VERSION 5.8 ;
BUSBITCHARS "[]" ;
DIVIDERCHAR "/" ;
UNITS
    DATABASE MICRONS 1000 ;
END UNITS

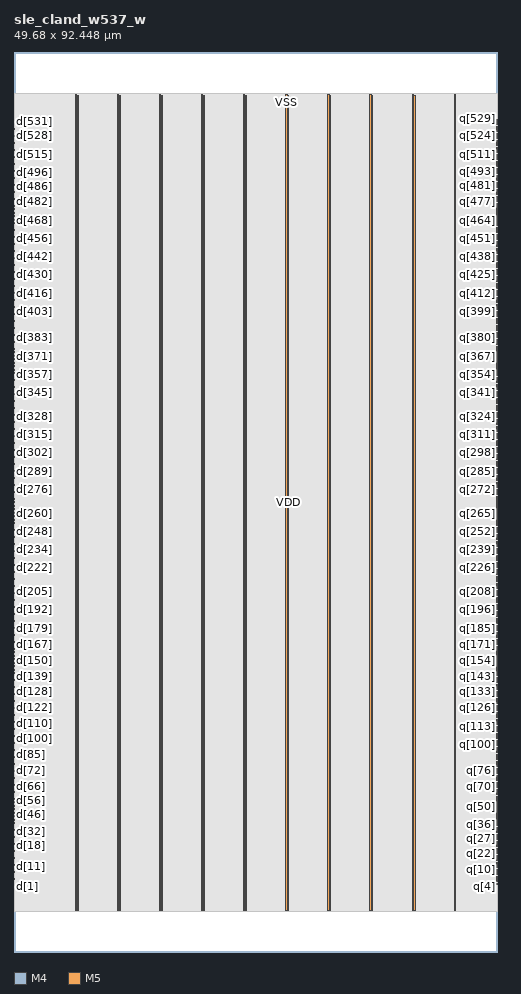
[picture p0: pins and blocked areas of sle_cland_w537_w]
MACRO sle_cland_w537_w
  FOREIGN sle_cland_w537_w 0 0 ;
  CLASS BLOCK ;
  SIZE 49.68 BY 92.448 ;
  PIN clk
    DIRECTION INPUT ;
    USE SIGNAL ;
    PORT
      LAYER M4 ;
        RECT  49.596 45.504 49.68 45.528 ;
    END
  END clk
  PIN d[0]
    DIRECTION INPUT ;
    USE SIGNAL ;
    PORT
      LAYER M4 ;
        RECT  0 7.632 0.084 7.656 ;
    END
  END d[0]
  PIN d[100]
    DIRECTION INPUT ;
    USE SIGNAL ;
    PORT
      LAYER M4 ;
        RECT  0 21.888 0.084 21.912 ;
    END
  END d[100]
  PIN d[101]
    DIRECTION INPUT ;
    USE SIGNAL ;
    PORT
      LAYER M4 ;
        RECT  0 22.032 0.084 22.056 ;
    END
  END d[101]
  PIN d[102]
    DIRECTION INPUT ;
    USE SIGNAL ;
    PORT
      LAYER M4 ;
        RECT  0 22.176 0.084 22.2 ;
    END
  END d[102]
  PIN d[103]
    DIRECTION INPUT ;
    USE SIGNAL ;
    PORT
      LAYER M4 ;
        RECT  0 22.32 0.084 22.344 ;
    END
  END d[103]
  PIN d[104]
    DIRECTION INPUT ;
    USE SIGNAL ;
    PORT
      LAYER M4 ;
        RECT  0 22.464 0.084 22.488 ;
    END
  END d[104]
  PIN d[105]
    DIRECTION INPUT ;
    USE SIGNAL ;
    PORT
      LAYER M4 ;
        RECT  0 22.608 0.084 22.632 ;
    END
  END d[105]
  PIN d[106]
    DIRECTION INPUT ;
    USE SIGNAL ;
    PORT
      LAYER M4 ;
        RECT  0 22.752 0.084 22.776 ;
    END
  END d[106]
  PIN d[107]
    DIRECTION INPUT ;
    USE SIGNAL ;
    PORT
      LAYER M4 ;
        RECT  0 22.896 0.084 22.92 ;
    END
  END d[107]
  PIN d[108]
    DIRECTION INPUT ;
    USE SIGNAL ;
    PORT
      LAYER M4 ;
        RECT  0 23.328 0.084 23.352 ;
    END
  END d[108]
  PIN d[109]
    DIRECTION INPUT ;
    USE SIGNAL ;
    PORT
      LAYER M4 ;
        RECT  0 23.04 0.084 23.064 ;
    END
  END d[109]
  PIN d[10]
    DIRECTION INPUT ;
    USE SIGNAL ;
    PORT
      LAYER M4 ;
        RECT  0 9.072 0.084 9.096 ;
    END
  END d[10]
  PIN d[110]
    DIRECTION INPUT ;
    USE SIGNAL ;
    PORT
      LAYER M4 ;
        RECT  0 23.472 0.084 23.496 ;
    END
  END d[110]
  PIN d[111]
    DIRECTION INPUT ;
    USE SIGNAL ;
    PORT
      LAYER M4 ;
        RECT  0 23.184 0.084 23.208 ;
    END
  END d[111]
  PIN d[112]
    DIRECTION INPUT ;
    USE SIGNAL ;
    PORT
      LAYER M4 ;
        RECT  0 23.616 0.084 23.64 ;
    END
  END d[112]
  PIN d[113]
    DIRECTION INPUT ;
    USE SIGNAL ;
    PORT
      LAYER M4 ;
        RECT  0 23.76 0.084 23.784 ;
    END
  END d[113]
  PIN d[114]
    DIRECTION INPUT ;
    USE SIGNAL ;
    PORT
      LAYER M4 ;
        RECT  0 23.904 0.084 23.928 ;
    END
  END d[114]
  PIN d[115]
    DIRECTION INPUT ;
    USE SIGNAL ;
    PORT
      LAYER M4 ;
        RECT  0 24.048 0.084 24.072 ;
    END
  END d[115]
  PIN d[116]
    DIRECTION INPUT ;
    USE SIGNAL ;
    PORT
      LAYER M4 ;
        RECT  0 24.192 0.084 24.216 ;
    END
  END d[116]
  PIN d[117]
    DIRECTION INPUT ;
    USE SIGNAL ;
    PORT
      LAYER M4 ;
        RECT  0 24.336 0.084 24.36 ;
    END
  END d[117]
  PIN d[118]
    DIRECTION INPUT ;
    USE SIGNAL ;
    PORT
      LAYER M4 ;
        RECT  0 24.48 0.084 24.504 ;
    END
  END d[118]
  PIN d[119]
    DIRECTION INPUT ;
    USE SIGNAL ;
    PORT
      LAYER M4 ;
        RECT  0 24.624 0.084 24.648 ;
    END
  END d[119]
  PIN d[11]
    DIRECTION INPUT ;
    USE SIGNAL ;
    PORT
      LAYER M4 ;
        RECT  0 8.784 0.084 8.808 ;
    END
  END d[11]
  PIN d[120]
    DIRECTION INPUT ;
    USE SIGNAL ;
    PORT
      LAYER M4 ;
        RECT  0 24.768 0.084 24.792 ;
    END
  END d[120]
  PIN d[121]
    DIRECTION INPUT ;
    USE SIGNAL ;
    PORT
      LAYER M4 ;
        RECT  0 24.912 0.084 24.936 ;
    END
  END d[121]
  PIN d[122]
    DIRECTION INPUT ;
    USE SIGNAL ;
    PORT
      LAYER M4 ;
        RECT  0 25.056 0.084 25.08 ;
    END
  END d[122]
  PIN d[123]
    DIRECTION INPUT ;
    USE SIGNAL ;
    PORT
      LAYER M4 ;
        RECT  0 25.2 0.084 25.224 ;
    END
  END d[123]
  PIN d[124]
    DIRECTION INPUT ;
    USE SIGNAL ;
    PORT
      LAYER M4 ;
        RECT  0 25.344 0.084 25.368 ;
    END
  END d[124]
  PIN d[125]
    DIRECTION INPUT ;
    USE SIGNAL ;
    PORT
      LAYER M4 ;
        RECT  0 25.488 0.084 25.512 ;
    END
  END d[125]
  PIN d[126]
    DIRECTION INPUT ;
    USE SIGNAL ;
    PORT
      LAYER M4 ;
        RECT  0 25.632 0.084 25.656 ;
    END
  END d[126]
  PIN d[127]
    DIRECTION INPUT ;
    USE SIGNAL ;
    PORT
      LAYER M4 ;
        RECT  0 25.776 0.084 25.8 ;
    END
  END d[127]
  PIN d[128]
    DIRECTION INPUT ;
    USE SIGNAL ;
    PORT
      LAYER M4 ;
        RECT  0 25.92 0.084 25.944 ;
    END
  END d[128]
  PIN d[129]
    DIRECTION INPUT ;
    USE SIGNAL ;
    PORT
      LAYER M4 ;
        RECT  0 26.064 0.084 26.088 ;
    END
  END d[129]
  PIN d[12]
    DIRECTION INPUT ;
    USE SIGNAL ;
    PORT
      LAYER M4 ;
        RECT  0 9.36 0.084 9.384 ;
    END
  END d[12]
  PIN d[130]
    DIRECTION INPUT ;
    USE SIGNAL ;
    PORT
      LAYER M4 ;
        RECT  0 26.208 0.084 26.232 ;
    END
  END d[130]
  PIN d[131]
    DIRECTION INPUT ;
    USE SIGNAL ;
    PORT
      LAYER M4 ;
        RECT  0 26.352 0.084 26.376 ;
    END
  END d[131]
  PIN d[132]
    DIRECTION INPUT ;
    USE SIGNAL ;
    PORT
      LAYER M4 ;
        RECT  0 26.784 0.084 26.808 ;
    END
  END d[132]
  PIN d[133]
    DIRECTION INPUT ;
    USE SIGNAL ;
    PORT
      LAYER M4 ;
        RECT  0 26.496 0.084 26.52 ;
    END
  END d[133]
  PIN d[134]
    DIRECTION INPUT ;
    USE SIGNAL ;
    PORT
      LAYER M4 ;
        RECT  0 26.928 0.084 26.952 ;
    END
  END d[134]
  PIN d[135]
    DIRECTION INPUT ;
    USE SIGNAL ;
    PORT
      LAYER M4 ;
        RECT  0 26.64 0.084 26.664 ;
    END
  END d[135]
  PIN d[136]
    DIRECTION INPUT ;
    USE SIGNAL ;
    PORT
      LAYER M4 ;
        RECT  0 27.216 0.084 27.24 ;
    END
  END d[136]
  PIN d[137]
    DIRECTION INPUT ;
    USE SIGNAL ;
    PORT
      LAYER M4 ;
        RECT  0 27.072 0.084 27.096 ;
    END
  END d[137]
  PIN d[138]
    DIRECTION INPUT ;
    USE SIGNAL ;
    PORT
      LAYER M4 ;
        RECT  0 27.36 0.084 27.384 ;
    END
  END d[138]
  PIN d[139]
    DIRECTION INPUT ;
    USE SIGNAL ;
    PORT
      LAYER M4 ;
        RECT  0 27.504 0.084 27.528 ;
    END
  END d[139]
  PIN d[13]
    DIRECTION INPUT ;
    USE SIGNAL ;
    PORT
      LAYER M4 ;
        RECT  0 9.216 0.084 9.24 ;
    END
  END d[13]
  PIN d[140]
    DIRECTION INPUT ;
    USE SIGNAL ;
    PORT
      LAYER M4 ;
        RECT  0 27.648 0.084 27.672 ;
    END
  END d[140]
  PIN d[141]
    DIRECTION INPUT ;
    USE SIGNAL ;
    PORT
      LAYER M4 ;
        RECT  0 27.792 0.084 27.816 ;
    END
  END d[141]
  PIN d[142]
    DIRECTION INPUT ;
    USE SIGNAL ;
    PORT
      LAYER M4 ;
        RECT  0 27.936 0.084 27.96 ;
    END
  END d[142]
  PIN d[143]
    DIRECTION INPUT ;
    USE SIGNAL ;
    PORT
      LAYER M4 ;
        RECT  0 28.08 0.084 28.104 ;
    END
  END d[143]
  PIN d[144]
    DIRECTION INPUT ;
    USE SIGNAL ;
    PORT
      LAYER M4 ;
        RECT  0 28.224 0.084 28.248 ;
    END
  END d[144]
  PIN d[145]
    DIRECTION INPUT ;
    USE SIGNAL ;
    PORT
      LAYER M4 ;
        RECT  0 28.368 0.084 28.392 ;
    END
  END d[145]
  PIN d[146]
    DIRECTION INPUT ;
    USE SIGNAL ;
    PORT
      LAYER M4 ;
        RECT  0 28.512 0.084 28.536 ;
    END
  END d[146]
  PIN d[147]
    DIRECTION INPUT ;
    USE SIGNAL ;
    PORT
      LAYER M4 ;
        RECT  0 28.656 0.084 28.68 ;
    END
  END d[147]
  PIN d[148]
    DIRECTION INPUT ;
    USE SIGNAL ;
    PORT
      LAYER M4 ;
        RECT  0 28.8 0.084 28.824 ;
    END
  END d[148]
  PIN d[149]
    DIRECTION INPUT ;
    USE SIGNAL ;
    PORT
      LAYER M4 ;
        RECT  0 28.944 0.084 28.968 ;
    END
  END d[149]
  PIN d[14]
    DIRECTION INPUT ;
    USE SIGNAL ;
    PORT
      LAYER M4 ;
        RECT  0 9.504 0.084 9.528 ;
    END
  END d[14]
  PIN d[150]
    DIRECTION INPUT ;
    USE SIGNAL ;
    PORT
      LAYER M4 ;
        RECT  0 29.088 0.084 29.112 ;
    END
  END d[150]
  PIN d[151]
    DIRECTION INPUT ;
    USE SIGNAL ;
    PORT
      LAYER M4 ;
        RECT  0 29.232 0.084 29.256 ;
    END
  END d[151]
  PIN d[152]
    DIRECTION INPUT ;
    USE SIGNAL ;
    PORT
      LAYER M4 ;
        RECT  0 29.376 0.084 29.4 ;
    END
  END d[152]
  PIN d[153]
    DIRECTION INPUT ;
    USE SIGNAL ;
    PORT
      LAYER M4 ;
        RECT  0 29.52 0.084 29.544 ;
    END
  END d[153]
  PIN d[154]
    DIRECTION INPUT ;
    USE SIGNAL ;
    PORT
      LAYER M4 ;
        RECT  0 29.664 0.084 29.688 ;
    END
  END d[154]
  PIN d[155]
    DIRECTION INPUT ;
    USE SIGNAL ;
    PORT
      LAYER M4 ;
        RECT  0 29.808 0.084 29.832 ;
    END
  END d[155]
  PIN d[156]
    DIRECTION INPUT ;
    USE SIGNAL ;
    PORT
      LAYER M4 ;
        RECT  0 29.952 0.084 29.976 ;
    END
  END d[156]
  PIN d[157]
    DIRECTION INPUT ;
    USE SIGNAL ;
    PORT
      LAYER M4 ;
        RECT  0 30.096 0.084 30.12 ;
    END
  END d[157]
  PIN d[158]
    DIRECTION INPUT ;
    USE SIGNAL ;
    PORT
      LAYER M4 ;
        RECT  0 30.384 0.084 30.408 ;
    END
  END d[158]
  PIN d[159]
    DIRECTION INPUT ;
    USE SIGNAL ;
    PORT
      LAYER M4 ;
        RECT  0 30.24 0.084 30.264 ;
    END
  END d[159]
  PIN d[15]
    DIRECTION INPUT ;
    USE SIGNAL ;
    PORT
      LAYER M4 ;
        RECT  0 9.648 0.084 9.672 ;
    END
  END d[15]
  PIN d[160]
    DIRECTION INPUT ;
    USE SIGNAL ;
    PORT
      LAYER M4 ;
        RECT  0 30.672 0.084 30.696 ;
    END
  END d[160]
  PIN d[161]
    DIRECTION INPUT ;
    USE SIGNAL ;
    PORT
      LAYER M4 ;
        RECT  0 30.528 0.084 30.552 ;
    END
  END d[161]
  PIN d[162]
    DIRECTION INPUT ;
    USE SIGNAL ;
    PORT
      LAYER M4 ;
        RECT  0 30.816 0.084 30.84 ;
    END
  END d[162]
  PIN d[163]
    DIRECTION INPUT ;
    USE SIGNAL ;
    PORT
      LAYER M4 ;
        RECT  0 30.96 0.084 30.984 ;
    END
  END d[163]
  PIN d[164]
    DIRECTION INPUT ;
    USE SIGNAL ;
    PORT
      LAYER M4 ;
        RECT  0 31.104 0.084 31.128 ;
    END
  END d[164]
  PIN d[165]
    DIRECTION INPUT ;
    USE SIGNAL ;
    PORT
      LAYER M4 ;
        RECT  0 31.248 0.084 31.272 ;
    END
  END d[165]
  PIN d[166]
    DIRECTION INPUT ;
    USE SIGNAL ;
    PORT
      LAYER M4 ;
        RECT  0 31.392 0.084 31.416 ;
    END
  END d[166]
  PIN d[167]
    DIRECTION INPUT ;
    USE SIGNAL ;
    PORT
      LAYER M4 ;
        RECT  0 31.536 0.084 31.56 ;
    END
  END d[167]
  PIN d[168]
    DIRECTION INPUT ;
    USE SIGNAL ;
    PORT
      LAYER M4 ;
        RECT  0 31.68 0.084 31.704 ;
    END
  END d[168]
  PIN d[169]
    DIRECTION INPUT ;
    USE SIGNAL ;
    PORT
      LAYER M4 ;
        RECT  0 31.824 0.084 31.848 ;
    END
  END d[169]
  PIN d[16]
    DIRECTION INPUT ;
    USE SIGNAL ;
    PORT
      LAYER M4 ;
        RECT  0 9.792 0.084 9.816 ;
    END
  END d[16]
  PIN d[170]
    DIRECTION INPUT ;
    USE SIGNAL ;
    PORT
      LAYER M4 ;
        RECT  0 31.968 0.084 31.992 ;
    END
  END d[170]
  PIN d[171]
    DIRECTION INPUT ;
    USE SIGNAL ;
    PORT
      LAYER M4 ;
        RECT  0 32.112 0.084 32.136 ;
    END
  END d[171]
  PIN d[172]
    DIRECTION INPUT ;
    USE SIGNAL ;
    PORT
      LAYER M4 ;
        RECT  0 32.256 0.084 32.28 ;
    END
  END d[172]
  PIN d[173]
    DIRECTION INPUT ;
    USE SIGNAL ;
    PORT
      LAYER M4 ;
        RECT  0 32.4 0.084 32.424 ;
    END
  END d[173]
  PIN d[174]
    DIRECTION INPUT ;
    USE SIGNAL ;
    PORT
      LAYER M4 ;
        RECT  0 32.544 0.084 32.568 ;
    END
  END d[174]
  PIN d[175]
    DIRECTION INPUT ;
    USE SIGNAL ;
    PORT
      LAYER M4 ;
        RECT  0 32.688 0.084 32.712 ;
    END
  END d[175]
  PIN d[176]
    DIRECTION INPUT ;
    USE SIGNAL ;
    PORT
      LAYER M4 ;
        RECT  0 32.832 0.084 32.856 ;
    END
  END d[176]
  PIN d[177]
    DIRECTION INPUT ;
    USE SIGNAL ;
    PORT
      LAYER M4 ;
        RECT  0 32.976 0.084 33 ;
    END
  END d[177]
  PIN d[178]
    DIRECTION INPUT ;
    USE SIGNAL ;
    PORT
      LAYER M4 ;
        RECT  0 33.12 0.084 33.144 ;
    END
  END d[178]
  PIN d[179]
    DIRECTION INPUT ;
    USE SIGNAL ;
    PORT
      LAYER M4 ;
        RECT  0 33.264 0.084 33.288 ;
    END
  END d[179]
  PIN d[17]
    DIRECTION INPUT ;
    USE SIGNAL ;
    PORT
      LAYER M4 ;
        RECT  0 9.936 0.084 9.96 ;
    END
  END d[17]
  PIN d[180]
    DIRECTION INPUT ;
    USE SIGNAL ;
    PORT
      LAYER M4 ;
        RECT  0 33.408 0.084 33.432 ;
    END
  END d[180]
  PIN d[181]
    DIRECTION INPUT ;
    USE SIGNAL ;
    PORT
      LAYER M4 ;
        RECT  0 33.552 0.084 33.576 ;
    END
  END d[181]
  PIN d[182]
    DIRECTION INPUT ;
    USE SIGNAL ;
    PORT
      LAYER M4 ;
        RECT  0 33.984 0.084 34.008 ;
    END
  END d[182]
  PIN d[183]
    DIRECTION INPUT ;
    USE SIGNAL ;
    PORT
      LAYER M4 ;
        RECT  0 33.696 0.084 33.72 ;
    END
  END d[183]
  PIN d[184]
    DIRECTION INPUT ;
    USE SIGNAL ;
    PORT
      LAYER M4 ;
        RECT  0 34.128 0.084 34.152 ;
    END
  END d[184]
  PIN d[185]
    DIRECTION INPUT ;
    USE SIGNAL ;
    PORT
      LAYER M4 ;
        RECT  0 33.84 0.084 33.864 ;
    END
  END d[185]
  PIN d[186]
    DIRECTION INPUT ;
    USE SIGNAL ;
    PORT
      LAYER M4 ;
        RECT  0 34.416 0.084 34.44 ;
    END
  END d[186]
  PIN d[187]
    DIRECTION INPUT ;
    USE SIGNAL ;
    PORT
      LAYER M4 ;
        RECT  0 34.272 0.084 34.296 ;
    END
  END d[187]
  PIN d[188]
    DIRECTION INPUT ;
    USE SIGNAL ;
    PORT
      LAYER M4 ;
        RECT  0 34.56 0.084 34.584 ;
    END
  END d[188]
  PIN d[189]
    DIRECTION INPUT ;
    USE SIGNAL ;
    PORT
      LAYER M4 ;
        RECT  0 34.704 0.084 34.728 ;
    END
  END d[189]
  PIN d[18]
    DIRECTION INPUT ;
    USE SIGNAL ;
    PORT
      LAYER M4 ;
        RECT  0 10.08 0.084 10.104 ;
    END
  END d[18]
  PIN d[190]
    DIRECTION INPUT ;
    USE SIGNAL ;
    PORT
      LAYER M4 ;
        RECT  0 34.848 0.084 34.872 ;
    END
  END d[190]
  PIN d[191]
    DIRECTION INPUT ;
    USE SIGNAL ;
    PORT
      LAYER M4 ;
        RECT  0 34.992 0.084 35.016 ;
    END
  END d[191]
  PIN d[192]
    DIRECTION INPUT ;
    USE SIGNAL ;
    PORT
      LAYER M4 ;
        RECT  0 35.136 0.084 35.16 ;
    END
  END d[192]
  PIN d[193]
    DIRECTION INPUT ;
    USE SIGNAL ;
    PORT
      LAYER M4 ;
        RECT  0 35.28 0.084 35.304 ;
    END
  END d[193]
  PIN d[194]
    DIRECTION INPUT ;
    USE SIGNAL ;
    PORT
      LAYER M4 ;
        RECT  0 35.424 0.084 35.448 ;
    END
  END d[194]
  PIN d[195]
    DIRECTION INPUT ;
    USE SIGNAL ;
    PORT
      LAYER M4 ;
        RECT  0 35.568 0.084 35.592 ;
    END
  END d[195]
  PIN d[196]
    DIRECTION INPUT ;
    USE SIGNAL ;
    PORT
      LAYER M4 ;
        RECT  0 35.712 0.084 35.736 ;
    END
  END d[196]
  PIN d[197]
    DIRECTION INPUT ;
    USE SIGNAL ;
    PORT
      LAYER M4 ;
        RECT  0 35.856 0.084 35.88 ;
    END
  END d[197]
  PIN d[198]
    DIRECTION INPUT ;
    USE SIGNAL ;
    PORT
      LAYER M4 ;
        RECT  0 36 0.084 36.024 ;
    END
  END d[198]
  PIN d[199]
    DIRECTION INPUT ;
    USE SIGNAL ;
    PORT
      LAYER M4 ;
        RECT  0 36.144 0.084 36.168 ;
    END
  END d[199]
  PIN d[19]
    DIRECTION INPUT ;
    USE SIGNAL ;
    PORT
      LAYER M4 ;
        RECT  0 10.224 0.084 10.248 ;
    END
  END d[19]
  PIN d[1]
    DIRECTION INPUT ;
    USE SIGNAL ;
    PORT
      LAYER M4 ;
        RECT  0 7.488 0.084 7.512 ;
    END
  END d[1]
  PIN d[200]
    DIRECTION INPUT ;
    USE SIGNAL ;
    PORT
      LAYER M4 ;
        RECT  0 36.288 0.084 36.312 ;
    END
  END d[200]
  PIN d[201]
    DIRECTION INPUT ;
    USE SIGNAL ;
    PORT
      LAYER M4 ;
        RECT  0 36.432 0.084 36.456 ;
    END
  END d[201]
  PIN d[202]
    DIRECTION INPUT ;
    USE SIGNAL ;
    PORT
      LAYER M4 ;
        RECT  0 36.576 0.084 36.6 ;
    END
  END d[202]
  PIN d[203]
    DIRECTION INPUT ;
    USE SIGNAL ;
    PORT
      LAYER M4 ;
        RECT  0 36.72 0.084 36.744 ;
    END
  END d[203]
  PIN d[204]
    DIRECTION INPUT ;
    USE SIGNAL ;
    PORT
      LAYER M4 ;
        RECT  0 36.864 0.084 36.888 ;
    END
  END d[204]
  PIN d[205]
    DIRECTION INPUT ;
    USE SIGNAL ;
    PORT
      LAYER M4 ;
        RECT  0 37.008 0.084 37.032 ;
    END
  END d[205]
  PIN d[206]
    DIRECTION INPUT ;
    USE SIGNAL ;
    PORT
      LAYER M4 ;
        RECT  0 37.152 0.084 37.176 ;
    END
  END d[206]
  PIN d[207]
    DIRECTION INPUT ;
    USE SIGNAL ;
    PORT
      LAYER M4 ;
        RECT  0 37.296 0.084 37.32 ;
    END
  END d[207]
  PIN d[208]
    DIRECTION INPUT ;
    USE SIGNAL ;
    PORT
      LAYER M4 ;
        RECT  0 37.584 0.084 37.608 ;
    END
  END d[208]
  PIN d[209]
    DIRECTION INPUT ;
    USE SIGNAL ;
    PORT
      LAYER M4 ;
        RECT  0 37.44 0.084 37.464 ;
    END
  END d[209]
  PIN d[20]
    DIRECTION INPUT ;
    USE SIGNAL ;
    PORT
      LAYER M4 ;
        RECT  0 10.512 0.084 10.536 ;
    END
  END d[20]
  PIN d[210]
    DIRECTION INPUT ;
    USE SIGNAL ;
    PORT
      LAYER M4 ;
        RECT  0 37.872 0.084 37.896 ;
    END
  END d[210]
  PIN d[211]
    DIRECTION INPUT ;
    USE SIGNAL ;
    PORT
      LAYER M4 ;
        RECT  0 37.728 0.084 37.752 ;
    END
  END d[211]
  PIN d[212]
    DIRECTION INPUT ;
    USE SIGNAL ;
    PORT
      LAYER M4 ;
        RECT  0 38.016 0.084 38.04 ;
    END
  END d[212]
  PIN d[213]
    DIRECTION INPUT ;
    USE SIGNAL ;
    PORT
      LAYER M4 ;
        RECT  0 38.16 0.084 38.184 ;
    END
  END d[213]
  PIN d[214]
    DIRECTION INPUT ;
    USE SIGNAL ;
    PORT
      LAYER M4 ;
        RECT  0 38.304 0.084 38.328 ;
    END
  END d[214]
  PIN d[215]
    DIRECTION INPUT ;
    USE SIGNAL ;
    PORT
      LAYER M4 ;
        RECT  0 38.448 0.084 38.472 ;
    END
  END d[215]
  PIN d[216]
    DIRECTION INPUT ;
    USE SIGNAL ;
    PORT
      LAYER M4 ;
        RECT  0 38.592 0.084 38.616 ;
    END
  END d[216]
  PIN d[217]
    DIRECTION INPUT ;
    USE SIGNAL ;
    PORT
      LAYER M4 ;
        RECT  0 38.736 0.084 38.76 ;
    END
  END d[217]
  PIN d[218]
    DIRECTION INPUT ;
    USE SIGNAL ;
    PORT
      LAYER M4 ;
        RECT  0 38.88 0.084 38.904 ;
    END
  END d[218]
  PIN d[219]
    DIRECTION INPUT ;
    USE SIGNAL ;
    PORT
      LAYER M4 ;
        RECT  0 39.024 0.084 39.048 ;
    END
  END d[219]
  PIN d[21]
    DIRECTION INPUT ;
    USE SIGNAL ;
    PORT
      LAYER M4 ;
        RECT  0 10.368 0.084 10.392 ;
    END
  END d[21]
  PIN d[220]
    DIRECTION INPUT ;
    USE SIGNAL ;
    PORT
      LAYER M4 ;
        RECT  0 39.168 0.084 39.192 ;
    END
  END d[220]
  PIN d[221]
    DIRECTION INPUT ;
    USE SIGNAL ;
    PORT
      LAYER M4 ;
        RECT  0 39.312 0.084 39.336 ;
    END
  END d[221]
  PIN d[222]
    DIRECTION INPUT ;
    USE SIGNAL ;
    PORT
      LAYER M4 ;
        RECT  0 39.456 0.084 39.48 ;
    END
  END d[222]
  PIN d[223]
    DIRECTION INPUT ;
    USE SIGNAL ;
    PORT
      LAYER M4 ;
        RECT  0 39.6 0.084 39.624 ;
    END
  END d[223]
  PIN d[224]
    DIRECTION INPUT ;
    USE SIGNAL ;
    PORT
      LAYER M4 ;
        RECT  0 39.744 0.084 39.768 ;
    END
  END d[224]
  PIN d[225]
    DIRECTION INPUT ;
    USE SIGNAL ;
    PORT
      LAYER M4 ;
        RECT  0 39.888 0.084 39.912 ;
    END
  END d[225]
  PIN d[226]
    DIRECTION INPUT ;
    USE SIGNAL ;
    PORT
      LAYER M4 ;
        RECT  0 40.032 0.084 40.056 ;
    END
  END d[226]
  PIN d[227]
    DIRECTION INPUT ;
    USE SIGNAL ;
    PORT
      LAYER M4 ;
        RECT  0 40.176 0.084 40.2 ;
    END
  END d[227]
  PIN d[228]
    DIRECTION INPUT ;
    USE SIGNAL ;
    PORT
      LAYER M4 ;
        RECT  0 40.32 0.084 40.344 ;
    END
  END d[228]
  PIN d[229]
    DIRECTION INPUT ;
    USE SIGNAL ;
    PORT
      LAYER M4 ;
        RECT  0 40.464 0.084 40.488 ;
    END
  END d[229]
  PIN d[22]
    DIRECTION INPUT ;
    USE SIGNAL ;
    PORT
      LAYER M4 ;
        RECT  0 10.656 0.084 10.68 ;
    END
  END d[22]
  PIN d[230]
    DIRECTION INPUT ;
    USE SIGNAL ;
    PORT
      LAYER M4 ;
        RECT  0 40.608 0.084 40.632 ;
    END
  END d[230]
  PIN d[231]
    DIRECTION INPUT ;
    USE SIGNAL ;
    PORT
      LAYER M4 ;
        RECT  0 40.752 0.084 40.776 ;
    END
  END d[231]
  PIN d[232]
    DIRECTION INPUT ;
    USE SIGNAL ;
    PORT
      LAYER M4 ;
        RECT  0 41.184 0.084 41.208 ;
    END
  END d[232]
  PIN d[233]
    DIRECTION INPUT ;
    USE SIGNAL ;
    PORT
      LAYER M4 ;
        RECT  0 40.896 0.084 40.92 ;
    END
  END d[233]
  PIN d[234]
    DIRECTION INPUT ;
    USE SIGNAL ;
    PORT
      LAYER M4 ;
        RECT  0 41.328 0.084 41.352 ;
    END
  END d[234]
  PIN d[235]
    DIRECTION INPUT ;
    USE SIGNAL ;
    PORT
      LAYER M4 ;
        RECT  0 41.04 0.084 41.064 ;
    END
  END d[235]
  PIN d[236]
    DIRECTION INPUT ;
    USE SIGNAL ;
    PORT
      LAYER M4 ;
        RECT  0 41.472 0.084 41.496 ;
    END
  END d[236]
  PIN d[237]
    DIRECTION INPUT ;
    USE SIGNAL ;
    PORT
      LAYER M4 ;
        RECT  0 41.616 0.084 41.64 ;
    END
  END d[237]
  PIN d[238]
    DIRECTION INPUT ;
    USE SIGNAL ;
    PORT
      LAYER M4 ;
        RECT  0 41.76 0.084 41.784 ;
    END
  END d[238]
  PIN d[239]
    DIRECTION INPUT ;
    USE SIGNAL ;
    PORT
      LAYER M4 ;
        RECT  0 41.904 0.084 41.928 ;
    END
  END d[239]
  PIN d[23]
    DIRECTION INPUT ;
    USE SIGNAL ;
    PORT
      LAYER M4 ;
        RECT  0 10.8 0.084 10.824 ;
    END
  END d[23]
  PIN d[240]
    DIRECTION INPUT ;
    USE SIGNAL ;
    PORT
      LAYER M4 ;
        RECT  0 42.048 0.084 42.072 ;
    END
  END d[240]
  PIN d[241]
    DIRECTION INPUT ;
    USE SIGNAL ;
    PORT
      LAYER M4 ;
        RECT  0 42.192 0.084 42.216 ;
    END
  END d[241]
  PIN d[242]
    DIRECTION INPUT ;
    USE SIGNAL ;
    PORT
      LAYER M4 ;
        RECT  0 42.336 0.084 42.36 ;
    END
  END d[242]
  PIN d[243]
    DIRECTION INPUT ;
    USE SIGNAL ;
    PORT
      LAYER M4 ;
        RECT  0 42.48 0.084 42.504 ;
    END
  END d[243]
  PIN d[244]
    DIRECTION INPUT ;
    USE SIGNAL ;
    PORT
      LAYER M4 ;
        RECT  0 42.624 0.084 42.648 ;
    END
  END d[244]
  PIN d[245]
    DIRECTION INPUT ;
    USE SIGNAL ;
    PORT
      LAYER M4 ;
        RECT  0 42.768 0.084 42.792 ;
    END
  END d[245]
  PIN d[246]
    DIRECTION INPUT ;
    USE SIGNAL ;
    PORT
      LAYER M4 ;
        RECT  0 42.912 0.084 42.936 ;
    END
  END d[246]
  PIN d[247]
    DIRECTION INPUT ;
    USE SIGNAL ;
    PORT
      LAYER M4 ;
        RECT  0 43.056 0.084 43.08 ;
    END
  END d[247]
  PIN d[248]
    DIRECTION INPUT ;
    USE SIGNAL ;
    PORT
      LAYER M4 ;
        RECT  0 43.2 0.084 43.224 ;
    END
  END d[248]
  PIN d[249]
    DIRECTION INPUT ;
    USE SIGNAL ;
    PORT
      LAYER M4 ;
        RECT  0 43.344 0.084 43.368 ;
    END
  END d[249]
  PIN d[24]
    DIRECTION INPUT ;
    USE SIGNAL ;
    PORT
      LAYER M4 ;
        RECT  0 10.944 0.084 10.968 ;
    END
  END d[24]
  PIN d[250]
    DIRECTION INPUT ;
    USE SIGNAL ;
    PORT
      LAYER M4 ;
        RECT  0 43.488 0.084 43.512 ;
    END
  END d[250]
  PIN d[251]
    DIRECTION INPUT ;
    USE SIGNAL ;
    PORT
      LAYER M4 ;
        RECT  0 43.632 0.084 43.656 ;
    END
  END d[251]
  PIN d[252]
    DIRECTION INPUT ;
    USE SIGNAL ;
    PORT
      LAYER M4 ;
        RECT  0 43.776 0.084 43.8 ;
    END
  END d[252]
  PIN d[253]
    DIRECTION INPUT ;
    USE SIGNAL ;
    PORT
      LAYER M4 ;
        RECT  0 43.92 0.084 43.944 ;
    END
  END d[253]
  PIN d[254]
    DIRECTION INPUT ;
    USE SIGNAL ;
    PORT
      LAYER M4 ;
        RECT  0 44.064 0.084 44.088 ;
    END
  END d[254]
  PIN d[255]
    DIRECTION INPUT ;
    USE SIGNAL ;
    PORT
      LAYER M4 ;
        RECT  0 44.352 0.084 44.376 ;
    END
  END d[255]
  PIN d[256]
    DIRECTION INPUT ;
    USE SIGNAL ;
    PORT
      LAYER M4 ;
        RECT  0 44.208 0.084 44.232 ;
    END
  END d[256]
  PIN d[257]
    DIRECTION INPUT ;
    USE SIGNAL ;
    PORT
      LAYER M4 ;
        RECT  0 44.496 0.084 44.52 ;
    END
  END d[257]
  PIN d[258]
    DIRECTION INPUT ;
    USE SIGNAL ;
    PORT
      LAYER M4 ;
        RECT  0 44.784 0.084 44.808 ;
    END
  END d[258]
  PIN d[259]
    DIRECTION INPUT ;
    USE SIGNAL ;
    PORT
      LAYER M4 ;
        RECT  0 44.64 0.084 44.664 ;
    END
  END d[259]
  PIN d[25]
    DIRECTION INPUT ;
    USE SIGNAL ;
    PORT
      LAYER M4 ;
        RECT  0 11.088 0.084 11.112 ;
    END
  END d[25]
  PIN d[260]
    DIRECTION INPUT ;
    USE SIGNAL ;
    PORT
      LAYER M4 ;
        RECT  0 45.072 0.084 45.096 ;
    END
  END d[260]
  PIN d[261]
    DIRECTION INPUT ;
    USE SIGNAL ;
    PORT
      LAYER M4 ;
        RECT  0 44.928 0.084 44.952 ;
    END
  END d[261]
  PIN d[262]
    DIRECTION INPUT ;
    USE SIGNAL ;
    PORT
      LAYER M4 ;
        RECT  0 45.216 0.084 45.24 ;
    END
  END d[262]
  PIN d[263]
    DIRECTION INPUT ;
    USE SIGNAL ;
    PORT
      LAYER M4 ;
        RECT  0 45.36 0.084 45.384 ;
    END
  END d[263]
  PIN d[264]
    DIRECTION INPUT ;
    USE SIGNAL ;
    PORT
      LAYER M4 ;
        RECT  0 45.504 0.084 45.528 ;
    END
  END d[264]
  PIN d[265]
    DIRECTION INPUT ;
    USE SIGNAL ;
    PORT
      LAYER M4 ;
        RECT  0 45.648 0.084 45.672 ;
    END
  END d[265]
  PIN d[266]
    DIRECTION INPUT ;
    USE SIGNAL ;
    PORT
      LAYER M4 ;
        RECT  0 45.792 0.084 45.816 ;
    END
  END d[266]
  PIN d[267]
    DIRECTION INPUT ;
    USE SIGNAL ;
    PORT
      LAYER M4 ;
        RECT  0 45.936 0.084 45.96 ;
    END
  END d[267]
  PIN d[268]
    DIRECTION INPUT ;
    USE SIGNAL ;
    PORT
      LAYER M4 ;
        RECT  0 46.368 0.084 46.392 ;
    END
  END d[268]
  PIN d[269]
    DIRECTION INPUT ;
    USE SIGNAL ;
    PORT
      LAYER M4 ;
        RECT  0 46.512 0.084 46.536 ;
    END
  END d[269]
  PIN d[26]
    DIRECTION INPUT ;
    USE SIGNAL ;
    PORT
      LAYER M4 ;
        RECT  0 11.232 0.084 11.256 ;
    END
  END d[26]
  PIN d[270]
    DIRECTION INPUT ;
    USE SIGNAL ;
    PORT
      LAYER M4 ;
        RECT  0 46.656 0.084 46.68 ;
    END
  END d[270]
  PIN d[271]
    DIRECTION INPUT ;
    USE SIGNAL ;
    PORT
      LAYER M4 ;
        RECT  0 46.8 0.084 46.824 ;
    END
  END d[271]
  PIN d[272]
    DIRECTION INPUT ;
    USE SIGNAL ;
    PORT
      LAYER M4 ;
        RECT  0 46.944 0.084 46.968 ;
    END
  END d[272]
  PIN d[273]
    DIRECTION INPUT ;
    USE SIGNAL ;
    PORT
      LAYER M4 ;
        RECT  0 47.088 0.084 47.112 ;
    END
  END d[273]
  PIN d[274]
    DIRECTION INPUT ;
    USE SIGNAL ;
    PORT
      LAYER M4 ;
        RECT  0 47.232 0.084 47.256 ;
    END
  END d[274]
  PIN d[275]
    DIRECTION INPUT ;
    USE SIGNAL ;
    PORT
      LAYER M4 ;
        RECT  0 47.376 0.084 47.4 ;
    END
  END d[275]
  PIN d[276]
    DIRECTION INPUT ;
    USE SIGNAL ;
    PORT
      LAYER M4 ;
        RECT  0 47.52 0.084 47.544 ;
    END
  END d[276]
  PIN d[277]
    DIRECTION INPUT ;
    USE SIGNAL ;
    PORT
      LAYER M4 ;
        RECT  0 47.664 0.084 47.688 ;
    END
  END d[277]
  PIN d[278]
    DIRECTION INPUT ;
    USE SIGNAL ;
    PORT
      LAYER M4 ;
        RECT  0 47.808 0.084 47.832 ;
    END
  END d[278]
  PIN d[279]
    DIRECTION INPUT ;
    USE SIGNAL ;
    PORT
      LAYER M4 ;
        RECT  0 47.952 0.084 47.976 ;
    END
  END d[279]
  PIN d[27]
    DIRECTION INPUT ;
    USE SIGNAL ;
    PORT
      LAYER M4 ;
        RECT  0 11.376 0.084 11.4 ;
    END
  END d[27]
  PIN d[280]
    DIRECTION INPUT ;
    USE SIGNAL ;
    PORT
      LAYER M4 ;
        RECT  0 48.096 0.084 48.12 ;
    END
  END d[280]
  PIN d[281]
    DIRECTION INPUT ;
    USE SIGNAL ;
    PORT
      LAYER M4 ;
        RECT  0 48.528 0.084 48.552 ;
    END
  END d[281]
  PIN d[282]
    DIRECTION INPUT ;
    USE SIGNAL ;
    PORT
      LAYER M4 ;
        RECT  0 48.24 0.084 48.264 ;
    END
  END d[282]
  PIN d[283]
    DIRECTION INPUT ;
    USE SIGNAL ;
    PORT
      LAYER M4 ;
        RECT  0 48.672 0.084 48.696 ;
    END
  END d[283]
  PIN d[284]
    DIRECTION INPUT ;
    USE SIGNAL ;
    PORT
      LAYER M4 ;
        RECT  0 48.384 0.084 48.408 ;
    END
  END d[284]
  PIN d[285]
    DIRECTION INPUT ;
    USE SIGNAL ;
    PORT
      LAYER M4 ;
        RECT  0 48.816 0.084 48.84 ;
    END
  END d[285]
  PIN d[286]
    DIRECTION INPUT ;
    USE SIGNAL ;
    PORT
      LAYER M4 ;
        RECT  0 48.96 0.084 48.984 ;
    END
  END d[286]
  PIN d[287]
    DIRECTION INPUT ;
    USE SIGNAL ;
    PORT
      LAYER M4 ;
        RECT  0 49.104 0.084 49.128 ;
    END
  END d[287]
  PIN d[288]
    DIRECTION INPUT ;
    USE SIGNAL ;
    PORT
      LAYER M4 ;
        RECT  0 49.248 0.084 49.272 ;
    END
  END d[288]
  PIN d[289]
    DIRECTION INPUT ;
    USE SIGNAL ;
    PORT
      LAYER M4 ;
        RECT  0 49.392 0.084 49.416 ;
    END
  END d[289]
  PIN d[28]
    DIRECTION INPUT ;
    USE SIGNAL ;
    PORT
      LAYER M4 ;
        RECT  0 11.52 0.084 11.544 ;
    END
  END d[28]
  PIN d[290]
    DIRECTION INPUT ;
    USE SIGNAL ;
    PORT
      LAYER M4 ;
        RECT  0 49.536 0.084 49.56 ;
    END
  END d[290]
  PIN d[291]
    DIRECTION INPUT ;
    USE SIGNAL ;
    PORT
      LAYER M4 ;
        RECT  0 49.68 0.084 49.704 ;
    END
  END d[291]
  PIN d[292]
    DIRECTION INPUT ;
    USE SIGNAL ;
    PORT
      LAYER M4 ;
        RECT  0 49.824 0.084 49.848 ;
    END
  END d[292]
  PIN d[293]
    DIRECTION INPUT ;
    USE SIGNAL ;
    PORT
      LAYER M4 ;
        RECT  0 49.968 0.084 49.992 ;
    END
  END d[293]
  PIN d[294]
    DIRECTION INPUT ;
    USE SIGNAL ;
    PORT
      LAYER M4 ;
        RECT  0 50.112 0.084 50.136 ;
    END
  END d[294]
  PIN d[295]
    DIRECTION INPUT ;
    USE SIGNAL ;
    PORT
      LAYER M4 ;
        RECT  0 50.256 0.084 50.28 ;
    END
  END d[295]
  PIN d[296]
    DIRECTION INPUT ;
    USE SIGNAL ;
    PORT
      LAYER M4 ;
        RECT  0 50.4 0.084 50.424 ;
    END
  END d[296]
  PIN d[297]
    DIRECTION INPUT ;
    USE SIGNAL ;
    PORT
      LAYER M4 ;
        RECT  0 50.544 0.084 50.568 ;
    END
  END d[297]
  PIN d[298]
    DIRECTION INPUT ;
    USE SIGNAL ;
    PORT
      LAYER M4 ;
        RECT  0 50.688 0.084 50.712 ;
    END
  END d[298]
  PIN d[299]
    DIRECTION INPUT ;
    USE SIGNAL ;
    PORT
      LAYER M4 ;
        RECT  0 50.832 0.084 50.856 ;
    END
  END d[299]
  PIN d[29]
    DIRECTION INPUT ;
    USE SIGNAL ;
    PORT
      LAYER M4 ;
        RECT  0 11.664 0.084 11.688 ;
    END
  END d[29]
  PIN d[2]
    DIRECTION INPUT ;
    USE SIGNAL ;
    PORT
      LAYER M4 ;
        RECT  0 7.92 0.084 7.944 ;
    END
  END d[2]
  PIN d[300]
    DIRECTION INPUT ;
    USE SIGNAL ;
    PORT
      LAYER M4 ;
        RECT  0 50.976 0.084 51 ;
    END
  END d[300]
  PIN d[301]
    DIRECTION INPUT ;
    USE SIGNAL ;
    PORT
      LAYER M4 ;
        RECT  0 51.12 0.084 51.144 ;
    END
  END d[301]
  PIN d[302]
    DIRECTION INPUT ;
    USE SIGNAL ;
    PORT
      LAYER M4 ;
        RECT  0 51.264 0.084 51.288 ;
    END
  END d[302]
  PIN d[303]
    DIRECTION INPUT ;
    USE SIGNAL ;
    PORT
      LAYER M4 ;
        RECT  0 51.408 0.084 51.432 ;
    END
  END d[303]
  PIN d[304]
    DIRECTION INPUT ;
    USE SIGNAL ;
    PORT
      LAYER M4 ;
        RECT  0 51.552 0.084 51.576 ;
    END
  END d[304]
  PIN d[305]
    DIRECTION INPUT ;
    USE SIGNAL ;
    PORT
      LAYER M4 ;
        RECT  0 51.984 0.084 52.008 ;
    END
  END d[305]
  PIN d[306]
    DIRECTION INPUT ;
    USE SIGNAL ;
    PORT
      LAYER M4 ;
        RECT  0 51.696 0.084 51.72 ;
    END
  END d[306]
  PIN d[307]
    DIRECTION INPUT ;
    USE SIGNAL ;
    PORT
      LAYER M4 ;
        RECT  0 52.128 0.084 52.152 ;
    END
  END d[307]
  PIN d[308]
    DIRECTION INPUT ;
    USE SIGNAL ;
    PORT
      LAYER M4 ;
        RECT  0 51.84 0.084 51.864 ;
    END
  END d[308]
  PIN d[309]
    DIRECTION INPUT ;
    USE SIGNAL ;
    PORT
      LAYER M4 ;
        RECT  0 52.272 0.084 52.296 ;
    END
  END d[309]
  PIN d[30]
    DIRECTION INPUT ;
    USE SIGNAL ;
    PORT
      LAYER M4 ;
        RECT  0 11.808 0.084 11.832 ;
    END
  END d[30]
  PIN d[310]
    DIRECTION INPUT ;
    USE SIGNAL ;
    PORT
      LAYER M4 ;
        RECT  0 52.416 0.084 52.44 ;
    END
  END d[310]
  PIN d[311]
    DIRECTION INPUT ;
    USE SIGNAL ;
    PORT
      LAYER M4 ;
        RECT  0 52.56 0.084 52.584 ;
    END
  END d[311]
  PIN d[312]
    DIRECTION INPUT ;
    USE SIGNAL ;
    PORT
      LAYER M4 ;
        RECT  0 52.704 0.084 52.728 ;
    END
  END d[312]
  PIN d[313]
    DIRECTION INPUT ;
    USE SIGNAL ;
    PORT
      LAYER M4 ;
        RECT  0 52.848 0.084 52.872 ;
    END
  END d[313]
  PIN d[314]
    DIRECTION INPUT ;
    USE SIGNAL ;
    PORT
      LAYER M4 ;
        RECT  0 52.992 0.084 53.016 ;
    END
  END d[314]
  PIN d[315]
    DIRECTION INPUT ;
    USE SIGNAL ;
    PORT
      LAYER M4 ;
        RECT  0 53.136 0.084 53.16 ;
    END
  END d[315]
  PIN d[316]
    DIRECTION INPUT ;
    USE SIGNAL ;
    PORT
      LAYER M4 ;
        RECT  0 53.28 0.084 53.304 ;
    END
  END d[316]
  PIN d[317]
    DIRECTION INPUT ;
    USE SIGNAL ;
    PORT
      LAYER M4 ;
        RECT  0 53.424 0.084 53.448 ;
    END
  END d[317]
  PIN d[318]
    DIRECTION INPUT ;
    USE SIGNAL ;
    PORT
      LAYER M4 ;
        RECT  0 53.568 0.084 53.592 ;
    END
  END d[318]
  PIN d[319]
    DIRECTION INPUT ;
    USE SIGNAL ;
    PORT
      LAYER M4 ;
        RECT  0 53.712 0.084 53.736 ;
    END
  END d[319]
  PIN d[31]
    DIRECTION INPUT ;
    USE SIGNAL ;
    PORT
      LAYER M4 ;
        RECT  0 11.952 0.084 11.976 ;
    END
  END d[31]
  PIN d[320]
    DIRECTION INPUT ;
    USE SIGNAL ;
    PORT
      LAYER M4 ;
        RECT  0 53.856 0.084 53.88 ;
    END
  END d[320]
  PIN d[321]
    DIRECTION INPUT ;
    USE SIGNAL ;
    PORT
      LAYER M4 ;
        RECT  0 54 0.084 54.024 ;
    END
  END d[321]
  PIN d[322]
    DIRECTION INPUT ;
    USE SIGNAL ;
    PORT
      LAYER M4 ;
        RECT  0 54.144 0.084 54.168 ;
    END
  END d[322]
  PIN d[323]
    DIRECTION INPUT ;
    USE SIGNAL ;
    PORT
      LAYER M4 ;
        RECT  0 54.288 0.084 54.312 ;
    END
  END d[323]
  PIN d[324]
    DIRECTION INPUT ;
    USE SIGNAL ;
    PORT
      LAYER M4 ;
        RECT  0 54.432 0.084 54.456 ;
    END
  END d[324]
  PIN d[325]
    DIRECTION INPUT ;
    USE SIGNAL ;
    PORT
      LAYER M4 ;
        RECT  0 54.576 0.084 54.6 ;
    END
  END d[325]
  PIN d[326]
    DIRECTION INPUT ;
    USE SIGNAL ;
    PORT
      LAYER M4 ;
        RECT  0 54.72 0.084 54.744 ;
    END
  END d[326]
  PIN d[327]
    DIRECTION INPUT ;
    USE SIGNAL ;
    PORT
      LAYER M4 ;
        RECT  0 54.864 0.084 54.888 ;
    END
  END d[327]
  PIN d[328]
    DIRECTION INPUT ;
    USE SIGNAL ;
    PORT
      LAYER M4 ;
        RECT  0 55.008 0.084 55.032 ;
    END
  END d[328]
  PIN d[329]
    DIRECTION INPUT ;
    USE SIGNAL ;
    PORT
      LAYER M4 ;
        RECT  0 55.152 0.084 55.176 ;
    END
  END d[329]
  PIN d[32]
    DIRECTION INPUT ;
    USE SIGNAL ;
    PORT
      LAYER M4 ;
        RECT  0 12.384 0.084 12.408 ;
    END
  END d[32]
  PIN d[330]
    DIRECTION INPUT ;
    USE SIGNAL ;
    PORT
      LAYER M4 ;
        RECT  0 55.296 0.084 55.32 ;
    END
  END d[330]
  PIN d[331]
    DIRECTION INPUT ;
    USE SIGNAL ;
    PORT
      LAYER M4 ;
        RECT  0 55.728 0.084 55.752 ;
    END
  END d[331]
  PIN d[332]
    DIRECTION INPUT ;
    USE SIGNAL ;
    PORT
      LAYER M4 ;
        RECT  0 55.44 0.084 55.464 ;
    END
  END d[332]
  PIN d[333]
    DIRECTION INPUT ;
    USE SIGNAL ;
    PORT
      LAYER M4 ;
        RECT  0 55.872 0.084 55.896 ;
    END
  END d[333]
  PIN d[334]
    DIRECTION INPUT ;
    USE SIGNAL ;
    PORT
      LAYER M4 ;
        RECT  0 55.584 0.084 55.608 ;
    END
  END d[334]
  PIN d[335]
    DIRECTION INPUT ;
    USE SIGNAL ;
    PORT
      LAYER M4 ;
        RECT  0 56.016 0.084 56.04 ;
    END
  END d[335]
  PIN d[336]
    DIRECTION INPUT ;
    USE SIGNAL ;
    PORT
      LAYER M4 ;
        RECT  0 56.16 0.084 56.184 ;
    END
  END d[336]
  PIN d[337]
    DIRECTION INPUT ;
    USE SIGNAL ;
    PORT
      LAYER M4 ;
        RECT  0 56.304 0.084 56.328 ;
    END
  END d[337]
  PIN d[338]
    DIRECTION INPUT ;
    USE SIGNAL ;
    PORT
      LAYER M4 ;
        RECT  0 56.448 0.084 56.472 ;
    END
  END d[338]
  PIN d[339]
    DIRECTION INPUT ;
    USE SIGNAL ;
    PORT
      LAYER M4 ;
        RECT  0 56.592 0.084 56.616 ;
    END
  END d[339]
  PIN d[33]
    DIRECTION INPUT ;
    USE SIGNAL ;
    PORT
      LAYER M4 ;
        RECT  0 12.096 0.084 12.12 ;
    END
  END d[33]
  PIN d[340]
    DIRECTION INPUT ;
    USE SIGNAL ;
    PORT
      LAYER M4 ;
        RECT  0 56.736 0.084 56.76 ;
    END
  END d[340]
  PIN d[341]
    DIRECTION INPUT ;
    USE SIGNAL ;
    PORT
      LAYER M4 ;
        RECT  0 56.88 0.084 56.904 ;
    END
  END d[341]
  PIN d[342]
    DIRECTION INPUT ;
    USE SIGNAL ;
    PORT
      LAYER M4 ;
        RECT  0 57.024 0.084 57.048 ;
    END
  END d[342]
  PIN d[343]
    DIRECTION INPUT ;
    USE SIGNAL ;
    PORT
      LAYER M4 ;
        RECT  0 57.168 0.084 57.192 ;
    END
  END d[343]
  PIN d[344]
    DIRECTION INPUT ;
    USE SIGNAL ;
    PORT
      LAYER M4 ;
        RECT  0 57.312 0.084 57.336 ;
    END
  END d[344]
  PIN d[345]
    DIRECTION INPUT ;
    USE SIGNAL ;
    PORT
      LAYER M4 ;
        RECT  0 57.456 0.084 57.48 ;
    END
  END d[345]
  PIN d[346]
    DIRECTION INPUT ;
    USE SIGNAL ;
    PORT
      LAYER M4 ;
        RECT  0 57.6 0.084 57.624 ;
    END
  END d[346]
  PIN d[347]
    DIRECTION INPUT ;
    USE SIGNAL ;
    PORT
      LAYER M4 ;
        RECT  0 57.744 0.084 57.768 ;
    END
  END d[347]
  PIN d[348]
    DIRECTION INPUT ;
    USE SIGNAL ;
    PORT
      LAYER M4 ;
        RECT  0 57.888 0.084 57.912 ;
    END
  END d[348]
  PIN d[349]
    DIRECTION INPUT ;
    USE SIGNAL ;
    PORT
      LAYER M4 ;
        RECT  0 58.032 0.084 58.056 ;
    END
  END d[349]
  PIN d[34]
    DIRECTION INPUT ;
    USE SIGNAL ;
    PORT
      LAYER M4 ;
        RECT  0 12.528 0.084 12.552 ;
    END
  END d[34]
  PIN d[350]
    DIRECTION INPUT ;
    USE SIGNAL ;
    PORT
      LAYER M4 ;
        RECT  0 58.176 0.084 58.2 ;
    END
  END d[350]
  PIN d[351]
    DIRECTION INPUT ;
    USE SIGNAL ;
    PORT
      LAYER M4 ;
        RECT  0 58.32 0.084 58.344 ;
    END
  END d[351]
  PIN d[352]
    DIRECTION INPUT ;
    USE SIGNAL ;
    PORT
      LAYER M4 ;
        RECT  0 58.464 0.084 58.488 ;
    END
  END d[352]
  PIN d[353]
    DIRECTION INPUT ;
    USE SIGNAL ;
    PORT
      LAYER M4 ;
        RECT  0 58.608 0.084 58.632 ;
    END
  END d[353]
  PIN d[354]
    DIRECTION INPUT ;
    USE SIGNAL ;
    PORT
      LAYER M4 ;
        RECT  0 58.752 0.084 58.776 ;
    END
  END d[354]
  PIN d[355]
    DIRECTION INPUT ;
    USE SIGNAL ;
    PORT
      LAYER M4 ;
        RECT  0 59.184 0.084 59.208 ;
    END
  END d[355]
  PIN d[356]
    DIRECTION INPUT ;
    USE SIGNAL ;
    PORT
      LAYER M4 ;
        RECT  0 58.896 0.084 58.92 ;
    END
  END d[356]
  PIN d[357]
    DIRECTION INPUT ;
    USE SIGNAL ;
    PORT
      LAYER M4 ;
        RECT  0 59.328 0.084 59.352 ;
    END
  END d[357]
  PIN d[358]
    DIRECTION INPUT ;
    USE SIGNAL ;
    PORT
      LAYER M4 ;
        RECT  0 59.04 0.084 59.064 ;
    END
  END d[358]
  PIN d[359]
    DIRECTION INPUT ;
    USE SIGNAL ;
    PORT
      LAYER M4 ;
        RECT  0 59.472 0.084 59.496 ;
    END
  END d[359]
  PIN d[35]
    DIRECTION INPUT ;
    USE SIGNAL ;
    PORT
      LAYER M4 ;
        RECT  0 12.24 0.084 12.264 ;
    END
  END d[35]
  PIN d[360]
    DIRECTION INPUT ;
    USE SIGNAL ;
    PORT
      LAYER M4 ;
        RECT  0 59.616 0.084 59.64 ;
    END
  END d[360]
  PIN d[361]
    DIRECTION INPUT ;
    USE SIGNAL ;
    PORT
      LAYER M4 ;
        RECT  0 59.76 0.084 59.784 ;
    END
  END d[361]
  PIN d[362]
    DIRECTION INPUT ;
    USE SIGNAL ;
    PORT
      LAYER M4 ;
        RECT  0 59.904 0.084 59.928 ;
    END
  END d[362]
  PIN d[363]
    DIRECTION INPUT ;
    USE SIGNAL ;
    PORT
      LAYER M4 ;
        RECT  0 60.048 0.084 60.072 ;
    END
  END d[363]
  PIN d[364]
    DIRECTION INPUT ;
    USE SIGNAL ;
    PORT
      LAYER M4 ;
        RECT  0 60.192 0.084 60.216 ;
    END
  END d[364]
  PIN d[365]
    DIRECTION INPUT ;
    USE SIGNAL ;
    PORT
      LAYER M4 ;
        RECT  0 60.336 0.084 60.36 ;
    END
  END d[365]
  PIN d[366]
    DIRECTION INPUT ;
    USE SIGNAL ;
    PORT
      LAYER M4 ;
        RECT  0 60.48 0.084 60.504 ;
    END
  END d[366]
  PIN d[367]
    DIRECTION INPUT ;
    USE SIGNAL ;
    PORT
      LAYER M4 ;
        RECT  0 60.624 0.084 60.648 ;
    END
  END d[367]
  PIN d[368]
    DIRECTION INPUT ;
    USE SIGNAL ;
    PORT
      LAYER M4 ;
        RECT  0 60.768 0.084 60.792 ;
    END
  END d[368]
  PIN d[369]
    DIRECTION INPUT ;
    USE SIGNAL ;
    PORT
      LAYER M4 ;
        RECT  0 60.912 0.084 60.936 ;
    END
  END d[369]
  PIN d[36]
    DIRECTION INPUT ;
    USE SIGNAL ;
    PORT
      LAYER M4 ;
        RECT  0 12.816 0.084 12.84 ;
    END
  END d[36]
  PIN d[370]
    DIRECTION INPUT ;
    USE SIGNAL ;
    PORT
      LAYER M4 ;
        RECT  0 61.056 0.084 61.08 ;
    END
  END d[370]
  PIN d[371]
    DIRECTION INPUT ;
    USE SIGNAL ;
    PORT
      LAYER M4 ;
        RECT  0 61.2 0.084 61.224 ;
    END
  END d[371]
  PIN d[372]
    DIRECTION INPUT ;
    USE SIGNAL ;
    PORT
      LAYER M4 ;
        RECT  0 61.344 0.084 61.368 ;
    END
  END d[372]
  PIN d[373]
    DIRECTION INPUT ;
    USE SIGNAL ;
    PORT
      LAYER M4 ;
        RECT  0 61.488 0.084 61.512 ;
    END
  END d[373]
  PIN d[374]
    DIRECTION INPUT ;
    USE SIGNAL ;
    PORT
      LAYER M4 ;
        RECT  0 61.632 0.084 61.656 ;
    END
  END d[374]
  PIN d[375]
    DIRECTION INPUT ;
    USE SIGNAL ;
    PORT
      LAYER M4 ;
        RECT  0 61.776 0.084 61.8 ;
    END
  END d[375]
  PIN d[376]
    DIRECTION INPUT ;
    USE SIGNAL ;
    PORT
      LAYER M4 ;
        RECT  0 61.92 0.084 61.944 ;
    END
  END d[376]
  PIN d[377]
    DIRECTION INPUT ;
    USE SIGNAL ;
    PORT
      LAYER M4 ;
        RECT  0 62.064 0.084 62.088 ;
    END
  END d[377]
  PIN d[378]
    DIRECTION INPUT ;
    USE SIGNAL ;
    PORT
      LAYER M4 ;
        RECT  0 62.208 0.084 62.232 ;
    END
  END d[378]
  PIN d[379]
    DIRECTION INPUT ;
    USE SIGNAL ;
    PORT
      LAYER M4 ;
        RECT  0 62.352 0.084 62.376 ;
    END
  END d[379]
  PIN d[37]
    DIRECTION INPUT ;
    USE SIGNAL ;
    PORT
      LAYER M4 ;
        RECT  0 12.672 0.084 12.696 ;
    END
  END d[37]
  PIN d[380]
    DIRECTION INPUT ;
    USE SIGNAL ;
    PORT
      LAYER M4 ;
        RECT  0 62.496 0.084 62.52 ;
    END
  END d[380]
  PIN d[381]
    DIRECTION INPUT ;
    USE SIGNAL ;
    PORT
      LAYER M4 ;
        RECT  0 62.928 0.084 62.952 ;
    END
  END d[381]
  PIN d[382]
    DIRECTION INPUT ;
    USE SIGNAL ;
    PORT
      LAYER M4 ;
        RECT  0 62.64 0.084 62.664 ;
    END
  END d[382]
  PIN d[383]
    DIRECTION INPUT ;
    USE SIGNAL ;
    PORT
      LAYER M4 ;
        RECT  0 63.072 0.084 63.096 ;
    END
  END d[383]
  PIN d[384]
    DIRECTION INPUT ;
    USE SIGNAL ;
    PORT
      LAYER M4 ;
        RECT  0 62.784 0.084 62.808 ;
    END
  END d[384]
  PIN d[385]
    DIRECTION INPUT ;
    USE SIGNAL ;
    PORT
      LAYER M4 ;
        RECT  0 63.216 0.084 63.24 ;
    END
  END d[385]
  PIN d[386]
    DIRECTION INPUT ;
    USE SIGNAL ;
    PORT
      LAYER M4 ;
        RECT  0 63.36 0.084 63.384 ;
    END
  END d[386]
  PIN d[387]
    DIRECTION INPUT ;
    USE SIGNAL ;
    PORT
      LAYER M4 ;
        RECT  0 63.504 0.084 63.528 ;
    END
  END d[387]
  PIN d[388]
    DIRECTION INPUT ;
    USE SIGNAL ;
    PORT
      LAYER M4 ;
        RECT  0 63.648 0.084 63.672 ;
    END
  END d[388]
  PIN d[389]
    DIRECTION INPUT ;
    USE SIGNAL ;
    PORT
      LAYER M4 ;
        RECT  0 63.792 0.084 63.816 ;
    END
  END d[389]
  PIN d[38]
    DIRECTION INPUT ;
    USE SIGNAL ;
    PORT
      LAYER M4 ;
        RECT  0 12.96 0.084 12.984 ;
    END
  END d[38]
  PIN d[390]
    DIRECTION INPUT ;
    USE SIGNAL ;
    PORT
      LAYER M4 ;
        RECT  0 63.936 0.084 63.96 ;
    END
  END d[390]
  PIN d[391]
    DIRECTION INPUT ;
    USE SIGNAL ;
    PORT
      LAYER M4 ;
        RECT  0 64.08 0.084 64.104 ;
    END
  END d[391]
  PIN d[392]
    DIRECTION INPUT ;
    USE SIGNAL ;
    PORT
      LAYER M4 ;
        RECT  0 64.224 0.084 64.248 ;
    END
  END d[392]
  PIN d[393]
    DIRECTION INPUT ;
    USE SIGNAL ;
    PORT
      LAYER M4 ;
        RECT  0 64.368 0.084 64.392 ;
    END
  END d[393]
  PIN d[394]
    DIRECTION INPUT ;
    USE SIGNAL ;
    PORT
      LAYER M4 ;
        RECT  0 64.512 0.084 64.536 ;
    END
  END d[394]
  PIN d[395]
    DIRECTION INPUT ;
    USE SIGNAL ;
    PORT
      LAYER M4 ;
        RECT  0 64.656 0.084 64.68 ;
    END
  END d[395]
  PIN d[396]
    DIRECTION INPUT ;
    USE SIGNAL ;
    PORT
      LAYER M4 ;
        RECT  0 64.8 0.084 64.824 ;
    END
  END d[396]
  PIN d[397]
    DIRECTION INPUT ;
    USE SIGNAL ;
    PORT
      LAYER M4 ;
        RECT  0 64.944 0.084 64.968 ;
    END
  END d[397]
  PIN d[398]
    DIRECTION INPUT ;
    USE SIGNAL ;
    PORT
      LAYER M4 ;
        RECT  0 65.088 0.084 65.112 ;
    END
  END d[398]
  PIN d[399]
    DIRECTION INPUT ;
    USE SIGNAL ;
    PORT
      LAYER M4 ;
        RECT  0 65.232 0.084 65.256 ;
    END
  END d[399]
  PIN d[39]
    DIRECTION INPUT ;
    USE SIGNAL ;
    PORT
      LAYER M4 ;
        RECT  0 13.104 0.084 13.128 ;
    END
  END d[39]
  PIN d[3]
    DIRECTION INPUT ;
    USE SIGNAL ;
    PORT
      LAYER M4 ;
        RECT  0 7.776 0.084 7.8 ;
    END
  END d[3]
  PIN d[400]
    DIRECTION INPUT ;
    USE SIGNAL ;
    PORT
      LAYER M4 ;
        RECT  0 65.376 0.084 65.4 ;
    END
  END d[400]
  PIN d[401]
    DIRECTION INPUT ;
    USE SIGNAL ;
    PORT
      LAYER M4 ;
        RECT  0 65.52 0.084 65.544 ;
    END
  END d[401]
  PIN d[402]
    DIRECTION INPUT ;
    USE SIGNAL ;
    PORT
      LAYER M4 ;
        RECT  0 65.664 0.084 65.688 ;
    END
  END d[402]
  PIN d[403]
    DIRECTION INPUT ;
    USE SIGNAL ;
    PORT
      LAYER M4 ;
        RECT  0 65.808 0.084 65.832 ;
    END
  END d[403]
  PIN d[404]
    DIRECTION INPUT ;
    USE SIGNAL ;
    PORT
      LAYER M4 ;
        RECT  0 65.952 0.084 65.976 ;
    END
  END d[404]
  PIN d[405]
    DIRECTION INPUT ;
    USE SIGNAL ;
    PORT
      LAYER M4 ;
        RECT  0 66.384 0.084 66.408 ;
    END
  END d[405]
  PIN d[406]
    DIRECTION INPUT ;
    USE SIGNAL ;
    PORT
      LAYER M4 ;
        RECT  0 66.096 0.084 66.12 ;
    END
  END d[406]
  PIN d[407]
    DIRECTION INPUT ;
    USE SIGNAL ;
    PORT
      LAYER M4 ;
        RECT  0 66.528 0.084 66.552 ;
    END
  END d[407]
  PIN d[408]
    DIRECTION INPUT ;
    USE SIGNAL ;
    PORT
      LAYER M4 ;
        RECT  0 66.24 0.084 66.264 ;
    END
  END d[408]
  PIN d[409]
    DIRECTION INPUT ;
    USE SIGNAL ;
    PORT
      LAYER M4 ;
        RECT  0 66.672 0.084 66.696 ;
    END
  END d[409]
  PIN d[40]
    DIRECTION INPUT ;
    USE SIGNAL ;
    PORT
      LAYER M4 ;
        RECT  0 13.392 0.084 13.416 ;
    END
  END d[40]
  PIN d[410]
    DIRECTION INPUT ;
    USE SIGNAL ;
    PORT
      LAYER M4 ;
        RECT  0 66.816 0.084 66.84 ;
    END
  END d[410]
  PIN d[411]
    DIRECTION INPUT ;
    USE SIGNAL ;
    PORT
      LAYER M4 ;
        RECT  0 66.96 0.084 66.984 ;
    END
  END d[411]
  PIN d[412]
    DIRECTION INPUT ;
    USE SIGNAL ;
    PORT
      LAYER M4 ;
        RECT  0 67.104 0.084 67.128 ;
    END
  END d[412]
  PIN d[413]
    DIRECTION INPUT ;
    USE SIGNAL ;
    PORT
      LAYER M4 ;
        RECT  0 67.248 0.084 67.272 ;
    END
  END d[413]
  PIN d[414]
    DIRECTION INPUT ;
    USE SIGNAL ;
    PORT
      LAYER M4 ;
        RECT  0 67.392 0.084 67.416 ;
    END
  END d[414]
  PIN d[415]
    DIRECTION INPUT ;
    USE SIGNAL ;
    PORT
      LAYER M4 ;
        RECT  0 67.536 0.084 67.56 ;
    END
  END d[415]
  PIN d[416]
    DIRECTION INPUT ;
    USE SIGNAL ;
    PORT
      LAYER M4 ;
        RECT  0 67.68 0.084 67.704 ;
    END
  END d[416]
  PIN d[417]
    DIRECTION INPUT ;
    USE SIGNAL ;
    PORT
      LAYER M4 ;
        RECT  0 67.824 0.084 67.848 ;
    END
  END d[417]
  PIN d[418]
    DIRECTION INPUT ;
    USE SIGNAL ;
    PORT
      LAYER M4 ;
        RECT  0 67.968 0.084 67.992 ;
    END
  END d[418]
  PIN d[419]
    DIRECTION INPUT ;
    USE SIGNAL ;
    PORT
      LAYER M4 ;
        RECT  0 68.112 0.084 68.136 ;
    END
  END d[419]
  PIN d[41]
    DIRECTION INPUT ;
    USE SIGNAL ;
    PORT
      LAYER M4 ;
        RECT  0 13.248 0.084 13.272 ;
    END
  END d[41]
  PIN d[420]
    DIRECTION INPUT ;
    USE SIGNAL ;
    PORT
      LAYER M4 ;
        RECT  0 68.256 0.084 68.28 ;
    END
  END d[420]
  PIN d[421]
    DIRECTION INPUT ;
    USE SIGNAL ;
    PORT
      LAYER M4 ;
        RECT  0 68.4 0.084 68.424 ;
    END
  END d[421]
  PIN d[422]
    DIRECTION INPUT ;
    USE SIGNAL ;
    PORT
      LAYER M4 ;
        RECT  0 68.544 0.084 68.568 ;
    END
  END d[422]
  PIN d[423]
    DIRECTION INPUT ;
    USE SIGNAL ;
    PORT
      LAYER M4 ;
        RECT  0 68.688 0.084 68.712 ;
    END
  END d[423]
  PIN d[424]
    DIRECTION INPUT ;
    USE SIGNAL ;
    PORT
      LAYER M4 ;
        RECT  0 68.832 0.084 68.856 ;
    END
  END d[424]
  PIN d[425]
    DIRECTION INPUT ;
    USE SIGNAL ;
    PORT
      LAYER M4 ;
        RECT  0 68.976 0.084 69 ;
    END
  END d[425]
  PIN d[426]
    DIRECTION INPUT ;
    USE SIGNAL ;
    PORT
      LAYER M4 ;
        RECT  0 69.12 0.084 69.144 ;
    END
  END d[426]
  PIN d[427]
    DIRECTION INPUT ;
    USE SIGNAL ;
    PORT
      LAYER M4 ;
        RECT  0 69.264 0.084 69.288 ;
    END
  END d[427]
  PIN d[428]
    DIRECTION INPUT ;
    USE SIGNAL ;
    PORT
      LAYER M4 ;
        RECT  0 69.408 0.084 69.432 ;
    END
  END d[428]
  PIN d[429]
    DIRECTION INPUT ;
    USE SIGNAL ;
    PORT
      LAYER M4 ;
        RECT  0 69.696 0.084 69.72 ;
    END
  END d[429]
  PIN d[42]
    DIRECTION INPUT ;
    USE SIGNAL ;
    PORT
      LAYER M4 ;
        RECT  0 13.536 0.084 13.56 ;
    END
  END d[42]
  PIN d[430]
    DIRECTION INPUT ;
    USE SIGNAL ;
    PORT
      LAYER M4 ;
        RECT  0 69.552 0.084 69.576 ;
    END
  END d[430]
  PIN d[431]
    DIRECTION INPUT ;
    USE SIGNAL ;
    PORT
      LAYER M4 ;
        RECT  0 70.128 0.084 70.152 ;
    END
  END d[431]
  PIN d[432]
    DIRECTION INPUT ;
    USE SIGNAL ;
    PORT
      LAYER M4 ;
        RECT  0 69.84 0.084 69.864 ;
    END
  END d[432]
  PIN d[433]
    DIRECTION INPUT ;
    USE SIGNAL ;
    PORT
      LAYER M4 ;
        RECT  0 70.272 0.084 70.296 ;
    END
  END d[433]
  PIN d[434]
    DIRECTION INPUT ;
    USE SIGNAL ;
    PORT
      LAYER M4 ;
        RECT  0 69.984 0.084 70.008 ;
    END
  END d[434]
  PIN d[435]
    DIRECTION INPUT ;
    USE SIGNAL ;
    PORT
      LAYER M4 ;
        RECT  0 70.416 0.084 70.44 ;
    END
  END d[435]
  PIN d[436]
    DIRECTION INPUT ;
    USE SIGNAL ;
    PORT
      LAYER M4 ;
        RECT  0 70.56 0.084 70.584 ;
    END
  END d[436]
  PIN d[437]
    DIRECTION INPUT ;
    USE SIGNAL ;
    PORT
      LAYER M4 ;
        RECT  0 70.704 0.084 70.728 ;
    END
  END d[437]
  PIN d[438]
    DIRECTION INPUT ;
    USE SIGNAL ;
    PORT
      LAYER M4 ;
        RECT  0 70.848 0.084 70.872 ;
    END
  END d[438]
  PIN d[439]
    DIRECTION INPUT ;
    USE SIGNAL ;
    PORT
      LAYER M4 ;
        RECT  0 70.992 0.084 71.016 ;
    END
  END d[439]
  PIN d[43]
    DIRECTION INPUT ;
    USE SIGNAL ;
    PORT
      LAYER M4 ;
        RECT  0 13.68 0.084 13.704 ;
    END
  END d[43]
  PIN d[440]
    DIRECTION INPUT ;
    USE SIGNAL ;
    PORT
      LAYER M4 ;
        RECT  0 71.136 0.084 71.16 ;
    END
  END d[440]
  PIN d[441]
    DIRECTION INPUT ;
    USE SIGNAL ;
    PORT
      LAYER M4 ;
        RECT  0 71.28 0.084 71.304 ;
    END
  END d[441]
  PIN d[442]
    DIRECTION INPUT ;
    USE SIGNAL ;
    PORT
      LAYER M4 ;
        RECT  0 71.424 0.084 71.448 ;
    END
  END d[442]
  PIN d[443]
    DIRECTION INPUT ;
    USE SIGNAL ;
    PORT
      LAYER M4 ;
        RECT  0 71.568 0.084 71.592 ;
    END
  END d[443]
  PIN d[444]
    DIRECTION INPUT ;
    USE SIGNAL ;
    PORT
      LAYER M4 ;
        RECT  0 71.712 0.084 71.736 ;
    END
  END d[444]
  PIN d[445]
    DIRECTION INPUT ;
    USE SIGNAL ;
    PORT
      LAYER M4 ;
        RECT  0 71.856 0.084 71.88 ;
    END
  END d[445]
  PIN d[446]
    DIRECTION INPUT ;
    USE SIGNAL ;
    PORT
      LAYER M4 ;
        RECT  0 72 0.084 72.024 ;
    END
  END d[446]
  PIN d[447]
    DIRECTION INPUT ;
    USE SIGNAL ;
    PORT
      LAYER M4 ;
        RECT  0 72.144 0.084 72.168 ;
    END
  END d[447]
  PIN d[448]
    DIRECTION INPUT ;
    USE SIGNAL ;
    PORT
      LAYER M4 ;
        RECT  0 72.288 0.084 72.312 ;
    END
  END d[448]
  PIN d[449]
    DIRECTION INPUT ;
    USE SIGNAL ;
    PORT
      LAYER M4 ;
        RECT  0 72.432 0.084 72.456 ;
    END
  END d[449]
  PIN d[44]
    DIRECTION INPUT ;
    USE SIGNAL ;
    PORT
      LAYER M4 ;
        RECT  0 13.824 0.084 13.848 ;
    END
  END d[44]
  PIN d[450]
    DIRECTION INPUT ;
    USE SIGNAL ;
    PORT
      LAYER M4 ;
        RECT  0 72.576 0.084 72.6 ;
    END
  END d[450]
  PIN d[451]
    DIRECTION INPUT ;
    USE SIGNAL ;
    PORT
      LAYER M4 ;
        RECT  0 72.72 0.084 72.744 ;
    END
  END d[451]
  PIN d[452]
    DIRECTION INPUT ;
    USE SIGNAL ;
    PORT
      LAYER M4 ;
        RECT  0 72.864 0.084 72.888 ;
    END
  END d[452]
  PIN d[453]
    DIRECTION INPUT ;
    USE SIGNAL ;
    PORT
      LAYER M4 ;
        RECT  0 73.008 0.084 73.032 ;
    END
  END d[453]
  PIN d[454]
    DIRECTION INPUT ;
    USE SIGNAL ;
    PORT
      LAYER M4 ;
        RECT  0 73.152 0.084 73.176 ;
    END
  END d[454]
  PIN d[455]
    DIRECTION INPUT ;
    USE SIGNAL ;
    PORT
      LAYER M4 ;
        RECT  0 73.584 0.084 73.608 ;
    END
  END d[455]
  PIN d[456]
    DIRECTION INPUT ;
    USE SIGNAL ;
    PORT
      LAYER M4 ;
        RECT  0 73.296 0.084 73.32 ;
    END
  END d[456]
  PIN d[457]
    DIRECTION INPUT ;
    USE SIGNAL ;
    PORT
      LAYER M4 ;
        RECT  0 73.728 0.084 73.752 ;
    END
  END d[457]
  PIN d[458]
    DIRECTION INPUT ;
    USE SIGNAL ;
    PORT
      LAYER M4 ;
        RECT  0 73.44 0.084 73.464 ;
    END
  END d[458]
  PIN d[459]
    DIRECTION INPUT ;
    USE SIGNAL ;
    PORT
      LAYER M4 ;
        RECT  0 73.872 0.084 73.896 ;
    END
  END d[459]
  PIN d[45]
    DIRECTION INPUT ;
    USE SIGNAL ;
    PORT
      LAYER M4 ;
        RECT  0 13.968 0.084 13.992 ;
    END
  END d[45]
  PIN d[460]
    DIRECTION INPUT ;
    USE SIGNAL ;
    PORT
      LAYER M4 ;
        RECT  0 74.016 0.084 74.04 ;
    END
  END d[460]
  PIN d[461]
    DIRECTION INPUT ;
    USE SIGNAL ;
    PORT
      LAYER M4 ;
        RECT  0 74.16 0.084 74.184 ;
    END
  END d[461]
  PIN d[462]
    DIRECTION INPUT ;
    USE SIGNAL ;
    PORT
      LAYER M4 ;
        RECT  0 74.304 0.084 74.328 ;
    END
  END d[462]
  PIN d[463]
    DIRECTION INPUT ;
    USE SIGNAL ;
    PORT
      LAYER M4 ;
        RECT  0 74.448 0.084 74.472 ;
    END
  END d[463]
  PIN d[464]
    DIRECTION INPUT ;
    USE SIGNAL ;
    PORT
      LAYER M4 ;
        RECT  0 74.592 0.084 74.616 ;
    END
  END d[464]
  PIN d[465]
    DIRECTION INPUT ;
    USE SIGNAL ;
    PORT
      LAYER M4 ;
        RECT  0 74.736 0.084 74.76 ;
    END
  END d[465]
  PIN d[466]
    DIRECTION INPUT ;
    USE SIGNAL ;
    PORT
      LAYER M4 ;
        RECT  0 74.88 0.084 74.904 ;
    END
  END d[466]
  PIN d[467]
    DIRECTION INPUT ;
    USE SIGNAL ;
    PORT
      LAYER M4 ;
        RECT  0 75.024 0.084 75.048 ;
    END
  END d[467]
  PIN d[468]
    DIRECTION INPUT ;
    USE SIGNAL ;
    PORT
      LAYER M4 ;
        RECT  0 75.168 0.084 75.192 ;
    END
  END d[468]
  PIN d[469]
    DIRECTION INPUT ;
    USE SIGNAL ;
    PORT
      LAYER M4 ;
        RECT  0 75.312 0.084 75.336 ;
    END
  END d[469]
  PIN d[46]
    DIRECTION INPUT ;
    USE SIGNAL ;
    PORT
      LAYER M4 ;
        RECT  0 14.112 0.084 14.136 ;
    END
  END d[46]
  PIN d[470]
    DIRECTION INPUT ;
    USE SIGNAL ;
    PORT
      LAYER M4 ;
        RECT  0 75.456 0.084 75.48 ;
    END
  END d[470]
  PIN d[471]
    DIRECTION INPUT ;
    USE SIGNAL ;
    PORT
      LAYER M4 ;
        RECT  0 75.6 0.084 75.624 ;
    END
  END d[471]
  PIN d[472]
    DIRECTION INPUT ;
    USE SIGNAL ;
    PORT
      LAYER M4 ;
        RECT  0 75.744 0.084 75.768 ;
    END
  END d[472]
  PIN d[473]
    DIRECTION INPUT ;
    USE SIGNAL ;
    PORT
      LAYER M4 ;
        RECT  0 75.888 0.084 75.912 ;
    END
  END d[473]
  PIN d[474]
    DIRECTION INPUT ;
    USE SIGNAL ;
    PORT
      LAYER M4 ;
        RECT  0 76.032 0.084 76.056 ;
    END
  END d[474]
  PIN d[475]
    DIRECTION INPUT ;
    USE SIGNAL ;
    PORT
      LAYER M4 ;
        RECT  0 76.176 0.084 76.2 ;
    END
  END d[475]
  PIN d[476]
    DIRECTION INPUT ;
    USE SIGNAL ;
    PORT
      LAYER M4 ;
        RECT  0 76.32 0.084 76.344 ;
    END
  END d[476]
  PIN d[477]
    DIRECTION INPUT ;
    USE SIGNAL ;
    PORT
      LAYER M4 ;
        RECT  0 76.464 0.084 76.488 ;
    END
  END d[477]
  PIN d[478]
    DIRECTION INPUT ;
    USE SIGNAL ;
    PORT
      LAYER M4 ;
        RECT  0 76.608 0.084 76.632 ;
    END
  END d[478]
  PIN d[479]
    DIRECTION INPUT ;
    USE SIGNAL ;
    PORT
      LAYER M4 ;
        RECT  0 76.896 0.084 76.92 ;
    END
  END d[479]
  PIN d[47]
    DIRECTION INPUT ;
    USE SIGNAL ;
    PORT
      LAYER M4 ;
        RECT  0 14.256 0.084 14.28 ;
    END
  END d[47]
  PIN d[480]
    DIRECTION INPUT ;
    USE SIGNAL ;
    PORT
      LAYER M4 ;
        RECT  0 76.752 0.084 76.776 ;
    END
  END d[480]
  PIN d[481]
    DIRECTION INPUT ;
    USE SIGNAL ;
    PORT
      LAYER M4 ;
        RECT  0 77.328 0.084 77.352 ;
    END
  END d[481]
  PIN d[482]
    DIRECTION INPUT ;
    USE SIGNAL ;
    PORT
      LAYER M4 ;
        RECT  0 77.04 0.084 77.064 ;
    END
  END d[482]
  PIN d[483]
    DIRECTION INPUT ;
    USE SIGNAL ;
    PORT
      LAYER M4 ;
        RECT  0 77.472 0.084 77.496 ;
    END
  END d[483]
  PIN d[484]
    DIRECTION INPUT ;
    USE SIGNAL ;
    PORT
      LAYER M4 ;
        RECT  0 77.184 0.084 77.208 ;
    END
  END d[484]
  PIN d[485]
    DIRECTION INPUT ;
    USE SIGNAL ;
    PORT
      LAYER M4 ;
        RECT  0 77.616 0.084 77.64 ;
    END
  END d[485]
  PIN d[486]
    DIRECTION INPUT ;
    USE SIGNAL ;
    PORT
      LAYER M4 ;
        RECT  0 77.76 0.084 77.784 ;
    END
  END d[486]
  PIN d[487]
    DIRECTION INPUT ;
    USE SIGNAL ;
    PORT
      LAYER M4 ;
        RECT  0 77.904 0.084 77.928 ;
    END
  END d[487]
  PIN d[488]
    DIRECTION INPUT ;
    USE SIGNAL ;
    PORT
      LAYER M4 ;
        RECT  0 78.048 0.084 78.072 ;
    END
  END d[488]
  PIN d[489]
    DIRECTION INPUT ;
    USE SIGNAL ;
    PORT
      LAYER M4 ;
        RECT  0 78.336 0.084 78.36 ;
    END
  END d[489]
  PIN d[48]
    DIRECTION INPUT ;
    USE SIGNAL ;
    PORT
      LAYER M4 ;
        RECT  0 14.4 0.084 14.424 ;
    END
  END d[48]
  PIN d[490]
    DIRECTION INPUT ;
    USE SIGNAL ;
    PORT
      LAYER M4 ;
        RECT  0 78.192 0.084 78.216 ;
    END
  END d[490]
  PIN d[491]
    DIRECTION INPUT ;
    USE SIGNAL ;
    PORT
      LAYER M4 ;
        RECT  0 78.48 0.084 78.504 ;
    END
  END d[491]
  PIN d[492]
    DIRECTION INPUT ;
    USE SIGNAL ;
    PORT
      LAYER M4 ;
        RECT  0 78.624 0.084 78.648 ;
    END
  END d[492]
  PIN d[493]
    DIRECTION INPUT ;
    USE SIGNAL ;
    PORT
      LAYER M4 ;
        RECT  0 78.768 0.084 78.792 ;
    END
  END d[493]
  PIN d[494]
    DIRECTION INPUT ;
    USE SIGNAL ;
    PORT
      LAYER M4 ;
        RECT  0 78.912 0.084 78.936 ;
    END
  END d[494]
  PIN d[495]
    DIRECTION INPUT ;
    USE SIGNAL ;
    PORT
      LAYER M4 ;
        RECT  0 79.056 0.084 79.08 ;
    END
  END d[495]
  PIN d[496]
    DIRECTION INPUT ;
    USE SIGNAL ;
    PORT
      LAYER M4 ;
        RECT  0 79.2 0.084 79.224 ;
    END
  END d[496]
  PIN d[497]
    DIRECTION INPUT ;
    USE SIGNAL ;
    PORT
      LAYER M4 ;
        RECT  0 79.344 0.084 79.368 ;
    END
  END d[497]
  PIN d[498]
    DIRECTION INPUT ;
    USE SIGNAL ;
    PORT
      LAYER M4 ;
        RECT  0 79.488 0.084 79.512 ;
    END
  END d[498]
  PIN d[499]
    DIRECTION INPUT ;
    USE SIGNAL ;
    PORT
      LAYER M4 ;
        RECT  0 79.776 0.084 79.8 ;
    END
  END d[499]
  PIN d[49]
    DIRECTION INPUT ;
    USE SIGNAL ;
    PORT
      LAYER M4 ;
        RECT  0 14.544 0.084 14.568 ;
    END
  END d[49]
  PIN d[4]
    DIRECTION INPUT ;
    USE SIGNAL ;
    PORT
      LAYER M4 ;
        RECT  0 8.064 0.084 8.088 ;
    END
  END d[4]
  PIN d[500]
    DIRECTION INPUT ;
    USE SIGNAL ;
    PORT
      LAYER M4 ;
        RECT  0 79.632 0.084 79.656 ;
    END
  END d[500]
  PIN d[501]
    DIRECTION INPUT ;
    USE SIGNAL ;
    PORT
      LAYER M4 ;
        RECT  0 79.92 0.084 79.944 ;
    END
  END d[501]
  PIN d[502]
    DIRECTION INPUT ;
    USE SIGNAL ;
    PORT
      LAYER M4 ;
        RECT  0 80.064 0.084 80.088 ;
    END
  END d[502]
  PIN d[503]
    DIRECTION INPUT ;
    USE SIGNAL ;
    PORT
      LAYER M4 ;
        RECT  0 80.208 0.084 80.232 ;
    END
  END d[503]
  PIN d[504]
    DIRECTION INPUT ;
    USE SIGNAL ;
    PORT
      LAYER M4 ;
        RECT  0 80.352 0.084 80.376 ;
    END
  END d[504]
  PIN d[505]
    DIRECTION INPUT ;
    USE SIGNAL ;
    PORT
      LAYER M4 ;
        RECT  0 80.784 0.084 80.808 ;
    END
  END d[505]
  PIN d[506]
    DIRECTION INPUT ;
    USE SIGNAL ;
    PORT
      LAYER M4 ;
        RECT  0 80.496 0.084 80.52 ;
    END
  END d[506]
  PIN d[507]
    DIRECTION INPUT ;
    USE SIGNAL ;
    PORT
      LAYER M4 ;
        RECT  0 80.928 0.084 80.952 ;
    END
  END d[507]
  PIN d[508]
    DIRECTION INPUT ;
    USE SIGNAL ;
    PORT
      LAYER M4 ;
        RECT  0 80.64 0.084 80.664 ;
    END
  END d[508]
  PIN d[509]
    DIRECTION INPUT ;
    USE SIGNAL ;
    PORT
      LAYER M4 ;
        RECT  0 81.072 0.084 81.096 ;
    END
  END d[509]
  PIN d[50]
    DIRECTION INPUT ;
    USE SIGNAL ;
    PORT
      LAYER M4 ;
        RECT  0 14.688 0.084 14.712 ;
    END
  END d[50]
  PIN d[510]
    DIRECTION INPUT ;
    USE SIGNAL ;
    PORT
      LAYER M4 ;
        RECT  0 81.216 0.084 81.24 ;
    END
  END d[510]
  PIN d[511]
    DIRECTION INPUT ;
    USE SIGNAL ;
    PORT
      LAYER M4 ;
        RECT  0 81.36 0.084 81.384 ;
    END
  END d[511]
  PIN d[512]
    DIRECTION INPUT ;
    USE SIGNAL ;
    PORT
      LAYER M4 ;
        RECT  0 81.504 0.084 81.528 ;
    END
  END d[512]
  PIN d[513]
    DIRECTION INPUT ;
    USE SIGNAL ;
    PORT
      LAYER M4 ;
        RECT  0 81.648 0.084 81.672 ;
    END
  END d[513]
  PIN d[514]
    DIRECTION INPUT ;
    USE SIGNAL ;
    PORT
      LAYER M4 ;
        RECT  0 81.792 0.084 81.816 ;
    END
  END d[514]
  PIN d[515]
    DIRECTION INPUT ;
    USE SIGNAL ;
    PORT
      LAYER M4 ;
        RECT  0 81.936 0.084 81.96 ;
    END
  END d[515]
  PIN d[516]
    DIRECTION INPUT ;
    USE SIGNAL ;
    PORT
      LAYER M4 ;
        RECT  0 82.08 0.084 82.104 ;
    END
  END d[516]
  PIN d[517]
    DIRECTION INPUT ;
    USE SIGNAL ;
    PORT
      LAYER M4 ;
        RECT  0 82.224 0.084 82.248 ;
    END
  END d[517]
  PIN d[518]
    DIRECTION INPUT ;
    USE SIGNAL ;
    PORT
      LAYER M4 ;
        RECT  0 82.368 0.084 82.392 ;
    END
  END d[518]
  PIN d[519]
    DIRECTION INPUT ;
    USE SIGNAL ;
    PORT
      LAYER M4 ;
        RECT  0 82.656 0.084 82.68 ;
    END
  END d[519]
  PIN d[51]
    DIRECTION INPUT ;
    USE SIGNAL ;
    PORT
      LAYER M4 ;
        RECT  0 14.832 0.084 14.856 ;
    END
  END d[51]
  PIN d[520]
    DIRECTION INPUT ;
    USE SIGNAL ;
    PORT
      LAYER M4 ;
        RECT  0 82.512 0.084 82.536 ;
    END
  END d[520]
  PIN d[521]
    DIRECTION INPUT ;
    USE SIGNAL ;
    PORT
      LAYER M4 ;
        RECT  0 82.8 0.084 82.824 ;
    END
  END d[521]
  PIN d[522]
    DIRECTION INPUT ;
    USE SIGNAL ;
    PORT
      LAYER M4 ;
        RECT  0 82.944 0.084 82.968 ;
    END
  END d[522]
  PIN d[523]
    DIRECTION INPUT ;
    USE SIGNAL ;
    PORT
      LAYER M4 ;
        RECT  0 83.088 0.084 83.112 ;
    END
  END d[523]
  PIN d[524]
    DIRECTION INPUT ;
    USE SIGNAL ;
    PORT
      LAYER M4 ;
        RECT  0 83.232 0.084 83.256 ;
    END
  END d[524]
  PIN d[525]
    DIRECTION INPUT ;
    USE SIGNAL ;
    PORT
      LAYER M4 ;
        RECT  0 83.376 0.084 83.4 ;
    END
  END d[525]
  PIN d[526]
    DIRECTION INPUT ;
    USE SIGNAL ;
    PORT
      LAYER M4 ;
        RECT  0 83.52 0.084 83.544 ;
    END
  END d[526]
  PIN d[527]
    DIRECTION INPUT ;
    USE SIGNAL ;
    PORT
      LAYER M4 ;
        RECT  0 83.664 0.084 83.688 ;
    END
  END d[527]
  PIN d[528]
    DIRECTION INPUT ;
    USE SIGNAL ;
    PORT
      LAYER M4 ;
        RECT  0 83.808 0.084 83.832 ;
    END
  END d[528]
  PIN d[529]
    DIRECTION INPUT ;
    USE SIGNAL ;
    PORT
      LAYER M4 ;
        RECT  0 84.24 0.084 84.264 ;
    END
  END d[529]
  PIN d[52]
    DIRECTION INPUT ;
    USE SIGNAL ;
    PORT
      LAYER M4 ;
        RECT  0 14.976 0.084 15 ;
    END
  END d[52]
  PIN d[530]
    DIRECTION INPUT ;
    USE SIGNAL ;
    PORT
      LAYER M4 ;
        RECT  0 83.952 0.084 83.976 ;
    END
  END d[530]
  PIN d[531]
    DIRECTION INPUT ;
    USE SIGNAL ;
    PORT
      LAYER M4 ;
        RECT  0 84.528 0.084 84.552 ;
    END
  END d[531]
  PIN d[532]
    DIRECTION INPUT ;
    USE SIGNAL ;
    PORT
      LAYER M4 ;
        RECT  0 84.096 0.084 84.12 ;
    END
  END d[532]
  PIN d[533]
    DIRECTION INPUT ;
    USE SIGNAL ;
    PORT
      LAYER M4 ;
        RECT  0 84.672 0.084 84.696 ;
    END
  END d[533]
  PIN d[534]
    DIRECTION INPUT ;
    USE SIGNAL ;
    PORT
      LAYER M4 ;
        RECT  0 84.384 0.084 84.408 ;
    END
  END d[534]
  PIN d[535]
    DIRECTION INPUT ;
    USE SIGNAL ;
    PORT
      LAYER M4 ;
        RECT  0 84.816 0.084 84.84 ;
    END
  END d[535]
  PIN d[536]
    DIRECTION INPUT ;
    USE SIGNAL ;
    PORT
      LAYER M4 ;
        RECT  0 84.96 0.084 84.984 ;
    END
  END d[536]
  PIN d[53]
    DIRECTION INPUT ;
    USE SIGNAL ;
    PORT
      LAYER M4 ;
        RECT  0 15.12 0.084 15.144 ;
    END
  END d[53]
  PIN d[54]
    DIRECTION INPUT ;
    USE SIGNAL ;
    PORT
      LAYER M4 ;
        RECT  0 15.264 0.084 15.288 ;
    END
  END d[54]
  PIN d[55]
    DIRECTION INPUT ;
    USE SIGNAL ;
    PORT
      LAYER M4 ;
        RECT  0 15.408 0.084 15.432 ;
    END
  END d[55]
  PIN d[56]
    DIRECTION INPUT ;
    USE SIGNAL ;
    PORT
      LAYER M4 ;
        RECT  0 15.552 0.084 15.576 ;
    END
  END d[56]
  PIN d[57]
    DIRECTION INPUT ;
    USE SIGNAL ;
    PORT
      LAYER M4 ;
        RECT  0 15.696 0.084 15.72 ;
    END
  END d[57]
  PIN d[58]
    DIRECTION INPUT ;
    USE SIGNAL ;
    PORT
      LAYER M4 ;
        RECT  0 16.128 0.084 16.152 ;
    END
  END d[58]
  PIN d[59]
    DIRECTION INPUT ;
    USE SIGNAL ;
    PORT
      LAYER M4 ;
        RECT  0 15.84 0.084 15.864 ;
    END
  END d[59]
  PIN d[5]
    DIRECTION INPUT ;
    USE SIGNAL ;
    PORT
      LAYER M4 ;
        RECT  0 8.208 0.084 8.232 ;
    END
  END d[5]
  PIN d[60]
    DIRECTION INPUT ;
    USE SIGNAL ;
    PORT
      LAYER M4 ;
        RECT  0 16.272 0.084 16.296 ;
    END
  END d[60]
  PIN d[61]
    DIRECTION INPUT ;
    USE SIGNAL ;
    PORT
      LAYER M4 ;
        RECT  0 15.984 0.084 16.008 ;
    END
  END d[61]
  PIN d[62]
    DIRECTION INPUT ;
    USE SIGNAL ;
    PORT
      LAYER M4 ;
        RECT  0 16.416 0.084 16.44 ;
    END
  END d[62]
  PIN d[63]
    DIRECTION INPUT ;
    USE SIGNAL ;
    PORT
      LAYER M4 ;
        RECT  0 16.56 0.084 16.584 ;
    END
  END d[63]
  PIN d[64]
    DIRECTION INPUT ;
    USE SIGNAL ;
    PORT
      LAYER M4 ;
        RECT  0 16.704 0.084 16.728 ;
    END
  END d[64]
  PIN d[65]
    DIRECTION INPUT ;
    USE SIGNAL ;
    PORT
      LAYER M4 ;
        RECT  0 16.848 0.084 16.872 ;
    END
  END d[65]
  PIN d[66]
    DIRECTION INPUT ;
    USE SIGNAL ;
    PORT
      LAYER M4 ;
        RECT  0 16.992 0.084 17.016 ;
    END
  END d[66]
  PIN d[67]
    DIRECTION INPUT ;
    USE SIGNAL ;
    PORT
      LAYER M4 ;
        RECT  0 17.136 0.084 17.16 ;
    END
  END d[67]
  PIN d[68]
    DIRECTION INPUT ;
    USE SIGNAL ;
    PORT
      LAYER M4 ;
        RECT  0 17.28 0.084 17.304 ;
    END
  END d[68]
  PIN d[69]
    DIRECTION INPUT ;
    USE SIGNAL ;
    PORT
      LAYER M4 ;
        RECT  0 17.424 0.084 17.448 ;
    END
  END d[69]
  PIN d[6]
    DIRECTION INPUT ;
    USE SIGNAL ;
    PORT
      LAYER M4 ;
        RECT  0 8.352 0.084 8.376 ;
    END
  END d[6]
  PIN d[70]
    DIRECTION INPUT ;
    USE SIGNAL ;
    PORT
      LAYER M4 ;
        RECT  0 17.568 0.084 17.592 ;
    END
  END d[70]
  PIN d[71]
    DIRECTION INPUT ;
    USE SIGNAL ;
    PORT
      LAYER M4 ;
        RECT  0 17.712 0.084 17.736 ;
    END
  END d[71]
  PIN d[72]
    DIRECTION INPUT ;
    USE SIGNAL ;
    PORT
      LAYER M4 ;
        RECT  0 17.856 0.084 17.88 ;
    END
  END d[72]
  PIN d[73]
    DIRECTION INPUT ;
    USE SIGNAL ;
    PORT
      LAYER M4 ;
        RECT  0 18 0.084 18.024 ;
    END
  END d[73]
  PIN d[74]
    DIRECTION INPUT ;
    USE SIGNAL ;
    PORT
      LAYER M4 ;
        RECT  0 18.144 0.084 18.168 ;
    END
  END d[74]
  PIN d[75]
    DIRECTION INPUT ;
    USE SIGNAL ;
    PORT
      LAYER M4 ;
        RECT  0 18.288 0.084 18.312 ;
    END
  END d[75]
  PIN d[76]
    DIRECTION INPUT ;
    USE SIGNAL ;
    PORT
      LAYER M4 ;
        RECT  0 18.432 0.084 18.456 ;
    END
  END d[76]
  PIN d[77]
    DIRECTION INPUT ;
    USE SIGNAL ;
    PORT
      LAYER M4 ;
        RECT  0 18.576 0.084 18.6 ;
    END
  END d[77]
  PIN d[78]
    DIRECTION INPUT ;
    USE SIGNAL ;
    PORT
      LAYER M4 ;
        RECT  0 18.72 0.084 18.744 ;
    END
  END d[78]
  PIN d[79]
    DIRECTION INPUT ;
    USE SIGNAL ;
    PORT
      LAYER M4 ;
        RECT  0 18.864 0.084 18.888 ;
    END
  END d[79]
  PIN d[7]
    DIRECTION INPUT ;
    USE SIGNAL ;
    PORT
      LAYER M4 ;
        RECT  0 8.496 0.084 8.52 ;
    END
  END d[7]
  PIN d[80]
    DIRECTION INPUT ;
    USE SIGNAL ;
    PORT
      LAYER M4 ;
        RECT  0 19.008 0.084 19.032 ;
    END
  END d[80]
  PIN d[81]
    DIRECTION INPUT ;
    USE SIGNAL ;
    PORT
      LAYER M4 ;
        RECT  0 19.152 0.084 19.176 ;
    END
  END d[81]
  PIN d[82]
    DIRECTION INPUT ;
    USE SIGNAL ;
    PORT
      LAYER M4 ;
        RECT  0 19.584 0.084 19.608 ;
    END
  END d[82]
  PIN d[83]
    DIRECTION INPUT ;
    USE SIGNAL ;
    PORT
      LAYER M4 ;
        RECT  0 19.296 0.084 19.32 ;
    END
  END d[83]
  PIN d[84]
    DIRECTION INPUT ;
    USE SIGNAL ;
    PORT
      LAYER M4 ;
        RECT  0 19.728 0.084 19.752 ;
    END
  END d[84]
  PIN d[85]
    DIRECTION INPUT ;
    USE SIGNAL ;
    PORT
      LAYER M4 ;
        RECT  0 19.44 0.084 19.464 ;
    END
  END d[85]
  PIN d[86]
    DIRECTION INPUT ;
    USE SIGNAL ;
    PORT
      LAYER M4 ;
        RECT  0 20.016 0.084 20.04 ;
    END
  END d[86]
  PIN d[87]
    DIRECTION INPUT ;
    USE SIGNAL ;
    PORT
      LAYER M4 ;
        RECT  0 19.872 0.084 19.896 ;
    END
  END d[87]
  PIN d[88]
    DIRECTION INPUT ;
    USE SIGNAL ;
    PORT
      LAYER M4 ;
        RECT  0 20.16 0.084 20.184 ;
    END
  END d[88]
  PIN d[89]
    DIRECTION INPUT ;
    USE SIGNAL ;
    PORT
      LAYER M4 ;
        RECT  0 20.304 0.084 20.328 ;
    END
  END d[89]
  PIN d[8]
    DIRECTION INPUT ;
    USE SIGNAL ;
    PORT
      LAYER M4 ;
        RECT  0 8.928 0.084 8.952 ;
    END
  END d[8]
  PIN d[90]
    DIRECTION INPUT ;
    USE SIGNAL ;
    PORT
      LAYER M4 ;
        RECT  0 20.448 0.084 20.472 ;
    END
  END d[90]
  PIN d[91]
    DIRECTION INPUT ;
    USE SIGNAL ;
    PORT
      LAYER M4 ;
        RECT  0 20.592 0.084 20.616 ;
    END
  END d[91]
  PIN d[92]
    DIRECTION INPUT ;
    USE SIGNAL ;
    PORT
      LAYER M4 ;
        RECT  0 20.736 0.084 20.76 ;
    END
  END d[92]
  PIN d[93]
    DIRECTION INPUT ;
    USE SIGNAL ;
    PORT
      LAYER M4 ;
        RECT  0 20.88 0.084 20.904 ;
    END
  END d[93]
  PIN d[94]
    DIRECTION INPUT ;
    USE SIGNAL ;
    PORT
      LAYER M4 ;
        RECT  0 21.024 0.084 21.048 ;
    END
  END d[94]
  PIN d[95]
    DIRECTION INPUT ;
    USE SIGNAL ;
    PORT
      LAYER M4 ;
        RECT  0 21.168 0.084 21.192 ;
    END
  END d[95]
  PIN d[96]
    DIRECTION INPUT ;
    USE SIGNAL ;
    PORT
      LAYER M4 ;
        RECT  0 21.312 0.084 21.336 ;
    END
  END d[96]
  PIN d[97]
    DIRECTION INPUT ;
    USE SIGNAL ;
    PORT
      LAYER M4 ;
        RECT  0 21.456 0.084 21.48 ;
    END
  END d[97]
  PIN d[98]
    DIRECTION INPUT ;
    USE SIGNAL ;
    PORT
      LAYER M4 ;
        RECT  0 21.6 0.084 21.624 ;
    END
  END d[98]
  PIN d[99]
    DIRECTION INPUT ;
    USE SIGNAL ;
    PORT
      LAYER M4 ;
        RECT  0 21.744 0.084 21.768 ;
    END
  END d[99]
  PIN d[9]
    DIRECTION INPUT ;
    USE SIGNAL ;
    PORT
      LAYER M4 ;
        RECT  0 8.64 0.084 8.664 ;
    END
  END d[9]
  PIN fault
    DIRECTION OUTPUT ;
    USE SIGNAL ;
    PORT
      LAYER M4 ;
        RECT  49.596 45.936 49.68 45.96 ;
    END
  END fault
  PIN fclk
    DIRECTION INPUT ;
    USE SIGNAL ;
    PORT
      LAYER M4 ;
        RECT  0 46.08 0.084 46.104 ;
    END
  END fclk
  PIN q[0]
    DIRECTION OUTPUT ;
    USE SIGNAL ;
    PORT
      LAYER M4 ;
        RECT  49.596 7.056 49.68 7.08 ;
    END
  END q[0]
  PIN q[100]
    DIRECTION OUTPUT ;
    USE SIGNAL ;
    PORT
      LAYER M4 ;
        RECT  49.596 21.312 49.68 21.336 ;
    END
  END q[100]
  PIN q[101]
    DIRECTION OUTPUT ;
    USE SIGNAL ;
    PORT
      LAYER M4 ;
        RECT  49.596 21.456 49.68 21.48 ;
    END
  END q[101]
  PIN q[102]
    DIRECTION OUTPUT ;
    USE SIGNAL ;
    PORT
      LAYER M4 ;
        RECT  49.596 21.6 49.68 21.624 ;
    END
  END q[102]
  PIN q[103]
    DIRECTION OUTPUT ;
    USE SIGNAL ;
    PORT
      LAYER M4 ;
        RECT  49.596 21.744 49.68 21.768 ;
    END
  END q[103]
  PIN q[104]
    DIRECTION OUTPUT ;
    USE SIGNAL ;
    PORT
      LAYER M4 ;
        RECT  49.596 21.888 49.68 21.912 ;
    END
  END q[104]
  PIN q[105]
    DIRECTION OUTPUT ;
    USE SIGNAL ;
    PORT
      LAYER M4 ;
        RECT  49.596 22.032 49.68 22.056 ;
    END
  END q[105]
  PIN q[106]
    DIRECTION OUTPUT ;
    USE SIGNAL ;
    PORT
      LAYER M4 ;
        RECT  49.596 22.176 49.68 22.2 ;
    END
  END q[106]
  PIN q[107]
    DIRECTION OUTPUT ;
    USE SIGNAL ;
    PORT
      LAYER M4 ;
        RECT  49.596 22.32 49.68 22.344 ;
    END
  END q[107]
  PIN q[108]
    DIRECTION OUTPUT ;
    USE SIGNAL ;
    PORT
      LAYER M4 ;
        RECT  49.596 22.752 49.68 22.776 ;
    END
  END q[108]
  PIN q[109]
    DIRECTION OUTPUT ;
    USE SIGNAL ;
    PORT
      LAYER M4 ;
        RECT  49.596 22.464 49.68 22.488 ;
    END
  END q[109]
  PIN q[10]
    DIRECTION OUTPUT ;
    USE SIGNAL ;
    PORT
      LAYER M4 ;
        RECT  49.596 8.496 49.68 8.52 ;
    END
  END q[10]
  PIN q[110]
    DIRECTION OUTPUT ;
    USE SIGNAL ;
    PORT
      LAYER M4 ;
        RECT  49.596 22.896 49.68 22.92 ;
    END
  END q[110]
  PIN q[111]
    DIRECTION OUTPUT ;
    USE SIGNAL ;
    PORT
      LAYER M4 ;
        RECT  49.596 22.608 49.68 22.632 ;
    END
  END q[111]
  PIN q[112]
    DIRECTION OUTPUT ;
    USE SIGNAL ;
    PORT
      LAYER M4 ;
        RECT  49.596 23.04 49.68 23.064 ;
    END
  END q[112]
  PIN q[113]
    DIRECTION OUTPUT ;
    USE SIGNAL ;
    PORT
      LAYER M4 ;
        RECT  49.596 23.184 49.68 23.208 ;
    END
  END q[113]
  PIN q[114]
    DIRECTION OUTPUT ;
    USE SIGNAL ;
    PORT
      LAYER M4 ;
        RECT  49.596 23.328 49.68 23.352 ;
    END
  END q[114]
  PIN q[115]
    DIRECTION OUTPUT ;
    USE SIGNAL ;
    PORT
      LAYER M4 ;
        RECT  49.596 23.472 49.68 23.496 ;
    END
  END q[115]
  PIN q[116]
    DIRECTION OUTPUT ;
    USE SIGNAL ;
    PORT
      LAYER M4 ;
        RECT  49.596 23.616 49.68 23.64 ;
    END
  END q[116]
  PIN q[117]
    DIRECTION OUTPUT ;
    USE SIGNAL ;
    PORT
      LAYER M4 ;
        RECT  49.596 23.76 49.68 23.784 ;
    END
  END q[117]
  PIN q[118]
    DIRECTION OUTPUT ;
    USE SIGNAL ;
    PORT
      LAYER M4 ;
        RECT  49.596 23.904 49.68 23.928 ;
    END
  END q[118]
  PIN q[119]
    DIRECTION OUTPUT ;
    USE SIGNAL ;
    PORT
      LAYER M4 ;
        RECT  49.596 24.048 49.68 24.072 ;
    END
  END q[119]
  PIN q[11]
    DIRECTION OUTPUT ;
    USE SIGNAL ;
    PORT
      LAYER M4 ;
        RECT  49.596 8.208 49.68 8.232 ;
    END
  END q[11]
  PIN q[120]
    DIRECTION OUTPUT ;
    USE SIGNAL ;
    PORT
      LAYER M4 ;
        RECT  49.596 24.192 49.68 24.216 ;
    END
  END q[120]
  PIN q[121]
    DIRECTION OUTPUT ;
    USE SIGNAL ;
    PORT
      LAYER M4 ;
        RECT  49.596 24.336 49.68 24.36 ;
    END
  END q[121]
  PIN q[122]
    DIRECTION OUTPUT ;
    USE SIGNAL ;
    PORT
      LAYER M4 ;
        RECT  49.596 24.48 49.68 24.504 ;
    END
  END q[122]
  PIN q[123]
    DIRECTION OUTPUT ;
    USE SIGNAL ;
    PORT
      LAYER M4 ;
        RECT  49.596 24.624 49.68 24.648 ;
    END
  END q[123]
  PIN q[124]
    DIRECTION OUTPUT ;
    USE SIGNAL ;
    PORT
      LAYER M4 ;
        RECT  49.596 24.768 49.68 24.792 ;
    END
  END q[124]
  PIN q[125]
    DIRECTION OUTPUT ;
    USE SIGNAL ;
    PORT
      LAYER M4 ;
        RECT  49.596 24.912 49.68 24.936 ;
    END
  END q[125]
  PIN q[126]
    DIRECTION OUTPUT ;
    USE SIGNAL ;
    PORT
      LAYER M4 ;
        RECT  49.596 25.056 49.68 25.08 ;
    END
  END q[126]
  PIN q[127]
    DIRECTION OUTPUT ;
    USE SIGNAL ;
    PORT
      LAYER M4 ;
        RECT  49.596 25.2 49.68 25.224 ;
    END
  END q[127]
  PIN q[128]
    DIRECTION OUTPUT ;
    USE SIGNAL ;
    PORT
      LAYER M4 ;
        RECT  49.596 25.344 49.68 25.368 ;
    END
  END q[128]
  PIN q[129]
    DIRECTION OUTPUT ;
    USE SIGNAL ;
    PORT
      LAYER M4 ;
        RECT  49.596 25.488 49.68 25.512 ;
    END
  END q[129]
  PIN q[12]
    DIRECTION OUTPUT ;
    USE SIGNAL ;
    PORT
      LAYER M4 ;
        RECT  49.596 8.784 49.68 8.808 ;
    END
  END q[12]
  PIN q[130]
    DIRECTION OUTPUT ;
    USE SIGNAL ;
    PORT
      LAYER M4 ;
        RECT  49.596 25.632 49.68 25.656 ;
    END
  END q[130]
  PIN q[131]
    DIRECTION OUTPUT ;
    USE SIGNAL ;
    PORT
      LAYER M4 ;
        RECT  49.596 25.776 49.68 25.8 ;
    END
  END q[131]
  PIN q[132]
    DIRECTION OUTPUT ;
    USE SIGNAL ;
    PORT
      LAYER M4 ;
        RECT  49.596 26.208 49.68 26.232 ;
    END
  END q[132]
  PIN q[133]
    DIRECTION OUTPUT ;
    USE SIGNAL ;
    PORT
      LAYER M4 ;
        RECT  49.596 25.92 49.68 25.944 ;
    END
  END q[133]
  PIN q[134]
    DIRECTION OUTPUT ;
    USE SIGNAL ;
    PORT
      LAYER M4 ;
        RECT  49.596 26.352 49.68 26.376 ;
    END
  END q[134]
  PIN q[135]
    DIRECTION OUTPUT ;
    USE SIGNAL ;
    PORT
      LAYER M4 ;
        RECT  49.596 26.064 49.68 26.088 ;
    END
  END q[135]
  PIN q[136]
    DIRECTION OUTPUT ;
    USE SIGNAL ;
    PORT
      LAYER M4 ;
        RECT  49.596 26.64 49.68 26.664 ;
    END
  END q[136]
  PIN q[137]
    DIRECTION OUTPUT ;
    USE SIGNAL ;
    PORT
      LAYER M4 ;
        RECT  49.596 26.496 49.68 26.52 ;
    END
  END q[137]
  PIN q[138]
    DIRECTION OUTPUT ;
    USE SIGNAL ;
    PORT
      LAYER M4 ;
        RECT  49.596 26.784 49.68 26.808 ;
    END
  END q[138]
  PIN q[139]
    DIRECTION OUTPUT ;
    USE SIGNAL ;
    PORT
      LAYER M4 ;
        RECT  49.596 26.928 49.68 26.952 ;
    END
  END q[139]
  PIN q[13]
    DIRECTION OUTPUT ;
    USE SIGNAL ;
    PORT
      LAYER M4 ;
        RECT  49.596 8.64 49.68 8.664 ;
    END
  END q[13]
  PIN q[140]
    DIRECTION OUTPUT ;
    USE SIGNAL ;
    PORT
      LAYER M4 ;
        RECT  49.596 27.072 49.68 27.096 ;
    END
  END q[140]
  PIN q[141]
    DIRECTION OUTPUT ;
    USE SIGNAL ;
    PORT
      LAYER M4 ;
        RECT  49.596 27.216 49.68 27.24 ;
    END
  END q[141]
  PIN q[142]
    DIRECTION OUTPUT ;
    USE SIGNAL ;
    PORT
      LAYER M4 ;
        RECT  49.596 27.36 49.68 27.384 ;
    END
  END q[142]
  PIN q[143]
    DIRECTION OUTPUT ;
    USE SIGNAL ;
    PORT
      LAYER M4 ;
        RECT  49.596 27.504 49.68 27.528 ;
    END
  END q[143]
  PIN q[144]
    DIRECTION OUTPUT ;
    USE SIGNAL ;
    PORT
      LAYER M4 ;
        RECT  49.596 27.648 49.68 27.672 ;
    END
  END q[144]
  PIN q[145]
    DIRECTION OUTPUT ;
    USE SIGNAL ;
    PORT
      LAYER M4 ;
        RECT  49.596 27.792 49.68 27.816 ;
    END
  END q[145]
  PIN q[146]
    DIRECTION OUTPUT ;
    USE SIGNAL ;
    PORT
      LAYER M4 ;
        RECT  49.596 27.936 49.68 27.96 ;
    END
  END q[146]
  PIN q[147]
    DIRECTION OUTPUT ;
    USE SIGNAL ;
    PORT
      LAYER M4 ;
        RECT  49.596 28.08 49.68 28.104 ;
    END
  END q[147]
  PIN q[148]
    DIRECTION OUTPUT ;
    USE SIGNAL ;
    PORT
      LAYER M4 ;
        RECT  49.596 28.224 49.68 28.248 ;
    END
  END q[148]
  PIN q[149]
    DIRECTION OUTPUT ;
    USE SIGNAL ;
    PORT
      LAYER M4 ;
        RECT  49.596 28.368 49.68 28.392 ;
    END
  END q[149]
  PIN q[14]
    DIRECTION OUTPUT ;
    USE SIGNAL ;
    PORT
      LAYER M4 ;
        RECT  49.596 8.928 49.68 8.952 ;
    END
  END q[14]
  PIN q[150]
    DIRECTION OUTPUT ;
    USE SIGNAL ;
    PORT
      LAYER M4 ;
        RECT  49.596 28.512 49.68 28.536 ;
    END
  END q[150]
  PIN q[151]
    DIRECTION OUTPUT ;
    USE SIGNAL ;
    PORT
      LAYER M4 ;
        RECT  49.596 28.656 49.68 28.68 ;
    END
  END q[151]
  PIN q[152]
    DIRECTION OUTPUT ;
    USE SIGNAL ;
    PORT
      LAYER M4 ;
        RECT  49.596 28.8 49.68 28.824 ;
    END
  END q[152]
  PIN q[153]
    DIRECTION OUTPUT ;
    USE SIGNAL ;
    PORT
      LAYER M4 ;
        RECT  49.596 28.944 49.68 28.968 ;
    END
  END q[153]
  PIN q[154]
    DIRECTION OUTPUT ;
    USE SIGNAL ;
    PORT
      LAYER M4 ;
        RECT  49.596 29.088 49.68 29.112 ;
    END
  END q[154]
  PIN q[155]
    DIRECTION OUTPUT ;
    USE SIGNAL ;
    PORT
      LAYER M4 ;
        RECT  49.596 29.232 49.68 29.256 ;
    END
  END q[155]
  PIN q[156]
    DIRECTION OUTPUT ;
    USE SIGNAL ;
    PORT
      LAYER M4 ;
        RECT  49.596 29.376 49.68 29.4 ;
    END
  END q[156]
  PIN q[157]
    DIRECTION OUTPUT ;
    USE SIGNAL ;
    PORT
      LAYER M4 ;
        RECT  49.596 29.52 49.68 29.544 ;
    END
  END q[157]
  PIN q[158]
    DIRECTION OUTPUT ;
    USE SIGNAL ;
    PORT
      LAYER M4 ;
        RECT  49.596 29.808 49.68 29.832 ;
    END
  END q[158]
  PIN q[159]
    DIRECTION OUTPUT ;
    USE SIGNAL ;
    PORT
      LAYER M4 ;
        RECT  49.596 29.664 49.68 29.688 ;
    END
  END q[159]
  PIN q[15]
    DIRECTION OUTPUT ;
    USE SIGNAL ;
    PORT
      LAYER M4 ;
        RECT  49.596 9.072 49.68 9.096 ;
    END
  END q[15]
  PIN q[160]
    DIRECTION OUTPUT ;
    USE SIGNAL ;
    PORT
      LAYER M4 ;
        RECT  49.596 30.096 49.68 30.12 ;
    END
  END q[160]
  PIN q[161]
    DIRECTION OUTPUT ;
    USE SIGNAL ;
    PORT
      LAYER M4 ;
        RECT  49.596 29.952 49.68 29.976 ;
    END
  END q[161]
  PIN q[162]
    DIRECTION OUTPUT ;
    USE SIGNAL ;
    PORT
      LAYER M4 ;
        RECT  49.596 30.24 49.68 30.264 ;
    END
  END q[162]
  PIN q[163]
    DIRECTION OUTPUT ;
    USE SIGNAL ;
    PORT
      LAYER M4 ;
        RECT  49.596 30.384 49.68 30.408 ;
    END
  END q[163]
  PIN q[164]
    DIRECTION OUTPUT ;
    USE SIGNAL ;
    PORT
      LAYER M4 ;
        RECT  49.596 30.528 49.68 30.552 ;
    END
  END q[164]
  PIN q[165]
    DIRECTION OUTPUT ;
    USE SIGNAL ;
    PORT
      LAYER M4 ;
        RECT  49.596 30.672 49.68 30.696 ;
    END
  END q[165]
  PIN q[166]
    DIRECTION OUTPUT ;
    USE SIGNAL ;
    PORT
      LAYER M4 ;
        RECT  49.596 30.816 49.68 30.84 ;
    END
  END q[166]
  PIN q[167]
    DIRECTION OUTPUT ;
    USE SIGNAL ;
    PORT
      LAYER M4 ;
        RECT  49.596 30.96 49.68 30.984 ;
    END
  END q[167]
  PIN q[168]
    DIRECTION OUTPUT ;
    USE SIGNAL ;
    PORT
      LAYER M4 ;
        RECT  49.596 31.104 49.68 31.128 ;
    END
  END q[168]
  PIN q[169]
    DIRECTION OUTPUT ;
    USE SIGNAL ;
    PORT
      LAYER M4 ;
        RECT  49.596 31.248 49.68 31.272 ;
    END
  END q[169]
  PIN q[16]
    DIRECTION OUTPUT ;
    USE SIGNAL ;
    PORT
      LAYER M4 ;
        RECT  49.596 9.216 49.68 9.24 ;
    END
  END q[16]
  PIN q[170]
    DIRECTION OUTPUT ;
    USE SIGNAL ;
    PORT
      LAYER M4 ;
        RECT  49.596 31.392 49.68 31.416 ;
    END
  END q[170]
  PIN q[171]
    DIRECTION OUTPUT ;
    USE SIGNAL ;
    PORT
      LAYER M4 ;
        RECT  49.596 31.536 49.68 31.56 ;
    END
  END q[171]
  PIN q[172]
    DIRECTION OUTPUT ;
    USE SIGNAL ;
    PORT
      LAYER M4 ;
        RECT  49.596 31.68 49.68 31.704 ;
    END
  END q[172]
  PIN q[173]
    DIRECTION OUTPUT ;
    USE SIGNAL ;
    PORT
      LAYER M4 ;
        RECT  49.596 31.824 49.68 31.848 ;
    END
  END q[173]
  PIN q[174]
    DIRECTION OUTPUT ;
    USE SIGNAL ;
    PORT
      LAYER M4 ;
        RECT  49.596 31.968 49.68 31.992 ;
    END
  END q[174]
  PIN q[175]
    DIRECTION OUTPUT ;
    USE SIGNAL ;
    PORT
      LAYER M4 ;
        RECT  49.596 32.112 49.68 32.136 ;
    END
  END q[175]
  PIN q[176]
    DIRECTION OUTPUT ;
    USE SIGNAL ;
    PORT
      LAYER M4 ;
        RECT  49.596 32.256 49.68 32.28 ;
    END
  END q[176]
  PIN q[177]
    DIRECTION OUTPUT ;
    USE SIGNAL ;
    PORT
      LAYER M4 ;
        RECT  49.596 32.4 49.68 32.424 ;
    END
  END q[177]
  PIN q[178]
    DIRECTION OUTPUT ;
    USE SIGNAL ;
    PORT
      LAYER M4 ;
        RECT  49.596 32.544 49.68 32.568 ;
    END
  END q[178]
  PIN q[179]
    DIRECTION OUTPUT ;
    USE SIGNAL ;
    PORT
      LAYER M4 ;
        RECT  49.596 32.688 49.68 32.712 ;
    END
  END q[179]
  PIN q[17]
    DIRECTION OUTPUT ;
    USE SIGNAL ;
    PORT
      LAYER M4 ;
        RECT  49.596 9.36 49.68 9.384 ;
    END
  END q[17]
  PIN q[180]
    DIRECTION OUTPUT ;
    USE SIGNAL ;
    PORT
      LAYER M4 ;
        RECT  49.596 32.832 49.68 32.856 ;
    END
  END q[180]
  PIN q[181]
    DIRECTION OUTPUT ;
    USE SIGNAL ;
    PORT
      LAYER M4 ;
        RECT  49.596 32.976 49.68 33 ;
    END
  END q[181]
  PIN q[182]
    DIRECTION OUTPUT ;
    USE SIGNAL ;
    PORT
      LAYER M4 ;
        RECT  49.596 33.408 49.68 33.432 ;
    END
  END q[182]
  PIN q[183]
    DIRECTION OUTPUT ;
    USE SIGNAL ;
    PORT
      LAYER M4 ;
        RECT  49.596 33.12 49.68 33.144 ;
    END
  END q[183]
  PIN q[184]
    DIRECTION OUTPUT ;
    USE SIGNAL ;
    PORT
      LAYER M4 ;
        RECT  49.596 33.552 49.68 33.576 ;
    END
  END q[184]
  PIN q[185]
    DIRECTION OUTPUT ;
    USE SIGNAL ;
    PORT
      LAYER M4 ;
        RECT  49.596 33.264 49.68 33.288 ;
    END
  END q[185]
  PIN q[186]
    DIRECTION OUTPUT ;
    USE SIGNAL ;
    PORT
      LAYER M4 ;
        RECT  49.596 33.84 49.68 33.864 ;
    END
  END q[186]
  PIN q[187]
    DIRECTION OUTPUT ;
    USE SIGNAL ;
    PORT
      LAYER M4 ;
        RECT  49.596 33.696 49.68 33.72 ;
    END
  END q[187]
  PIN q[188]
    DIRECTION OUTPUT ;
    USE SIGNAL ;
    PORT
      LAYER M4 ;
        RECT  49.596 33.984 49.68 34.008 ;
    END
  END q[188]
  PIN q[189]
    DIRECTION OUTPUT ;
    USE SIGNAL ;
    PORT
      LAYER M4 ;
        RECT  49.596 34.128 49.68 34.152 ;
    END
  END q[189]
  PIN q[18]
    DIRECTION OUTPUT ;
    USE SIGNAL ;
    PORT
      LAYER M4 ;
        RECT  49.596 9.504 49.68 9.528 ;
    END
  END q[18]
  PIN q[190]
    DIRECTION OUTPUT ;
    USE SIGNAL ;
    PORT
      LAYER M4 ;
        RECT  49.596 34.272 49.68 34.296 ;
    END
  END q[190]
  PIN q[191]
    DIRECTION OUTPUT ;
    USE SIGNAL ;
    PORT
      LAYER M4 ;
        RECT  49.596 34.416 49.68 34.44 ;
    END
  END q[191]
  PIN q[192]
    DIRECTION OUTPUT ;
    USE SIGNAL ;
    PORT
      LAYER M4 ;
        RECT  49.596 34.56 49.68 34.584 ;
    END
  END q[192]
  PIN q[193]
    DIRECTION OUTPUT ;
    USE SIGNAL ;
    PORT
      LAYER M4 ;
        RECT  49.596 34.704 49.68 34.728 ;
    END
  END q[193]
  PIN q[194]
    DIRECTION OUTPUT ;
    USE SIGNAL ;
    PORT
      LAYER M4 ;
        RECT  49.596 34.848 49.68 34.872 ;
    END
  END q[194]
  PIN q[195]
    DIRECTION OUTPUT ;
    USE SIGNAL ;
    PORT
      LAYER M4 ;
        RECT  49.596 34.992 49.68 35.016 ;
    END
  END q[195]
  PIN q[196]
    DIRECTION OUTPUT ;
    USE SIGNAL ;
    PORT
      LAYER M4 ;
        RECT  49.596 35.136 49.68 35.16 ;
    END
  END q[196]
  PIN q[197]
    DIRECTION OUTPUT ;
    USE SIGNAL ;
    PORT
      LAYER M4 ;
        RECT  49.596 35.28 49.68 35.304 ;
    END
  END q[197]
  PIN q[198]
    DIRECTION OUTPUT ;
    USE SIGNAL ;
    PORT
      LAYER M4 ;
        RECT  49.596 35.424 49.68 35.448 ;
    END
  END q[198]
  PIN q[199]
    DIRECTION OUTPUT ;
    USE SIGNAL ;
    PORT
      LAYER M4 ;
        RECT  49.596 35.568 49.68 35.592 ;
    END
  END q[199]
  PIN q[19]
    DIRECTION OUTPUT ;
    USE SIGNAL ;
    PORT
      LAYER M4 ;
        RECT  49.596 9.648 49.68 9.672 ;
    END
  END q[19]
  PIN q[1]
    DIRECTION OUTPUT ;
    USE SIGNAL ;
    PORT
      LAYER M4 ;
        RECT  49.596 6.912 49.68 6.936 ;
    END
  END q[1]
  PIN q[200]
    DIRECTION OUTPUT ;
    USE SIGNAL ;
    PORT
      LAYER M4 ;
        RECT  49.596 35.712 49.68 35.736 ;
    END
  END q[200]
  PIN q[201]
    DIRECTION OUTPUT ;
    USE SIGNAL ;
    PORT
      LAYER M4 ;
        RECT  49.596 35.856 49.68 35.88 ;
    END
  END q[201]
  PIN q[202]
    DIRECTION OUTPUT ;
    USE SIGNAL ;
    PORT
      LAYER M4 ;
        RECT  49.596 36 49.68 36.024 ;
    END
  END q[202]
  PIN q[203]
    DIRECTION OUTPUT ;
    USE SIGNAL ;
    PORT
      LAYER M4 ;
        RECT  49.596 36.144 49.68 36.168 ;
    END
  END q[203]
  PIN q[204]
    DIRECTION OUTPUT ;
    USE SIGNAL ;
    PORT
      LAYER M4 ;
        RECT  49.596 36.288 49.68 36.312 ;
    END
  END q[204]
  PIN q[205]
    DIRECTION OUTPUT ;
    USE SIGNAL ;
    PORT
      LAYER M4 ;
        RECT  49.596 36.432 49.68 36.456 ;
    END
  END q[205]
  PIN q[206]
    DIRECTION OUTPUT ;
    USE SIGNAL ;
    PORT
      LAYER M4 ;
        RECT  49.596 36.576 49.68 36.6 ;
    END
  END q[206]
  PIN q[207]
    DIRECTION OUTPUT ;
    USE SIGNAL ;
    PORT
      LAYER M4 ;
        RECT  49.596 36.72 49.68 36.744 ;
    END
  END q[207]
  PIN q[208]
    DIRECTION OUTPUT ;
    USE SIGNAL ;
    PORT
      LAYER M4 ;
        RECT  49.596 37.008 49.68 37.032 ;
    END
  END q[208]
  PIN q[209]
    DIRECTION OUTPUT ;
    USE SIGNAL ;
    PORT
      LAYER M4 ;
        RECT  49.596 36.864 49.68 36.888 ;
    END
  END q[209]
  PIN q[20]
    DIRECTION OUTPUT ;
    USE SIGNAL ;
    PORT
      LAYER M4 ;
        RECT  49.596 9.936 49.68 9.96 ;
    END
  END q[20]
  PIN q[210]
    DIRECTION OUTPUT ;
    USE SIGNAL ;
    PORT
      LAYER M4 ;
        RECT  49.596 37.296 49.68 37.32 ;
    END
  END q[210]
  PIN q[211]
    DIRECTION OUTPUT ;
    USE SIGNAL ;
    PORT
      LAYER M4 ;
        RECT  49.596 37.152 49.68 37.176 ;
    END
  END q[211]
  PIN q[212]
    DIRECTION OUTPUT ;
    USE SIGNAL ;
    PORT
      LAYER M4 ;
        RECT  49.596 37.44 49.68 37.464 ;
    END
  END q[212]
  PIN q[213]
    DIRECTION OUTPUT ;
    USE SIGNAL ;
    PORT
      LAYER M4 ;
        RECT  49.596 37.584 49.68 37.608 ;
    END
  END q[213]
  PIN q[214]
    DIRECTION OUTPUT ;
    USE SIGNAL ;
    PORT
      LAYER M4 ;
        RECT  49.596 37.728 49.68 37.752 ;
    END
  END q[214]
  PIN q[215]
    DIRECTION OUTPUT ;
    USE SIGNAL ;
    PORT
      LAYER M4 ;
        RECT  49.596 37.872 49.68 37.896 ;
    END
  END q[215]
  PIN q[216]
    DIRECTION OUTPUT ;
    USE SIGNAL ;
    PORT
      LAYER M4 ;
        RECT  49.596 38.016 49.68 38.04 ;
    END
  END q[216]
  PIN q[217]
    DIRECTION OUTPUT ;
    USE SIGNAL ;
    PORT
      LAYER M4 ;
        RECT  49.596 38.16 49.68 38.184 ;
    END
  END q[217]
  PIN q[218]
    DIRECTION OUTPUT ;
    USE SIGNAL ;
    PORT
      LAYER M4 ;
        RECT  49.596 38.304 49.68 38.328 ;
    END
  END q[218]
  PIN q[219]
    DIRECTION OUTPUT ;
    USE SIGNAL ;
    PORT
      LAYER M4 ;
        RECT  49.596 38.448 49.68 38.472 ;
    END
  END q[219]
  PIN q[21]
    DIRECTION OUTPUT ;
    USE SIGNAL ;
    PORT
      LAYER M4 ;
        RECT  49.596 9.792 49.68 9.816 ;
    END
  END q[21]
  PIN q[220]
    DIRECTION OUTPUT ;
    USE SIGNAL ;
    PORT
      LAYER M4 ;
        RECT  49.596 38.592 49.68 38.616 ;
    END
  END q[220]
  PIN q[221]
    DIRECTION OUTPUT ;
    USE SIGNAL ;
    PORT
      LAYER M4 ;
        RECT  49.596 38.736 49.68 38.76 ;
    END
  END q[221]
  PIN q[222]
    DIRECTION OUTPUT ;
    USE SIGNAL ;
    PORT
      LAYER M4 ;
        RECT  49.596 38.88 49.68 38.904 ;
    END
  END q[222]
  PIN q[223]
    DIRECTION OUTPUT ;
    USE SIGNAL ;
    PORT
      LAYER M4 ;
        RECT  49.596 39.024 49.68 39.048 ;
    END
  END q[223]
  PIN q[224]
    DIRECTION OUTPUT ;
    USE SIGNAL ;
    PORT
      LAYER M4 ;
        RECT  49.596 39.168 49.68 39.192 ;
    END
  END q[224]
  PIN q[225]
    DIRECTION OUTPUT ;
    USE SIGNAL ;
    PORT
      LAYER M4 ;
        RECT  49.596 39.312 49.68 39.336 ;
    END
  END q[225]
  PIN q[226]
    DIRECTION OUTPUT ;
    USE SIGNAL ;
    PORT
      LAYER M4 ;
        RECT  49.596 39.456 49.68 39.48 ;
    END
  END q[226]
  PIN q[227]
    DIRECTION OUTPUT ;
    USE SIGNAL ;
    PORT
      LAYER M4 ;
        RECT  49.596 39.6 49.68 39.624 ;
    END
  END q[227]
  PIN q[228]
    DIRECTION OUTPUT ;
    USE SIGNAL ;
    PORT
      LAYER M4 ;
        RECT  49.596 39.744 49.68 39.768 ;
    END
  END q[228]
  PIN q[229]
    DIRECTION OUTPUT ;
    USE SIGNAL ;
    PORT
      LAYER M4 ;
        RECT  49.596 39.888 49.68 39.912 ;
    END
  END q[229]
  PIN q[22]
    DIRECTION OUTPUT ;
    USE SIGNAL ;
    PORT
      LAYER M4 ;
        RECT  49.596 10.08 49.68 10.104 ;
    END
  END q[22]
  PIN q[230]
    DIRECTION OUTPUT ;
    USE SIGNAL ;
    PORT
      LAYER M4 ;
        RECT  49.596 40.032 49.68 40.056 ;
    END
  END q[230]
  PIN q[231]
    DIRECTION OUTPUT ;
    USE SIGNAL ;
    PORT
      LAYER M4 ;
        RECT  49.596 40.176 49.68 40.2 ;
    END
  END q[231]
  PIN q[232]
    DIRECTION OUTPUT ;
    USE SIGNAL ;
    PORT
      LAYER M4 ;
        RECT  49.596 40.608 49.68 40.632 ;
    END
  END q[232]
  PIN q[233]
    DIRECTION OUTPUT ;
    USE SIGNAL ;
    PORT
      LAYER M4 ;
        RECT  49.596 40.32 49.68 40.344 ;
    END
  END q[233]
  PIN q[234]
    DIRECTION OUTPUT ;
    USE SIGNAL ;
    PORT
      LAYER M4 ;
        RECT  49.596 40.752 49.68 40.776 ;
    END
  END q[234]
  PIN q[235]
    DIRECTION OUTPUT ;
    USE SIGNAL ;
    PORT
      LAYER M4 ;
        RECT  49.596 40.464 49.68 40.488 ;
    END
  END q[235]
  PIN q[236]
    DIRECTION OUTPUT ;
    USE SIGNAL ;
    PORT
      LAYER M4 ;
        RECT  49.596 40.896 49.68 40.92 ;
    END
  END q[236]
  PIN q[237]
    DIRECTION OUTPUT ;
    USE SIGNAL ;
    PORT
      LAYER M4 ;
        RECT  49.596 41.04 49.68 41.064 ;
    END
  END q[237]
  PIN q[238]
    DIRECTION OUTPUT ;
    USE SIGNAL ;
    PORT
      LAYER M4 ;
        RECT  49.596 41.184 49.68 41.208 ;
    END
  END q[238]
  PIN q[239]
    DIRECTION OUTPUT ;
    USE SIGNAL ;
    PORT
      LAYER M4 ;
        RECT  49.596 41.328 49.68 41.352 ;
    END
  END q[239]
  PIN q[23]
    DIRECTION OUTPUT ;
    USE SIGNAL ;
    PORT
      LAYER M4 ;
        RECT  49.596 10.224 49.68 10.248 ;
    END
  END q[23]
  PIN q[240]
    DIRECTION OUTPUT ;
    USE SIGNAL ;
    PORT
      LAYER M4 ;
        RECT  49.596 41.472 49.68 41.496 ;
    END
  END q[240]
  PIN q[241]
    DIRECTION OUTPUT ;
    USE SIGNAL ;
    PORT
      LAYER M4 ;
        RECT  49.596 41.616 49.68 41.64 ;
    END
  END q[241]
  PIN q[242]
    DIRECTION OUTPUT ;
    USE SIGNAL ;
    PORT
      LAYER M4 ;
        RECT  49.596 41.76 49.68 41.784 ;
    END
  END q[242]
  PIN q[243]
    DIRECTION OUTPUT ;
    USE SIGNAL ;
    PORT
      LAYER M4 ;
        RECT  49.596 41.904 49.68 41.928 ;
    END
  END q[243]
  PIN q[244]
    DIRECTION OUTPUT ;
    USE SIGNAL ;
    PORT
      LAYER M4 ;
        RECT  49.596 42.048 49.68 42.072 ;
    END
  END q[244]
  PIN q[245]
    DIRECTION OUTPUT ;
    USE SIGNAL ;
    PORT
      LAYER M4 ;
        RECT  49.596 42.192 49.68 42.216 ;
    END
  END q[245]
  PIN q[246]
    DIRECTION OUTPUT ;
    USE SIGNAL ;
    PORT
      LAYER M4 ;
        RECT  49.596 42.336 49.68 42.36 ;
    END
  END q[246]
  PIN q[247]
    DIRECTION OUTPUT ;
    USE SIGNAL ;
    PORT
      LAYER M4 ;
        RECT  49.596 42.48 49.68 42.504 ;
    END
  END q[247]
  PIN q[248]
    DIRECTION OUTPUT ;
    USE SIGNAL ;
    PORT
      LAYER M4 ;
        RECT  49.596 42.624 49.68 42.648 ;
    END
  END q[248]
  PIN q[249]
    DIRECTION OUTPUT ;
    USE SIGNAL ;
    PORT
      LAYER M4 ;
        RECT  49.596 42.768 49.68 42.792 ;
    END
  END q[249]
  PIN q[24]
    DIRECTION OUTPUT ;
    USE SIGNAL ;
    PORT
      LAYER M4 ;
        RECT  49.596 10.368 49.68 10.392 ;
    END
  END q[24]
  PIN q[250]
    DIRECTION OUTPUT ;
    USE SIGNAL ;
    PORT
      LAYER M4 ;
        RECT  49.596 42.912 49.68 42.936 ;
    END
  END q[250]
  PIN q[251]
    DIRECTION OUTPUT ;
    USE SIGNAL ;
    PORT
      LAYER M4 ;
        RECT  49.596 43.056 49.68 43.08 ;
    END
  END q[251]
  PIN q[252]
    DIRECTION OUTPUT ;
    USE SIGNAL ;
    PORT
      LAYER M4 ;
        RECT  49.596 43.2 49.68 43.224 ;
    END
  END q[252]
  PIN q[253]
    DIRECTION OUTPUT ;
    USE SIGNAL ;
    PORT
      LAYER M4 ;
        RECT  49.596 43.344 49.68 43.368 ;
    END
  END q[253]
  PIN q[254]
    DIRECTION OUTPUT ;
    USE SIGNAL ;
    PORT
      LAYER M4 ;
        RECT  49.596 43.488 49.68 43.512 ;
    END
  END q[254]
  PIN q[255]
    DIRECTION OUTPUT ;
    USE SIGNAL ;
    PORT
      LAYER M4 ;
        RECT  49.596 43.776 49.68 43.8 ;
    END
  END q[255]
  PIN q[256]
    DIRECTION OUTPUT ;
    USE SIGNAL ;
    PORT
      LAYER M4 ;
        RECT  49.596 43.632 49.68 43.656 ;
    END
  END q[256]
  PIN q[257]
    DIRECTION OUTPUT ;
    USE SIGNAL ;
    PORT
      LAYER M4 ;
        RECT  49.596 43.92 49.68 43.944 ;
    END
  END q[257]
  PIN q[258]
    DIRECTION OUTPUT ;
    USE SIGNAL ;
    PORT
      LAYER M4 ;
        RECT  49.596 44.208 49.68 44.232 ;
    END
  END q[258]
  PIN q[259]
    DIRECTION OUTPUT ;
    USE SIGNAL ;
    PORT
      LAYER M4 ;
        RECT  49.596 44.064 49.68 44.088 ;
    END
  END q[259]
  PIN q[25]
    DIRECTION OUTPUT ;
    USE SIGNAL ;
    PORT
      LAYER M4 ;
        RECT  49.596 10.512 49.68 10.536 ;
    END
  END q[25]
  PIN q[260]
    DIRECTION OUTPUT ;
    USE SIGNAL ;
    PORT
      LAYER M4 ;
        RECT  49.596 44.496 49.68 44.52 ;
    END
  END q[260]
  PIN q[261]
    DIRECTION OUTPUT ;
    USE SIGNAL ;
    PORT
      LAYER M4 ;
        RECT  49.596 44.352 49.68 44.376 ;
    END
  END q[261]
  PIN q[262]
    DIRECTION OUTPUT ;
    USE SIGNAL ;
    PORT
      LAYER M4 ;
        RECT  49.596 44.64 49.68 44.664 ;
    END
  END q[262]
  PIN q[263]
    DIRECTION OUTPUT ;
    USE SIGNAL ;
    PORT
      LAYER M4 ;
        RECT  49.596 44.784 49.68 44.808 ;
    END
  END q[263]
  PIN q[264]
    DIRECTION OUTPUT ;
    USE SIGNAL ;
    PORT
      LAYER M4 ;
        RECT  49.596 44.928 49.68 44.952 ;
    END
  END q[264]
  PIN q[265]
    DIRECTION OUTPUT ;
    USE SIGNAL ;
    PORT
      LAYER M4 ;
        RECT  49.596 45.072 49.68 45.096 ;
    END
  END q[265]
  PIN q[266]
    DIRECTION OUTPUT ;
    USE SIGNAL ;
    PORT
      LAYER M4 ;
        RECT  49.596 45.216 49.68 45.24 ;
    END
  END q[266]
  PIN q[267]
    DIRECTION OUTPUT ;
    USE SIGNAL ;
    PORT
      LAYER M4 ;
        RECT  49.596 45.36 49.68 45.384 ;
    END
  END q[267]
  PIN q[268]
    DIRECTION OUTPUT ;
    USE SIGNAL ;
    PORT
      LAYER M4 ;
        RECT  49.596 46.944 49.68 46.968 ;
    END
  END q[268]
  PIN q[269]
    DIRECTION OUTPUT ;
    USE SIGNAL ;
    PORT
      LAYER M4 ;
        RECT  49.596 47.088 49.68 47.112 ;
    END
  END q[269]
  PIN q[26]
    DIRECTION OUTPUT ;
    USE SIGNAL ;
    PORT
      LAYER M4 ;
        RECT  49.596 10.656 49.68 10.68 ;
    END
  END q[26]
  PIN q[270]
    DIRECTION OUTPUT ;
    USE SIGNAL ;
    PORT
      LAYER M4 ;
        RECT  49.596 47.232 49.68 47.256 ;
    END
  END q[270]
  PIN q[271]
    DIRECTION OUTPUT ;
    USE SIGNAL ;
    PORT
      LAYER M4 ;
        RECT  49.596 47.376 49.68 47.4 ;
    END
  END q[271]
  PIN q[272]
    DIRECTION OUTPUT ;
    USE SIGNAL ;
    PORT
      LAYER M4 ;
        RECT  49.596 47.52 49.68 47.544 ;
    END
  END q[272]
  PIN q[273]
    DIRECTION OUTPUT ;
    USE SIGNAL ;
    PORT
      LAYER M4 ;
        RECT  49.596 47.664 49.68 47.688 ;
    END
  END q[273]
  PIN q[274]
    DIRECTION OUTPUT ;
    USE SIGNAL ;
    PORT
      LAYER M4 ;
        RECT  49.596 47.808 49.68 47.832 ;
    END
  END q[274]
  PIN q[275]
    DIRECTION OUTPUT ;
    USE SIGNAL ;
    PORT
      LAYER M4 ;
        RECT  49.596 47.952 49.68 47.976 ;
    END
  END q[275]
  PIN q[276]
    DIRECTION OUTPUT ;
    USE SIGNAL ;
    PORT
      LAYER M4 ;
        RECT  49.596 48.096 49.68 48.12 ;
    END
  END q[276]
  PIN q[277]
    DIRECTION OUTPUT ;
    USE SIGNAL ;
    PORT
      LAYER M4 ;
        RECT  49.596 48.24 49.68 48.264 ;
    END
  END q[277]
  PIN q[278]
    DIRECTION OUTPUT ;
    USE SIGNAL ;
    PORT
      LAYER M4 ;
        RECT  49.596 48.384 49.68 48.408 ;
    END
  END q[278]
  PIN q[279]
    DIRECTION OUTPUT ;
    USE SIGNAL ;
    PORT
      LAYER M4 ;
        RECT  49.596 48.528 49.68 48.552 ;
    END
  END q[279]
  PIN q[27]
    DIRECTION OUTPUT ;
    USE SIGNAL ;
    PORT
      LAYER M4 ;
        RECT  49.596 10.8 49.68 10.824 ;
    END
  END q[27]
  PIN q[280]
    DIRECTION OUTPUT ;
    USE SIGNAL ;
    PORT
      LAYER M4 ;
        RECT  49.596 48.672 49.68 48.696 ;
    END
  END q[280]
  PIN q[281]
    DIRECTION OUTPUT ;
    USE SIGNAL ;
    PORT
      LAYER M4 ;
        RECT  49.596 49.104 49.68 49.128 ;
    END
  END q[281]
  PIN q[282]
    DIRECTION OUTPUT ;
    USE SIGNAL ;
    PORT
      LAYER M4 ;
        RECT  49.596 48.816 49.68 48.84 ;
    END
  END q[282]
  PIN q[283]
    DIRECTION OUTPUT ;
    USE SIGNAL ;
    PORT
      LAYER M4 ;
        RECT  49.596 49.248 49.68 49.272 ;
    END
  END q[283]
  PIN q[284]
    DIRECTION OUTPUT ;
    USE SIGNAL ;
    PORT
      LAYER M4 ;
        RECT  49.596 48.96 49.68 48.984 ;
    END
  END q[284]
  PIN q[285]
    DIRECTION OUTPUT ;
    USE SIGNAL ;
    PORT
      LAYER M4 ;
        RECT  49.596 49.392 49.68 49.416 ;
    END
  END q[285]
  PIN q[286]
    DIRECTION OUTPUT ;
    USE SIGNAL ;
    PORT
      LAYER M4 ;
        RECT  49.596 49.536 49.68 49.56 ;
    END
  END q[286]
  PIN q[287]
    DIRECTION OUTPUT ;
    USE SIGNAL ;
    PORT
      LAYER M4 ;
        RECT  49.596 49.68 49.68 49.704 ;
    END
  END q[287]
  PIN q[288]
    DIRECTION OUTPUT ;
    USE SIGNAL ;
    PORT
      LAYER M4 ;
        RECT  49.596 49.824 49.68 49.848 ;
    END
  END q[288]
  PIN q[289]
    DIRECTION OUTPUT ;
    USE SIGNAL ;
    PORT
      LAYER M4 ;
        RECT  49.596 49.968 49.68 49.992 ;
    END
  END q[289]
  PIN q[28]
    DIRECTION OUTPUT ;
    USE SIGNAL ;
    PORT
      LAYER M4 ;
        RECT  49.596 10.944 49.68 10.968 ;
    END
  END q[28]
  PIN q[290]
    DIRECTION OUTPUT ;
    USE SIGNAL ;
    PORT
      LAYER M4 ;
        RECT  49.596 50.112 49.68 50.136 ;
    END
  END q[290]
  PIN q[291]
    DIRECTION OUTPUT ;
    USE SIGNAL ;
    PORT
      LAYER M4 ;
        RECT  49.596 50.256 49.68 50.28 ;
    END
  END q[291]
  PIN q[292]
    DIRECTION OUTPUT ;
    USE SIGNAL ;
    PORT
      LAYER M4 ;
        RECT  49.596 50.4 49.68 50.424 ;
    END
  END q[292]
  PIN q[293]
    DIRECTION OUTPUT ;
    USE SIGNAL ;
    PORT
      LAYER M4 ;
        RECT  49.596 50.544 49.68 50.568 ;
    END
  END q[293]
  PIN q[294]
    DIRECTION OUTPUT ;
    USE SIGNAL ;
    PORT
      LAYER M4 ;
        RECT  49.596 50.688 49.68 50.712 ;
    END
  END q[294]
  PIN q[295]
    DIRECTION OUTPUT ;
    USE SIGNAL ;
    PORT
      LAYER M4 ;
        RECT  49.596 50.832 49.68 50.856 ;
    END
  END q[295]
  PIN q[296]
    DIRECTION OUTPUT ;
    USE SIGNAL ;
    PORT
      LAYER M4 ;
        RECT  49.596 50.976 49.68 51 ;
    END
  END q[296]
  PIN q[297]
    DIRECTION OUTPUT ;
    USE SIGNAL ;
    PORT
      LAYER M4 ;
        RECT  49.596 51.12 49.68 51.144 ;
    END
  END q[297]
  PIN q[298]
    DIRECTION OUTPUT ;
    USE SIGNAL ;
    PORT
      LAYER M4 ;
        RECT  49.596 51.264 49.68 51.288 ;
    END
  END q[298]
  PIN q[299]
    DIRECTION OUTPUT ;
    USE SIGNAL ;
    PORT
      LAYER M4 ;
        RECT  49.596 51.408 49.68 51.432 ;
    END
  END q[299]
  PIN q[29]
    DIRECTION OUTPUT ;
    USE SIGNAL ;
    PORT
      LAYER M4 ;
        RECT  49.596 11.088 49.68 11.112 ;
    END
  END q[29]
  PIN q[2]
    DIRECTION OUTPUT ;
    USE SIGNAL ;
    PORT
      LAYER M4 ;
        RECT  49.596 7.344 49.68 7.368 ;
    END
  END q[2]
  PIN q[300]
    DIRECTION OUTPUT ;
    USE SIGNAL ;
    PORT
      LAYER M4 ;
        RECT  49.596 51.552 49.68 51.576 ;
    END
  END q[300]
  PIN q[301]
    DIRECTION OUTPUT ;
    USE SIGNAL ;
    PORT
      LAYER M4 ;
        RECT  49.596 51.696 49.68 51.72 ;
    END
  END q[301]
  PIN q[302]
    DIRECTION OUTPUT ;
    USE SIGNAL ;
    PORT
      LAYER M4 ;
        RECT  49.596 51.84 49.68 51.864 ;
    END
  END q[302]
  PIN q[303]
    DIRECTION OUTPUT ;
    USE SIGNAL ;
    PORT
      LAYER M4 ;
        RECT  49.596 51.984 49.68 52.008 ;
    END
  END q[303]
  PIN q[304]
    DIRECTION OUTPUT ;
    USE SIGNAL ;
    PORT
      LAYER M4 ;
        RECT  49.596 52.128 49.68 52.152 ;
    END
  END q[304]
  PIN q[305]
    DIRECTION OUTPUT ;
    USE SIGNAL ;
    PORT
      LAYER M4 ;
        RECT  49.596 52.56 49.68 52.584 ;
    END
  END q[305]
  PIN q[306]
    DIRECTION OUTPUT ;
    USE SIGNAL ;
    PORT
      LAYER M4 ;
        RECT  49.596 52.272 49.68 52.296 ;
    END
  END q[306]
  PIN q[307]
    DIRECTION OUTPUT ;
    USE SIGNAL ;
    PORT
      LAYER M4 ;
        RECT  49.596 52.704 49.68 52.728 ;
    END
  END q[307]
  PIN q[308]
    DIRECTION OUTPUT ;
    USE SIGNAL ;
    PORT
      LAYER M4 ;
        RECT  49.596 52.416 49.68 52.44 ;
    END
  END q[308]
  PIN q[309]
    DIRECTION OUTPUT ;
    USE SIGNAL ;
    PORT
      LAYER M4 ;
        RECT  49.596 52.848 49.68 52.872 ;
    END
  END q[309]
  PIN q[30]
    DIRECTION OUTPUT ;
    USE SIGNAL ;
    PORT
      LAYER M4 ;
        RECT  49.596 11.232 49.68 11.256 ;
    END
  END q[30]
  PIN q[310]
    DIRECTION OUTPUT ;
    USE SIGNAL ;
    PORT
      LAYER M4 ;
        RECT  49.596 52.992 49.68 53.016 ;
    END
  END q[310]
  PIN q[311]
    DIRECTION OUTPUT ;
    USE SIGNAL ;
    PORT
      LAYER M4 ;
        RECT  49.596 53.136 49.68 53.16 ;
    END
  END q[311]
  PIN q[312]
    DIRECTION OUTPUT ;
    USE SIGNAL ;
    PORT
      LAYER M4 ;
        RECT  49.596 53.28 49.68 53.304 ;
    END
  END q[312]
  PIN q[313]
    DIRECTION OUTPUT ;
    USE SIGNAL ;
    PORT
      LAYER M4 ;
        RECT  49.596 53.424 49.68 53.448 ;
    END
  END q[313]
  PIN q[314]
    DIRECTION OUTPUT ;
    USE SIGNAL ;
    PORT
      LAYER M4 ;
        RECT  49.596 53.568 49.68 53.592 ;
    END
  END q[314]
  PIN q[315]
    DIRECTION OUTPUT ;
    USE SIGNAL ;
    PORT
      LAYER M4 ;
        RECT  49.596 53.712 49.68 53.736 ;
    END
  END q[315]
  PIN q[316]
    DIRECTION OUTPUT ;
    USE SIGNAL ;
    PORT
      LAYER M4 ;
        RECT  49.596 53.856 49.68 53.88 ;
    END
  END q[316]
  PIN q[317]
    DIRECTION OUTPUT ;
    USE SIGNAL ;
    PORT
      LAYER M4 ;
        RECT  49.596 54 49.68 54.024 ;
    END
  END q[317]
  PIN q[318]
    DIRECTION OUTPUT ;
    USE SIGNAL ;
    PORT
      LAYER M4 ;
        RECT  49.596 54.144 49.68 54.168 ;
    END
  END q[318]
  PIN q[319]
    DIRECTION OUTPUT ;
    USE SIGNAL ;
    PORT
      LAYER M4 ;
        RECT  49.596 54.288 49.68 54.312 ;
    END
  END q[319]
  PIN q[31]
    DIRECTION OUTPUT ;
    USE SIGNAL ;
    PORT
      LAYER M4 ;
        RECT  49.596 11.376 49.68 11.4 ;
    END
  END q[31]
  PIN q[320]
    DIRECTION OUTPUT ;
    USE SIGNAL ;
    PORT
      LAYER M4 ;
        RECT  49.596 54.432 49.68 54.456 ;
    END
  END q[320]
  PIN q[321]
    DIRECTION OUTPUT ;
    USE SIGNAL ;
    PORT
      LAYER M4 ;
        RECT  49.596 54.576 49.68 54.6 ;
    END
  END q[321]
  PIN q[322]
    DIRECTION OUTPUT ;
    USE SIGNAL ;
    PORT
      LAYER M4 ;
        RECT  49.596 54.72 49.68 54.744 ;
    END
  END q[322]
  PIN q[323]
    DIRECTION OUTPUT ;
    USE SIGNAL ;
    PORT
      LAYER M4 ;
        RECT  49.596 54.864 49.68 54.888 ;
    END
  END q[323]
  PIN q[324]
    DIRECTION OUTPUT ;
    USE SIGNAL ;
    PORT
      LAYER M4 ;
        RECT  49.596 55.008 49.68 55.032 ;
    END
  END q[324]
  PIN q[325]
    DIRECTION OUTPUT ;
    USE SIGNAL ;
    PORT
      LAYER M4 ;
        RECT  49.596 55.152 49.68 55.176 ;
    END
  END q[325]
  PIN q[326]
    DIRECTION OUTPUT ;
    USE SIGNAL ;
    PORT
      LAYER M4 ;
        RECT  49.596 55.296 49.68 55.32 ;
    END
  END q[326]
  PIN q[327]
    DIRECTION OUTPUT ;
    USE SIGNAL ;
    PORT
      LAYER M4 ;
        RECT  49.596 55.44 49.68 55.464 ;
    END
  END q[327]
  PIN q[328]
    DIRECTION OUTPUT ;
    USE SIGNAL ;
    PORT
      LAYER M4 ;
        RECT  49.596 55.584 49.68 55.608 ;
    END
  END q[328]
  PIN q[329]
    DIRECTION OUTPUT ;
    USE SIGNAL ;
    PORT
      LAYER M4 ;
        RECT  49.596 55.728 49.68 55.752 ;
    END
  END q[329]
  PIN q[32]
    DIRECTION OUTPUT ;
    USE SIGNAL ;
    PORT
      LAYER M4 ;
        RECT  49.596 11.808 49.68 11.832 ;
    END
  END q[32]
  PIN q[330]
    DIRECTION OUTPUT ;
    USE SIGNAL ;
    PORT
      LAYER M4 ;
        RECT  49.596 55.872 49.68 55.896 ;
    END
  END q[330]
  PIN q[331]
    DIRECTION OUTPUT ;
    USE SIGNAL ;
    PORT
      LAYER M4 ;
        RECT  49.596 56.304 49.68 56.328 ;
    END
  END q[331]
  PIN q[332]
    DIRECTION OUTPUT ;
    USE SIGNAL ;
    PORT
      LAYER M4 ;
        RECT  49.596 56.016 49.68 56.04 ;
    END
  END q[332]
  PIN q[333]
    DIRECTION OUTPUT ;
    USE SIGNAL ;
    PORT
      LAYER M4 ;
        RECT  49.596 56.448 49.68 56.472 ;
    END
  END q[333]
  PIN q[334]
    DIRECTION OUTPUT ;
    USE SIGNAL ;
    PORT
      LAYER M4 ;
        RECT  49.596 56.16 49.68 56.184 ;
    END
  END q[334]
  PIN q[335]
    DIRECTION OUTPUT ;
    USE SIGNAL ;
    PORT
      LAYER M4 ;
        RECT  49.596 56.592 49.68 56.616 ;
    END
  END q[335]
  PIN q[336]
    DIRECTION OUTPUT ;
    USE SIGNAL ;
    PORT
      LAYER M4 ;
        RECT  49.596 56.736 49.68 56.76 ;
    END
  END q[336]
  PIN q[337]
    DIRECTION OUTPUT ;
    USE SIGNAL ;
    PORT
      LAYER M4 ;
        RECT  49.596 56.88 49.68 56.904 ;
    END
  END q[337]
  PIN q[338]
    DIRECTION OUTPUT ;
    USE SIGNAL ;
    PORT
      LAYER M4 ;
        RECT  49.596 57.024 49.68 57.048 ;
    END
  END q[338]
  PIN q[339]
    DIRECTION OUTPUT ;
    USE SIGNAL ;
    PORT
      LAYER M4 ;
        RECT  49.596 57.168 49.68 57.192 ;
    END
  END q[339]
  PIN q[33]
    DIRECTION OUTPUT ;
    USE SIGNAL ;
    PORT
      LAYER M4 ;
        RECT  49.596 11.52 49.68 11.544 ;
    END
  END q[33]
  PIN q[340]
    DIRECTION OUTPUT ;
    USE SIGNAL ;
    PORT
      LAYER M4 ;
        RECT  49.596 57.312 49.68 57.336 ;
    END
  END q[340]
  PIN q[341]
    DIRECTION OUTPUT ;
    USE SIGNAL ;
    PORT
      LAYER M4 ;
        RECT  49.596 57.456 49.68 57.48 ;
    END
  END q[341]
  PIN q[342]
    DIRECTION OUTPUT ;
    USE SIGNAL ;
    PORT
      LAYER M4 ;
        RECT  49.596 57.6 49.68 57.624 ;
    END
  END q[342]
  PIN q[343]
    DIRECTION OUTPUT ;
    USE SIGNAL ;
    PORT
      LAYER M4 ;
        RECT  49.596 57.744 49.68 57.768 ;
    END
  END q[343]
  PIN q[344]
    DIRECTION OUTPUT ;
    USE SIGNAL ;
    PORT
      LAYER M4 ;
        RECT  49.596 57.888 49.68 57.912 ;
    END
  END q[344]
  PIN q[345]
    DIRECTION OUTPUT ;
    USE SIGNAL ;
    PORT
      LAYER M4 ;
        RECT  49.596 58.032 49.68 58.056 ;
    END
  END q[345]
  PIN q[346]
    DIRECTION OUTPUT ;
    USE SIGNAL ;
    PORT
      LAYER M4 ;
        RECT  49.596 58.176 49.68 58.2 ;
    END
  END q[346]
  PIN q[347]
    DIRECTION OUTPUT ;
    USE SIGNAL ;
    PORT
      LAYER M4 ;
        RECT  49.596 58.32 49.68 58.344 ;
    END
  END q[347]
  PIN q[348]
    DIRECTION OUTPUT ;
    USE SIGNAL ;
    PORT
      LAYER M4 ;
        RECT  49.596 58.464 49.68 58.488 ;
    END
  END q[348]
  PIN q[349]
    DIRECTION OUTPUT ;
    USE SIGNAL ;
    PORT
      LAYER M4 ;
        RECT  49.596 58.608 49.68 58.632 ;
    END
  END q[349]
  PIN q[34]
    DIRECTION OUTPUT ;
    USE SIGNAL ;
    PORT
      LAYER M4 ;
        RECT  49.596 11.952 49.68 11.976 ;
    END
  END q[34]
  PIN q[350]
    DIRECTION OUTPUT ;
    USE SIGNAL ;
    PORT
      LAYER M4 ;
        RECT  49.596 58.752 49.68 58.776 ;
    END
  END q[350]
  PIN q[351]
    DIRECTION OUTPUT ;
    USE SIGNAL ;
    PORT
      LAYER M4 ;
        RECT  49.596 58.896 49.68 58.92 ;
    END
  END q[351]
  PIN q[352]
    DIRECTION OUTPUT ;
    USE SIGNAL ;
    PORT
      LAYER M4 ;
        RECT  49.596 59.04 49.68 59.064 ;
    END
  END q[352]
  PIN q[353]
    DIRECTION OUTPUT ;
    USE SIGNAL ;
    PORT
      LAYER M4 ;
        RECT  49.596 59.184 49.68 59.208 ;
    END
  END q[353]
  PIN q[354]
    DIRECTION OUTPUT ;
    USE SIGNAL ;
    PORT
      LAYER M4 ;
        RECT  49.596 59.328 49.68 59.352 ;
    END
  END q[354]
  PIN q[355]
    DIRECTION OUTPUT ;
    USE SIGNAL ;
    PORT
      LAYER M4 ;
        RECT  49.596 59.76 49.68 59.784 ;
    END
  END q[355]
  PIN q[356]
    DIRECTION OUTPUT ;
    USE SIGNAL ;
    PORT
      LAYER M4 ;
        RECT  49.596 59.472 49.68 59.496 ;
    END
  END q[356]
  PIN q[357]
    DIRECTION OUTPUT ;
    USE SIGNAL ;
    PORT
      LAYER M4 ;
        RECT  49.596 59.904 49.68 59.928 ;
    END
  END q[357]
  PIN q[358]
    DIRECTION OUTPUT ;
    USE SIGNAL ;
    PORT
      LAYER M4 ;
        RECT  49.596 59.616 49.68 59.64 ;
    END
  END q[358]
  PIN q[359]
    DIRECTION OUTPUT ;
    USE SIGNAL ;
    PORT
      LAYER M4 ;
        RECT  49.596 60.048 49.68 60.072 ;
    END
  END q[359]
  PIN q[35]
    DIRECTION OUTPUT ;
    USE SIGNAL ;
    PORT
      LAYER M4 ;
        RECT  49.596 11.664 49.68 11.688 ;
    END
  END q[35]
  PIN q[360]
    DIRECTION OUTPUT ;
    USE SIGNAL ;
    PORT
      LAYER M4 ;
        RECT  49.596 60.192 49.68 60.216 ;
    END
  END q[360]
  PIN q[361]
    DIRECTION OUTPUT ;
    USE SIGNAL ;
    PORT
      LAYER M4 ;
        RECT  49.596 60.336 49.68 60.36 ;
    END
  END q[361]
  PIN q[362]
    DIRECTION OUTPUT ;
    USE SIGNAL ;
    PORT
      LAYER M4 ;
        RECT  49.596 60.48 49.68 60.504 ;
    END
  END q[362]
  PIN q[363]
    DIRECTION OUTPUT ;
    USE SIGNAL ;
    PORT
      LAYER M4 ;
        RECT  49.596 60.624 49.68 60.648 ;
    END
  END q[363]
  PIN q[364]
    DIRECTION OUTPUT ;
    USE SIGNAL ;
    PORT
      LAYER M4 ;
        RECT  49.596 60.768 49.68 60.792 ;
    END
  END q[364]
  PIN q[365]
    DIRECTION OUTPUT ;
    USE SIGNAL ;
    PORT
      LAYER M4 ;
        RECT  49.596 60.912 49.68 60.936 ;
    END
  END q[365]
  PIN q[366]
    DIRECTION OUTPUT ;
    USE SIGNAL ;
    PORT
      LAYER M4 ;
        RECT  49.596 61.056 49.68 61.08 ;
    END
  END q[366]
  PIN q[367]
    DIRECTION OUTPUT ;
    USE SIGNAL ;
    PORT
      LAYER M4 ;
        RECT  49.596 61.2 49.68 61.224 ;
    END
  END q[367]
  PIN q[368]
    DIRECTION OUTPUT ;
    USE SIGNAL ;
    PORT
      LAYER M4 ;
        RECT  49.596 61.344 49.68 61.368 ;
    END
  END q[368]
  PIN q[369]
    DIRECTION OUTPUT ;
    USE SIGNAL ;
    PORT
      LAYER M4 ;
        RECT  49.596 61.488 49.68 61.512 ;
    END
  END q[369]
  PIN q[36]
    DIRECTION OUTPUT ;
    USE SIGNAL ;
    PORT
      LAYER M4 ;
        RECT  49.596 12.24 49.68 12.264 ;
    END
  END q[36]
  PIN q[370]
    DIRECTION OUTPUT ;
    USE SIGNAL ;
    PORT
      LAYER M4 ;
        RECT  49.596 61.632 49.68 61.656 ;
    END
  END q[370]
  PIN q[371]
    DIRECTION OUTPUT ;
    USE SIGNAL ;
    PORT
      LAYER M4 ;
        RECT  49.596 61.776 49.68 61.8 ;
    END
  END q[371]
  PIN q[372]
    DIRECTION OUTPUT ;
    USE SIGNAL ;
    PORT
      LAYER M4 ;
        RECT  49.596 61.92 49.68 61.944 ;
    END
  END q[372]
  PIN q[373]
    DIRECTION OUTPUT ;
    USE SIGNAL ;
    PORT
      LAYER M4 ;
        RECT  49.596 62.064 49.68 62.088 ;
    END
  END q[373]
  PIN q[374]
    DIRECTION OUTPUT ;
    USE SIGNAL ;
    PORT
      LAYER M4 ;
        RECT  49.596 62.208 49.68 62.232 ;
    END
  END q[374]
  PIN q[375]
    DIRECTION OUTPUT ;
    USE SIGNAL ;
    PORT
      LAYER M4 ;
        RECT  49.596 62.352 49.68 62.376 ;
    END
  END q[375]
  PIN q[376]
    DIRECTION OUTPUT ;
    USE SIGNAL ;
    PORT
      LAYER M4 ;
        RECT  49.596 62.496 49.68 62.52 ;
    END
  END q[376]
  PIN q[377]
    DIRECTION OUTPUT ;
    USE SIGNAL ;
    PORT
      LAYER M4 ;
        RECT  49.596 62.64 49.68 62.664 ;
    END
  END q[377]
  PIN q[378]
    DIRECTION OUTPUT ;
    USE SIGNAL ;
    PORT
      LAYER M4 ;
        RECT  49.596 62.784 49.68 62.808 ;
    END
  END q[378]
  PIN q[379]
    DIRECTION OUTPUT ;
    USE SIGNAL ;
    PORT
      LAYER M4 ;
        RECT  49.596 62.928 49.68 62.952 ;
    END
  END q[379]
  PIN q[37]
    DIRECTION OUTPUT ;
    USE SIGNAL ;
    PORT
      LAYER M4 ;
        RECT  49.596 12.096 49.68 12.12 ;
    END
  END q[37]
  PIN q[380]
    DIRECTION OUTPUT ;
    USE SIGNAL ;
    PORT
      LAYER M4 ;
        RECT  49.596 63.072 49.68 63.096 ;
    END
  END q[380]
  PIN q[381]
    DIRECTION OUTPUT ;
    USE SIGNAL ;
    PORT
      LAYER M4 ;
        RECT  49.596 63.504 49.68 63.528 ;
    END
  END q[381]
  PIN q[382]
    DIRECTION OUTPUT ;
    USE SIGNAL ;
    PORT
      LAYER M4 ;
        RECT  49.596 63.216 49.68 63.24 ;
    END
  END q[382]
  PIN q[383]
    DIRECTION OUTPUT ;
    USE SIGNAL ;
    PORT
      LAYER M4 ;
        RECT  49.596 63.648 49.68 63.672 ;
    END
  END q[383]
  PIN q[384]
    DIRECTION OUTPUT ;
    USE SIGNAL ;
    PORT
      LAYER M4 ;
        RECT  49.596 63.36 49.68 63.384 ;
    END
  END q[384]
  PIN q[385]
    DIRECTION OUTPUT ;
    USE SIGNAL ;
    PORT
      LAYER M4 ;
        RECT  49.596 63.792 49.68 63.816 ;
    END
  END q[385]
  PIN q[386]
    DIRECTION OUTPUT ;
    USE SIGNAL ;
    PORT
      LAYER M4 ;
        RECT  49.596 63.936 49.68 63.96 ;
    END
  END q[386]
  PIN q[387]
    DIRECTION OUTPUT ;
    USE SIGNAL ;
    PORT
      LAYER M4 ;
        RECT  49.596 64.08 49.68 64.104 ;
    END
  END q[387]
  PIN q[388]
    DIRECTION OUTPUT ;
    USE SIGNAL ;
    PORT
      LAYER M4 ;
        RECT  49.596 64.224 49.68 64.248 ;
    END
  END q[388]
  PIN q[389]
    DIRECTION OUTPUT ;
    USE SIGNAL ;
    PORT
      LAYER M4 ;
        RECT  49.596 64.368 49.68 64.392 ;
    END
  END q[389]
  PIN q[38]
    DIRECTION OUTPUT ;
    USE SIGNAL ;
    PORT
      LAYER M4 ;
        RECT  49.596 12.384 49.68 12.408 ;
    END
  END q[38]
  PIN q[390]
    DIRECTION OUTPUT ;
    USE SIGNAL ;
    PORT
      LAYER M4 ;
        RECT  49.596 64.512 49.68 64.536 ;
    END
  END q[390]
  PIN q[391]
    DIRECTION OUTPUT ;
    USE SIGNAL ;
    PORT
      LAYER M4 ;
        RECT  49.596 64.656 49.68 64.68 ;
    END
  END q[391]
  PIN q[392]
    DIRECTION OUTPUT ;
    USE SIGNAL ;
    PORT
      LAYER M4 ;
        RECT  49.596 64.8 49.68 64.824 ;
    END
  END q[392]
  PIN q[393]
    DIRECTION OUTPUT ;
    USE SIGNAL ;
    PORT
      LAYER M4 ;
        RECT  49.596 64.944 49.68 64.968 ;
    END
  END q[393]
  PIN q[394]
    DIRECTION OUTPUT ;
    USE SIGNAL ;
    PORT
      LAYER M4 ;
        RECT  49.596 65.088 49.68 65.112 ;
    END
  END q[394]
  PIN q[395]
    DIRECTION OUTPUT ;
    USE SIGNAL ;
    PORT
      LAYER M4 ;
        RECT  49.596 65.232 49.68 65.256 ;
    END
  END q[395]
  PIN q[396]
    DIRECTION OUTPUT ;
    USE SIGNAL ;
    PORT
      LAYER M4 ;
        RECT  49.596 65.376 49.68 65.4 ;
    END
  END q[396]
  PIN q[397]
    DIRECTION OUTPUT ;
    USE SIGNAL ;
    PORT
      LAYER M4 ;
        RECT  49.596 65.52 49.68 65.544 ;
    END
  END q[397]
  PIN q[398]
    DIRECTION OUTPUT ;
    USE SIGNAL ;
    PORT
      LAYER M4 ;
        RECT  49.596 65.664 49.68 65.688 ;
    END
  END q[398]
  PIN q[399]
    DIRECTION OUTPUT ;
    USE SIGNAL ;
    PORT
      LAYER M4 ;
        RECT  49.596 65.808 49.68 65.832 ;
    END
  END q[399]
  PIN q[39]
    DIRECTION OUTPUT ;
    USE SIGNAL ;
    PORT
      LAYER M4 ;
        RECT  49.596 12.528 49.68 12.552 ;
    END
  END q[39]
  PIN q[3]
    DIRECTION OUTPUT ;
    USE SIGNAL ;
    PORT
      LAYER M4 ;
        RECT  49.596 7.2 49.68 7.224 ;
    END
  END q[3]
  PIN q[400]
    DIRECTION OUTPUT ;
    USE SIGNAL ;
    PORT
      LAYER M4 ;
        RECT  49.596 65.952 49.68 65.976 ;
    END
  END q[400]
  PIN q[401]
    DIRECTION OUTPUT ;
    USE SIGNAL ;
    PORT
      LAYER M4 ;
        RECT  49.596 66.096 49.68 66.12 ;
    END
  END q[401]
  PIN q[402]
    DIRECTION OUTPUT ;
    USE SIGNAL ;
    PORT
      LAYER M4 ;
        RECT  49.596 66.24 49.68 66.264 ;
    END
  END q[402]
  PIN q[403]
    DIRECTION OUTPUT ;
    USE SIGNAL ;
    PORT
      LAYER M4 ;
        RECT  49.596 66.384 49.68 66.408 ;
    END
  END q[403]
  PIN q[404]
    DIRECTION OUTPUT ;
    USE SIGNAL ;
    PORT
      LAYER M4 ;
        RECT  49.596 66.528 49.68 66.552 ;
    END
  END q[404]
  PIN q[405]
    DIRECTION OUTPUT ;
    USE SIGNAL ;
    PORT
      LAYER M4 ;
        RECT  49.596 66.96 49.68 66.984 ;
    END
  END q[405]
  PIN q[406]
    DIRECTION OUTPUT ;
    USE SIGNAL ;
    PORT
      LAYER M4 ;
        RECT  49.596 66.672 49.68 66.696 ;
    END
  END q[406]
  PIN q[407]
    DIRECTION OUTPUT ;
    USE SIGNAL ;
    PORT
      LAYER M4 ;
        RECT  49.596 67.104 49.68 67.128 ;
    END
  END q[407]
  PIN q[408]
    DIRECTION OUTPUT ;
    USE SIGNAL ;
    PORT
      LAYER M4 ;
        RECT  49.596 66.816 49.68 66.84 ;
    END
  END q[408]
  PIN q[409]
    DIRECTION OUTPUT ;
    USE SIGNAL ;
    PORT
      LAYER M4 ;
        RECT  49.596 67.248 49.68 67.272 ;
    END
  END q[409]
  PIN q[40]
    DIRECTION OUTPUT ;
    USE SIGNAL ;
    PORT
      LAYER M4 ;
        RECT  49.596 12.816 49.68 12.84 ;
    END
  END q[40]
  PIN q[410]
    DIRECTION OUTPUT ;
    USE SIGNAL ;
    PORT
      LAYER M4 ;
        RECT  49.596 67.392 49.68 67.416 ;
    END
  END q[410]
  PIN q[411]
    DIRECTION OUTPUT ;
    USE SIGNAL ;
    PORT
      LAYER M4 ;
        RECT  49.596 67.536 49.68 67.56 ;
    END
  END q[411]
  PIN q[412]
    DIRECTION OUTPUT ;
    USE SIGNAL ;
    PORT
      LAYER M4 ;
        RECT  49.596 67.68 49.68 67.704 ;
    END
  END q[412]
  PIN q[413]
    DIRECTION OUTPUT ;
    USE SIGNAL ;
    PORT
      LAYER M4 ;
        RECT  49.596 67.824 49.68 67.848 ;
    END
  END q[413]
  PIN q[414]
    DIRECTION OUTPUT ;
    USE SIGNAL ;
    PORT
      LAYER M4 ;
        RECT  49.596 67.968 49.68 67.992 ;
    END
  END q[414]
  PIN q[415]
    DIRECTION OUTPUT ;
    USE SIGNAL ;
    PORT
      LAYER M4 ;
        RECT  49.596 68.112 49.68 68.136 ;
    END
  END q[415]
  PIN q[416]
    DIRECTION OUTPUT ;
    USE SIGNAL ;
    PORT
      LAYER M4 ;
        RECT  49.596 68.256 49.68 68.28 ;
    END
  END q[416]
  PIN q[417]
    DIRECTION OUTPUT ;
    USE SIGNAL ;
    PORT
      LAYER M4 ;
        RECT  49.596 68.4 49.68 68.424 ;
    END
  END q[417]
  PIN q[418]
    DIRECTION OUTPUT ;
    USE SIGNAL ;
    PORT
      LAYER M4 ;
        RECT  49.596 68.544 49.68 68.568 ;
    END
  END q[418]
  PIN q[419]
    DIRECTION OUTPUT ;
    USE SIGNAL ;
    PORT
      LAYER M4 ;
        RECT  49.596 68.688 49.68 68.712 ;
    END
  END q[419]
  PIN q[41]
    DIRECTION OUTPUT ;
    USE SIGNAL ;
    PORT
      LAYER M4 ;
        RECT  49.596 12.672 49.68 12.696 ;
    END
  END q[41]
  PIN q[420]
    DIRECTION OUTPUT ;
    USE SIGNAL ;
    PORT
      LAYER M4 ;
        RECT  49.596 68.832 49.68 68.856 ;
    END
  END q[420]
  PIN q[421]
    DIRECTION OUTPUT ;
    USE SIGNAL ;
    PORT
      LAYER M4 ;
        RECT  49.596 68.976 49.68 69 ;
    END
  END q[421]
  PIN q[422]
    DIRECTION OUTPUT ;
    USE SIGNAL ;
    PORT
      LAYER M4 ;
        RECT  49.596 69.12 49.68 69.144 ;
    END
  END q[422]
  PIN q[423]
    DIRECTION OUTPUT ;
    USE SIGNAL ;
    PORT
      LAYER M4 ;
        RECT  49.596 69.264 49.68 69.288 ;
    END
  END q[423]
  PIN q[424]
    DIRECTION OUTPUT ;
    USE SIGNAL ;
    PORT
      LAYER M4 ;
        RECT  49.596 69.408 49.68 69.432 ;
    END
  END q[424]
  PIN q[425]
    DIRECTION OUTPUT ;
    USE SIGNAL ;
    PORT
      LAYER M4 ;
        RECT  49.596 69.552 49.68 69.576 ;
    END
  END q[425]
  PIN q[426]
    DIRECTION OUTPUT ;
    USE SIGNAL ;
    PORT
      LAYER M4 ;
        RECT  49.596 69.696 49.68 69.72 ;
    END
  END q[426]
  PIN q[427]
    DIRECTION OUTPUT ;
    USE SIGNAL ;
    PORT
      LAYER M4 ;
        RECT  49.596 69.84 49.68 69.864 ;
    END
  END q[427]
  PIN q[428]
    DIRECTION OUTPUT ;
    USE SIGNAL ;
    PORT
      LAYER M4 ;
        RECT  49.596 69.984 49.68 70.008 ;
    END
  END q[428]
  PIN q[429]
    DIRECTION OUTPUT ;
    USE SIGNAL ;
    PORT
      LAYER M4 ;
        RECT  49.596 70.272 49.68 70.296 ;
    END
  END q[429]
  PIN q[42]
    DIRECTION OUTPUT ;
    USE SIGNAL ;
    PORT
      LAYER M4 ;
        RECT  49.596 12.96 49.68 12.984 ;
    END
  END q[42]
  PIN q[430]
    DIRECTION OUTPUT ;
    USE SIGNAL ;
    PORT
      LAYER M4 ;
        RECT  49.596 70.128 49.68 70.152 ;
    END
  END q[430]
  PIN q[431]
    DIRECTION OUTPUT ;
    USE SIGNAL ;
    PORT
      LAYER M4 ;
        RECT  49.596 70.704 49.68 70.728 ;
    END
  END q[431]
  PIN q[432]
    DIRECTION OUTPUT ;
    USE SIGNAL ;
    PORT
      LAYER M4 ;
        RECT  49.596 70.416 49.68 70.44 ;
    END
  END q[432]
  PIN q[433]
    DIRECTION OUTPUT ;
    USE SIGNAL ;
    PORT
      LAYER M4 ;
        RECT  49.596 70.848 49.68 70.872 ;
    END
  END q[433]
  PIN q[434]
    DIRECTION OUTPUT ;
    USE SIGNAL ;
    PORT
      LAYER M4 ;
        RECT  49.596 70.56 49.68 70.584 ;
    END
  END q[434]
  PIN q[435]
    DIRECTION OUTPUT ;
    USE SIGNAL ;
    PORT
      LAYER M4 ;
        RECT  49.596 70.992 49.68 71.016 ;
    END
  END q[435]
  PIN q[436]
    DIRECTION OUTPUT ;
    USE SIGNAL ;
    PORT
      LAYER M4 ;
        RECT  49.596 71.136 49.68 71.16 ;
    END
  END q[436]
  PIN q[437]
    DIRECTION OUTPUT ;
    USE SIGNAL ;
    PORT
      LAYER M4 ;
        RECT  49.596 71.28 49.68 71.304 ;
    END
  END q[437]
  PIN q[438]
    DIRECTION OUTPUT ;
    USE SIGNAL ;
    PORT
      LAYER M4 ;
        RECT  49.596 71.424 49.68 71.448 ;
    END
  END q[438]
  PIN q[439]
    DIRECTION OUTPUT ;
    USE SIGNAL ;
    PORT
      LAYER M4 ;
        RECT  49.596 71.568 49.68 71.592 ;
    END
  END q[439]
  PIN q[43]
    DIRECTION OUTPUT ;
    USE SIGNAL ;
    PORT
      LAYER M4 ;
        RECT  49.596 13.104 49.68 13.128 ;
    END
  END q[43]
  PIN q[440]
    DIRECTION OUTPUT ;
    USE SIGNAL ;
    PORT
      LAYER M4 ;
        RECT  49.596 71.712 49.68 71.736 ;
    END
  END q[440]
  PIN q[441]
    DIRECTION OUTPUT ;
    USE SIGNAL ;
    PORT
      LAYER M4 ;
        RECT  49.596 71.856 49.68 71.88 ;
    END
  END q[441]
  PIN q[442]
    DIRECTION OUTPUT ;
    USE SIGNAL ;
    PORT
      LAYER M4 ;
        RECT  49.596 72 49.68 72.024 ;
    END
  END q[442]
  PIN q[443]
    DIRECTION OUTPUT ;
    USE SIGNAL ;
    PORT
      LAYER M4 ;
        RECT  49.596 72.144 49.68 72.168 ;
    END
  END q[443]
  PIN q[444]
    DIRECTION OUTPUT ;
    USE SIGNAL ;
    PORT
      LAYER M4 ;
        RECT  49.596 72.288 49.68 72.312 ;
    END
  END q[444]
  PIN q[445]
    DIRECTION OUTPUT ;
    USE SIGNAL ;
    PORT
      LAYER M4 ;
        RECT  49.596 72.432 49.68 72.456 ;
    END
  END q[445]
  PIN q[446]
    DIRECTION OUTPUT ;
    USE SIGNAL ;
    PORT
      LAYER M4 ;
        RECT  49.596 72.576 49.68 72.6 ;
    END
  END q[446]
  PIN q[447]
    DIRECTION OUTPUT ;
    USE SIGNAL ;
    PORT
      LAYER M4 ;
        RECT  49.596 72.72 49.68 72.744 ;
    END
  END q[447]
  PIN q[448]
    DIRECTION OUTPUT ;
    USE SIGNAL ;
    PORT
      LAYER M4 ;
        RECT  49.596 72.864 49.68 72.888 ;
    END
  END q[448]
  PIN q[449]
    DIRECTION OUTPUT ;
    USE SIGNAL ;
    PORT
      LAYER M4 ;
        RECT  49.596 73.008 49.68 73.032 ;
    END
  END q[449]
  PIN q[44]
    DIRECTION OUTPUT ;
    USE SIGNAL ;
    PORT
      LAYER M4 ;
        RECT  49.596 13.248 49.68 13.272 ;
    END
  END q[44]
  PIN q[450]
    DIRECTION OUTPUT ;
    USE SIGNAL ;
    PORT
      LAYER M4 ;
        RECT  49.596 73.152 49.68 73.176 ;
    END
  END q[450]
  PIN q[451]
    DIRECTION OUTPUT ;
    USE SIGNAL ;
    PORT
      LAYER M4 ;
        RECT  49.596 73.296 49.68 73.32 ;
    END
  END q[451]
  PIN q[452]
    DIRECTION OUTPUT ;
    USE SIGNAL ;
    PORT
      LAYER M4 ;
        RECT  49.596 73.44 49.68 73.464 ;
    END
  END q[452]
  PIN q[453]
    DIRECTION OUTPUT ;
    USE SIGNAL ;
    PORT
      LAYER M4 ;
        RECT  49.596 73.584 49.68 73.608 ;
    END
  END q[453]
  PIN q[454]
    DIRECTION OUTPUT ;
    USE SIGNAL ;
    PORT
      LAYER M4 ;
        RECT  49.596 73.728 49.68 73.752 ;
    END
  END q[454]
  PIN q[455]
    DIRECTION OUTPUT ;
    USE SIGNAL ;
    PORT
      LAYER M4 ;
        RECT  49.596 74.16 49.68 74.184 ;
    END
  END q[455]
  PIN q[456]
    DIRECTION OUTPUT ;
    USE SIGNAL ;
    PORT
      LAYER M4 ;
        RECT  49.596 73.872 49.68 73.896 ;
    END
  END q[456]
  PIN q[457]
    DIRECTION OUTPUT ;
    USE SIGNAL ;
    PORT
      LAYER M4 ;
        RECT  49.596 74.304 49.68 74.328 ;
    END
  END q[457]
  PIN q[458]
    DIRECTION OUTPUT ;
    USE SIGNAL ;
    PORT
      LAYER M4 ;
        RECT  49.596 74.016 49.68 74.04 ;
    END
  END q[458]
  PIN q[459]
    DIRECTION OUTPUT ;
    USE SIGNAL ;
    PORT
      LAYER M4 ;
        RECT  49.596 74.448 49.68 74.472 ;
    END
  END q[459]
  PIN q[45]
    DIRECTION OUTPUT ;
    USE SIGNAL ;
    PORT
      LAYER M4 ;
        RECT  49.596 13.392 49.68 13.416 ;
    END
  END q[45]
  PIN q[460]
    DIRECTION OUTPUT ;
    USE SIGNAL ;
    PORT
      LAYER M4 ;
        RECT  49.596 74.592 49.68 74.616 ;
    END
  END q[460]
  PIN q[461]
    DIRECTION OUTPUT ;
    USE SIGNAL ;
    PORT
      LAYER M4 ;
        RECT  49.596 74.736 49.68 74.76 ;
    END
  END q[461]
  PIN q[462]
    DIRECTION OUTPUT ;
    USE SIGNAL ;
    PORT
      LAYER M4 ;
        RECT  49.596 74.88 49.68 74.904 ;
    END
  END q[462]
  PIN q[463]
    DIRECTION OUTPUT ;
    USE SIGNAL ;
    PORT
      LAYER M4 ;
        RECT  49.596 75.024 49.68 75.048 ;
    END
  END q[463]
  PIN q[464]
    DIRECTION OUTPUT ;
    USE SIGNAL ;
    PORT
      LAYER M4 ;
        RECT  49.596 75.168 49.68 75.192 ;
    END
  END q[464]
  PIN q[465]
    DIRECTION OUTPUT ;
    USE SIGNAL ;
    PORT
      LAYER M4 ;
        RECT  49.596 75.312 49.68 75.336 ;
    END
  END q[465]
  PIN q[466]
    DIRECTION OUTPUT ;
    USE SIGNAL ;
    PORT
      LAYER M4 ;
        RECT  49.596 75.456 49.68 75.48 ;
    END
  END q[466]
  PIN q[467]
    DIRECTION OUTPUT ;
    USE SIGNAL ;
    PORT
      LAYER M4 ;
        RECT  49.596 75.6 49.68 75.624 ;
    END
  END q[467]
  PIN q[468]
    DIRECTION OUTPUT ;
    USE SIGNAL ;
    PORT
      LAYER M4 ;
        RECT  49.596 75.744 49.68 75.768 ;
    END
  END q[468]
  PIN q[469]
    DIRECTION OUTPUT ;
    USE SIGNAL ;
    PORT
      LAYER M4 ;
        RECT  49.596 75.888 49.68 75.912 ;
    END
  END q[469]
  PIN q[46]
    DIRECTION OUTPUT ;
    USE SIGNAL ;
    PORT
      LAYER M4 ;
        RECT  49.596 13.536 49.68 13.56 ;
    END
  END q[46]
  PIN q[470]
    DIRECTION OUTPUT ;
    USE SIGNAL ;
    PORT
      LAYER M4 ;
        RECT  49.596 76.032 49.68 76.056 ;
    END
  END q[470]
  PIN q[471]
    DIRECTION OUTPUT ;
    USE SIGNAL ;
    PORT
      LAYER M4 ;
        RECT  49.596 76.176 49.68 76.2 ;
    END
  END q[471]
  PIN q[472]
    DIRECTION OUTPUT ;
    USE SIGNAL ;
    PORT
      LAYER M4 ;
        RECT  49.596 76.32 49.68 76.344 ;
    END
  END q[472]
  PIN q[473]
    DIRECTION OUTPUT ;
    USE SIGNAL ;
    PORT
      LAYER M4 ;
        RECT  49.596 76.464 49.68 76.488 ;
    END
  END q[473]
  PIN q[474]
    DIRECTION OUTPUT ;
    USE SIGNAL ;
    PORT
      LAYER M4 ;
        RECT  49.596 76.608 49.68 76.632 ;
    END
  END q[474]
  PIN q[475]
    DIRECTION OUTPUT ;
    USE SIGNAL ;
    PORT
      LAYER M4 ;
        RECT  49.596 76.752 49.68 76.776 ;
    END
  END q[475]
  PIN q[476]
    DIRECTION OUTPUT ;
    USE SIGNAL ;
    PORT
      LAYER M4 ;
        RECT  49.596 76.896 49.68 76.92 ;
    END
  END q[476]
  PIN q[477]
    DIRECTION OUTPUT ;
    USE SIGNAL ;
    PORT
      LAYER M4 ;
        RECT  49.596 77.04 49.68 77.064 ;
    END
  END q[477]
  PIN q[478]
    DIRECTION OUTPUT ;
    USE SIGNAL ;
    PORT
      LAYER M4 ;
        RECT  49.596 77.184 49.68 77.208 ;
    END
  END q[478]
  PIN q[479]
    DIRECTION OUTPUT ;
    USE SIGNAL ;
    PORT
      LAYER M4 ;
        RECT  49.596 77.472 49.68 77.496 ;
    END
  END q[479]
  PIN q[47]
    DIRECTION OUTPUT ;
    USE SIGNAL ;
    PORT
      LAYER M4 ;
        RECT  49.596 13.68 49.68 13.704 ;
    END
  END q[47]
  PIN q[480]
    DIRECTION OUTPUT ;
    USE SIGNAL ;
    PORT
      LAYER M4 ;
        RECT  49.596 77.328 49.68 77.352 ;
    END
  END q[480]
  PIN q[481]
    DIRECTION OUTPUT ;
    USE SIGNAL ;
    PORT
      LAYER M4 ;
        RECT  49.596 77.904 49.68 77.928 ;
    END
  END q[481]
  PIN q[482]
    DIRECTION OUTPUT ;
    USE SIGNAL ;
    PORT
      LAYER M4 ;
        RECT  49.596 77.616 49.68 77.64 ;
    END
  END q[482]
  PIN q[483]
    DIRECTION OUTPUT ;
    USE SIGNAL ;
    PORT
      LAYER M4 ;
        RECT  49.596 78.048 49.68 78.072 ;
    END
  END q[483]
  PIN q[484]
    DIRECTION OUTPUT ;
    USE SIGNAL ;
    PORT
      LAYER M4 ;
        RECT  49.596 77.76 49.68 77.784 ;
    END
  END q[484]
  PIN q[485]
    DIRECTION OUTPUT ;
    USE SIGNAL ;
    PORT
      LAYER M4 ;
        RECT  49.596 78.192 49.68 78.216 ;
    END
  END q[485]
  PIN q[486]
    DIRECTION OUTPUT ;
    USE SIGNAL ;
    PORT
      LAYER M4 ;
        RECT  49.596 78.336 49.68 78.36 ;
    END
  END q[486]
  PIN q[487]
    DIRECTION OUTPUT ;
    USE SIGNAL ;
    PORT
      LAYER M4 ;
        RECT  49.596 78.48 49.68 78.504 ;
    END
  END q[487]
  PIN q[488]
    DIRECTION OUTPUT ;
    USE SIGNAL ;
    PORT
      LAYER M4 ;
        RECT  49.596 78.624 49.68 78.648 ;
    END
  END q[488]
  PIN q[489]
    DIRECTION OUTPUT ;
    USE SIGNAL ;
    PORT
      LAYER M4 ;
        RECT  49.596 78.912 49.68 78.936 ;
    END
  END q[489]
  PIN q[48]
    DIRECTION OUTPUT ;
    USE SIGNAL ;
    PORT
      LAYER M4 ;
        RECT  49.596 13.824 49.68 13.848 ;
    END
  END q[48]
  PIN q[490]
    DIRECTION OUTPUT ;
    USE SIGNAL ;
    PORT
      LAYER M4 ;
        RECT  49.596 78.768 49.68 78.792 ;
    END
  END q[490]
  PIN q[491]
    DIRECTION OUTPUT ;
    USE SIGNAL ;
    PORT
      LAYER M4 ;
        RECT  49.596 79.056 49.68 79.08 ;
    END
  END q[491]
  PIN q[492]
    DIRECTION OUTPUT ;
    USE SIGNAL ;
    PORT
      LAYER M4 ;
        RECT  49.596 79.2 49.68 79.224 ;
    END
  END q[492]
  PIN q[493]
    DIRECTION OUTPUT ;
    USE SIGNAL ;
    PORT
      LAYER M4 ;
        RECT  49.596 79.344 49.68 79.368 ;
    END
  END q[493]
  PIN q[494]
    DIRECTION OUTPUT ;
    USE SIGNAL ;
    PORT
      LAYER M4 ;
        RECT  49.596 79.488 49.68 79.512 ;
    END
  END q[494]
  PIN q[495]
    DIRECTION OUTPUT ;
    USE SIGNAL ;
    PORT
      LAYER M4 ;
        RECT  49.596 79.632 49.68 79.656 ;
    END
  END q[495]
  PIN q[496]
    DIRECTION OUTPUT ;
    USE SIGNAL ;
    PORT
      LAYER M4 ;
        RECT  49.596 79.776 49.68 79.8 ;
    END
  END q[496]
  PIN q[497]
    DIRECTION OUTPUT ;
    USE SIGNAL ;
    PORT
      LAYER M4 ;
        RECT  49.596 79.92 49.68 79.944 ;
    END
  END q[497]
  PIN q[498]
    DIRECTION OUTPUT ;
    USE SIGNAL ;
    PORT
      LAYER M4 ;
        RECT  49.596 80.064 49.68 80.088 ;
    END
  END q[498]
  PIN q[499]
    DIRECTION OUTPUT ;
    USE SIGNAL ;
    PORT
      LAYER M4 ;
        RECT  49.596 80.352 49.68 80.376 ;
    END
  END q[499]
  PIN q[49]
    DIRECTION OUTPUT ;
    USE SIGNAL ;
    PORT
      LAYER M4 ;
        RECT  49.596 13.968 49.68 13.992 ;
    END
  END q[49]
  PIN q[4]
    DIRECTION OUTPUT ;
    USE SIGNAL ;
    PORT
      LAYER M4 ;
        RECT  49.596 7.488 49.68 7.512 ;
    END
  END q[4]
  PIN q[500]
    DIRECTION OUTPUT ;
    USE SIGNAL ;
    PORT
      LAYER M4 ;
        RECT  49.596 80.208 49.68 80.232 ;
    END
  END q[500]
  PIN q[501]
    DIRECTION OUTPUT ;
    USE SIGNAL ;
    PORT
      LAYER M4 ;
        RECT  49.596 80.496 49.68 80.52 ;
    END
  END q[501]
  PIN q[502]
    DIRECTION OUTPUT ;
    USE SIGNAL ;
    PORT
      LAYER M4 ;
        RECT  49.596 80.64 49.68 80.664 ;
    END
  END q[502]
  PIN q[503]
    DIRECTION OUTPUT ;
    USE SIGNAL ;
    PORT
      LAYER M4 ;
        RECT  49.596 80.784 49.68 80.808 ;
    END
  END q[503]
  PIN q[504]
    DIRECTION OUTPUT ;
    USE SIGNAL ;
    PORT
      LAYER M4 ;
        RECT  49.596 80.928 49.68 80.952 ;
    END
  END q[504]
  PIN q[505]
    DIRECTION OUTPUT ;
    USE SIGNAL ;
    PORT
      LAYER M4 ;
        RECT  49.596 81.36 49.68 81.384 ;
    END
  END q[505]
  PIN q[506]
    DIRECTION OUTPUT ;
    USE SIGNAL ;
    PORT
      LAYER M4 ;
        RECT  49.596 81.072 49.68 81.096 ;
    END
  END q[506]
  PIN q[507]
    DIRECTION OUTPUT ;
    USE SIGNAL ;
    PORT
      LAYER M4 ;
        RECT  49.596 81.504 49.68 81.528 ;
    END
  END q[507]
  PIN q[508]
    DIRECTION OUTPUT ;
    USE SIGNAL ;
    PORT
      LAYER M4 ;
        RECT  49.596 81.216 49.68 81.24 ;
    END
  END q[508]
  PIN q[509]
    DIRECTION OUTPUT ;
    USE SIGNAL ;
    PORT
      LAYER M4 ;
        RECT  49.596 81.648 49.68 81.672 ;
    END
  END q[509]
  PIN q[50]
    DIRECTION OUTPUT ;
    USE SIGNAL ;
    PORT
      LAYER M4 ;
        RECT  49.596 14.112 49.68 14.136 ;
    END
  END q[50]
  PIN q[510]
    DIRECTION OUTPUT ;
    USE SIGNAL ;
    PORT
      LAYER M4 ;
        RECT  49.596 81.792 49.68 81.816 ;
    END
  END q[510]
  PIN q[511]
    DIRECTION OUTPUT ;
    USE SIGNAL ;
    PORT
      LAYER M4 ;
        RECT  49.596 81.936 49.68 81.96 ;
    END
  END q[511]
  PIN q[512]
    DIRECTION OUTPUT ;
    USE SIGNAL ;
    PORT
      LAYER M4 ;
        RECT  49.596 82.08 49.68 82.104 ;
    END
  END q[512]
  PIN q[513]
    DIRECTION OUTPUT ;
    USE SIGNAL ;
    PORT
      LAYER M4 ;
        RECT  49.596 82.224 49.68 82.248 ;
    END
  END q[513]
  PIN q[514]
    DIRECTION OUTPUT ;
    USE SIGNAL ;
    PORT
      LAYER M4 ;
        RECT  49.596 82.368 49.68 82.392 ;
    END
  END q[514]
  PIN q[515]
    DIRECTION OUTPUT ;
    USE SIGNAL ;
    PORT
      LAYER M4 ;
        RECT  49.596 82.512 49.68 82.536 ;
    END
  END q[515]
  PIN q[516]
    DIRECTION OUTPUT ;
    USE SIGNAL ;
    PORT
      LAYER M4 ;
        RECT  49.596 82.656 49.68 82.68 ;
    END
  END q[516]
  PIN q[517]
    DIRECTION OUTPUT ;
    USE SIGNAL ;
    PORT
      LAYER M4 ;
        RECT  49.596 82.8 49.68 82.824 ;
    END
  END q[517]
  PIN q[518]
    DIRECTION OUTPUT ;
    USE SIGNAL ;
    PORT
      LAYER M4 ;
        RECT  49.596 82.944 49.68 82.968 ;
    END
  END q[518]
  PIN q[519]
    DIRECTION OUTPUT ;
    USE SIGNAL ;
    PORT
      LAYER M4 ;
        RECT  49.596 83.232 49.68 83.256 ;
    END
  END q[519]
  PIN q[51]
    DIRECTION OUTPUT ;
    USE SIGNAL ;
    PORT
      LAYER M4 ;
        RECT  49.596 14.256 49.68 14.28 ;
    END
  END q[51]
  PIN q[520]
    DIRECTION OUTPUT ;
    USE SIGNAL ;
    PORT
      LAYER M4 ;
        RECT  49.596 83.088 49.68 83.112 ;
    END
  END q[520]
  PIN q[521]
    DIRECTION OUTPUT ;
    USE SIGNAL ;
    PORT
      LAYER M4 ;
        RECT  49.596 83.376 49.68 83.4 ;
    END
  END q[521]
  PIN q[522]
    DIRECTION OUTPUT ;
    USE SIGNAL ;
    PORT
      LAYER M4 ;
        RECT  49.596 83.52 49.68 83.544 ;
    END
  END q[522]
  PIN q[523]
    DIRECTION OUTPUT ;
    USE SIGNAL ;
    PORT
      LAYER M4 ;
        RECT  49.596 83.664 49.68 83.688 ;
    END
  END q[523]
  PIN q[524]
    DIRECTION OUTPUT ;
    USE SIGNAL ;
    PORT
      LAYER M4 ;
        RECT  49.596 83.808 49.68 83.832 ;
    END
  END q[524]
  PIN q[525]
    DIRECTION OUTPUT ;
    USE SIGNAL ;
    PORT
      LAYER M4 ;
        RECT  49.596 83.952 49.68 83.976 ;
    END
  END q[525]
  PIN q[526]
    DIRECTION OUTPUT ;
    USE SIGNAL ;
    PORT
      LAYER M4 ;
        RECT  49.596 84.096 49.68 84.12 ;
    END
  END q[526]
  PIN q[527]
    DIRECTION OUTPUT ;
    USE SIGNAL ;
    PORT
      LAYER M4 ;
        RECT  49.596 84.24 49.68 84.264 ;
    END
  END q[527]
  PIN q[528]
    DIRECTION OUTPUT ;
    USE SIGNAL ;
    PORT
      LAYER M4 ;
        RECT  49.596 84.384 49.68 84.408 ;
    END
  END q[528]
  PIN q[529]
    DIRECTION OUTPUT ;
    USE SIGNAL ;
    PORT
      LAYER M4 ;
        RECT  49.596 84.816 49.68 84.84 ;
    END
  END q[529]
  PIN q[52]
    DIRECTION OUTPUT ;
    USE SIGNAL ;
    PORT
      LAYER M4 ;
        RECT  49.596 14.4 49.68 14.424 ;
    END
  END q[52]
  PIN q[530]
    DIRECTION OUTPUT ;
    USE SIGNAL ;
    PORT
      LAYER M4 ;
        RECT  49.596 84.528 49.68 84.552 ;
    END
  END q[530]
  PIN q[531]
    DIRECTION OUTPUT ;
    USE SIGNAL ;
    PORT
      LAYER M4 ;
        RECT  49.596 85.104 49.68 85.128 ;
    END
  END q[531]
  PIN q[532]
    DIRECTION OUTPUT ;
    USE SIGNAL ;
    PORT
      LAYER M4 ;
        RECT  49.596 84.672 49.68 84.696 ;
    END
  END q[532]
  PIN q[533]
    DIRECTION OUTPUT ;
    USE SIGNAL ;
    PORT
      LAYER M4 ;
        RECT  49.596 85.248 49.68 85.272 ;
    END
  END q[533]
  PIN q[534]
    DIRECTION OUTPUT ;
    USE SIGNAL ;
    PORT
      LAYER M4 ;
        RECT  49.596 84.96 49.68 84.984 ;
    END
  END q[534]
  PIN q[535]
    DIRECTION OUTPUT ;
    USE SIGNAL ;
    PORT
      LAYER M4 ;
        RECT  49.596 85.392 49.68 85.416 ;
    END
  END q[535]
  PIN q[536]
    DIRECTION OUTPUT ;
    USE SIGNAL ;
    PORT
      LAYER M4 ;
        RECT  49.596 85.536 49.68 85.56 ;
    END
  END q[536]
  PIN q[53]
    DIRECTION OUTPUT ;
    USE SIGNAL ;
    PORT
      LAYER M4 ;
        RECT  49.596 14.544 49.68 14.568 ;
    END
  END q[53]
  PIN q[54]
    DIRECTION OUTPUT ;
    USE SIGNAL ;
    PORT
      LAYER M4 ;
        RECT  49.596 14.688 49.68 14.712 ;
    END
  END q[54]
  PIN q[55]
    DIRECTION OUTPUT ;
    USE SIGNAL ;
    PORT
      LAYER M4 ;
        RECT  49.596 14.832 49.68 14.856 ;
    END
  END q[55]
  PIN q[56]
    DIRECTION OUTPUT ;
    USE SIGNAL ;
    PORT
      LAYER M4 ;
        RECT  49.596 14.976 49.68 15 ;
    END
  END q[56]
  PIN q[57]
    DIRECTION OUTPUT ;
    USE SIGNAL ;
    PORT
      LAYER M4 ;
        RECT  49.596 15.12 49.68 15.144 ;
    END
  END q[57]
  PIN q[58]
    DIRECTION OUTPUT ;
    USE SIGNAL ;
    PORT
      LAYER M4 ;
        RECT  49.596 15.552 49.68 15.576 ;
    END
  END q[58]
  PIN q[59]
    DIRECTION OUTPUT ;
    USE SIGNAL ;
    PORT
      LAYER M4 ;
        RECT  49.596 15.264 49.68 15.288 ;
    END
  END q[59]
  PIN q[5]
    DIRECTION OUTPUT ;
    USE SIGNAL ;
    PORT
      LAYER M4 ;
        RECT  49.596 7.632 49.68 7.656 ;
    END
  END q[5]
  PIN q[60]
    DIRECTION OUTPUT ;
    USE SIGNAL ;
    PORT
      LAYER M4 ;
        RECT  49.596 15.696 49.68 15.72 ;
    END
  END q[60]
  PIN q[61]
    DIRECTION OUTPUT ;
    USE SIGNAL ;
    PORT
      LAYER M4 ;
        RECT  49.596 15.408 49.68 15.432 ;
    END
  END q[61]
  PIN q[62]
    DIRECTION OUTPUT ;
    USE SIGNAL ;
    PORT
      LAYER M4 ;
        RECT  49.596 15.84 49.68 15.864 ;
    END
  END q[62]
  PIN q[63]
    DIRECTION OUTPUT ;
    USE SIGNAL ;
    PORT
      LAYER M4 ;
        RECT  49.596 15.984 49.68 16.008 ;
    END
  END q[63]
  PIN q[64]
    DIRECTION OUTPUT ;
    USE SIGNAL ;
    PORT
      LAYER M4 ;
        RECT  49.596 16.128 49.68 16.152 ;
    END
  END q[64]
  PIN q[65]
    DIRECTION OUTPUT ;
    USE SIGNAL ;
    PORT
      LAYER M4 ;
        RECT  49.596 16.272 49.68 16.296 ;
    END
  END q[65]
  PIN q[66]
    DIRECTION OUTPUT ;
    USE SIGNAL ;
    PORT
      LAYER M4 ;
        RECT  49.596 16.416 49.68 16.44 ;
    END
  END q[66]
  PIN q[67]
    DIRECTION OUTPUT ;
    USE SIGNAL ;
    PORT
      LAYER M4 ;
        RECT  49.596 16.56 49.68 16.584 ;
    END
  END q[67]
  PIN q[68]
    DIRECTION OUTPUT ;
    USE SIGNAL ;
    PORT
      LAYER M4 ;
        RECT  49.596 16.704 49.68 16.728 ;
    END
  END q[68]
  PIN q[69]
    DIRECTION OUTPUT ;
    USE SIGNAL ;
    PORT
      LAYER M4 ;
        RECT  49.596 16.848 49.68 16.872 ;
    END
  END q[69]
  PIN q[6]
    DIRECTION OUTPUT ;
    USE SIGNAL ;
    PORT
      LAYER M4 ;
        RECT  49.596 7.776 49.68 7.8 ;
    END
  END q[6]
  PIN q[70]
    DIRECTION OUTPUT ;
    USE SIGNAL ;
    PORT
      LAYER M4 ;
        RECT  49.596 16.992 49.68 17.016 ;
    END
  END q[70]
  PIN q[71]
    DIRECTION OUTPUT ;
    USE SIGNAL ;
    PORT
      LAYER M4 ;
        RECT  49.596 17.136 49.68 17.16 ;
    END
  END q[71]
  PIN q[72]
    DIRECTION OUTPUT ;
    USE SIGNAL ;
    PORT
      LAYER M4 ;
        RECT  49.596 17.28 49.68 17.304 ;
    END
  END q[72]
  PIN q[73]
    DIRECTION OUTPUT ;
    USE SIGNAL ;
    PORT
      LAYER M4 ;
        RECT  49.596 17.424 49.68 17.448 ;
    END
  END q[73]
  PIN q[74]
    DIRECTION OUTPUT ;
    USE SIGNAL ;
    PORT
      LAYER M4 ;
        RECT  49.596 17.568 49.68 17.592 ;
    END
  END q[74]
  PIN q[75]
    DIRECTION OUTPUT ;
    USE SIGNAL ;
    PORT
      LAYER M4 ;
        RECT  49.596 17.712 49.68 17.736 ;
    END
  END q[75]
  PIN q[76]
    DIRECTION OUTPUT ;
    USE SIGNAL ;
    PORT
      LAYER M4 ;
        RECT  49.596 17.856 49.68 17.88 ;
    END
  END q[76]
  PIN q[77]
    DIRECTION OUTPUT ;
    USE SIGNAL ;
    PORT
      LAYER M4 ;
        RECT  49.596 18 49.68 18.024 ;
    END
  END q[77]
  PIN q[78]
    DIRECTION OUTPUT ;
    USE SIGNAL ;
    PORT
      LAYER M4 ;
        RECT  49.596 18.144 49.68 18.168 ;
    END
  END q[78]
  PIN q[79]
    DIRECTION OUTPUT ;
    USE SIGNAL ;
    PORT
      LAYER M4 ;
        RECT  49.596 18.288 49.68 18.312 ;
    END
  END q[79]
  PIN q[7]
    DIRECTION OUTPUT ;
    USE SIGNAL ;
    PORT
      LAYER M4 ;
        RECT  49.596 7.92 49.68 7.944 ;
    END
  END q[7]
  PIN q[80]
    DIRECTION OUTPUT ;
    USE SIGNAL ;
    PORT
      LAYER M4 ;
        RECT  49.596 18.432 49.68 18.456 ;
    END
  END q[80]
  PIN q[81]
    DIRECTION OUTPUT ;
    USE SIGNAL ;
    PORT
      LAYER M4 ;
        RECT  49.596 18.576 49.68 18.6 ;
    END
  END q[81]
  PIN q[82]
    DIRECTION OUTPUT ;
    USE SIGNAL ;
    PORT
      LAYER M4 ;
        RECT  49.596 19.008 49.68 19.032 ;
    END
  END q[82]
  PIN q[83]
    DIRECTION OUTPUT ;
    USE SIGNAL ;
    PORT
      LAYER M4 ;
        RECT  49.596 18.72 49.68 18.744 ;
    END
  END q[83]
  PIN q[84]
    DIRECTION OUTPUT ;
    USE SIGNAL ;
    PORT
      LAYER M4 ;
        RECT  49.596 19.152 49.68 19.176 ;
    END
  END q[84]
  PIN q[85]
    DIRECTION OUTPUT ;
    USE SIGNAL ;
    PORT
      LAYER M4 ;
        RECT  49.596 18.864 49.68 18.888 ;
    END
  END q[85]
  PIN q[86]
    DIRECTION OUTPUT ;
    USE SIGNAL ;
    PORT
      LAYER M4 ;
        RECT  49.596 19.44 49.68 19.464 ;
    END
  END q[86]
  PIN q[87]
    DIRECTION OUTPUT ;
    USE SIGNAL ;
    PORT
      LAYER M4 ;
        RECT  49.596 19.296 49.68 19.32 ;
    END
  END q[87]
  PIN q[88]
    DIRECTION OUTPUT ;
    USE SIGNAL ;
    PORT
      LAYER M4 ;
        RECT  49.596 19.584 49.68 19.608 ;
    END
  END q[88]
  PIN q[89]
    DIRECTION OUTPUT ;
    USE SIGNAL ;
    PORT
      LAYER M4 ;
        RECT  49.596 19.728 49.68 19.752 ;
    END
  END q[89]
  PIN q[8]
    DIRECTION OUTPUT ;
    USE SIGNAL ;
    PORT
      LAYER M4 ;
        RECT  49.596 8.352 49.68 8.376 ;
    END
  END q[8]
  PIN q[90]
    DIRECTION OUTPUT ;
    USE SIGNAL ;
    PORT
      LAYER M4 ;
        RECT  49.596 19.872 49.68 19.896 ;
    END
  END q[90]
  PIN q[91]
    DIRECTION OUTPUT ;
    USE SIGNAL ;
    PORT
      LAYER M4 ;
        RECT  49.596 20.016 49.68 20.04 ;
    END
  END q[91]
  PIN q[92]
    DIRECTION OUTPUT ;
    USE SIGNAL ;
    PORT
      LAYER M4 ;
        RECT  49.596 20.16 49.68 20.184 ;
    END
  END q[92]
  PIN q[93]
    DIRECTION OUTPUT ;
    USE SIGNAL ;
    PORT
      LAYER M4 ;
        RECT  49.596 20.304 49.68 20.328 ;
    END
  END q[93]
  PIN q[94]
    DIRECTION OUTPUT ;
    USE SIGNAL ;
    PORT
      LAYER M4 ;
        RECT  49.596 20.448 49.68 20.472 ;
    END
  END q[94]
  PIN q[95]
    DIRECTION OUTPUT ;
    USE SIGNAL ;
    PORT
      LAYER M4 ;
        RECT  49.596 20.592 49.68 20.616 ;
    END
  END q[95]
  PIN q[96]
    DIRECTION OUTPUT ;
    USE SIGNAL ;
    PORT
      LAYER M4 ;
        RECT  49.596 20.736 49.68 20.76 ;
    END
  END q[96]
  PIN q[97]
    DIRECTION OUTPUT ;
    USE SIGNAL ;
    PORT
      LAYER M4 ;
        RECT  49.596 20.88 49.68 20.904 ;
    END
  END q[97]
  PIN q[98]
    DIRECTION OUTPUT ;
    USE SIGNAL ;
    PORT
      LAYER M4 ;
        RECT  49.596 21.024 49.68 21.048 ;
    END
  END q[98]
  PIN q[99]
    DIRECTION OUTPUT ;
    USE SIGNAL ;
    PORT
      LAYER M4 ;
        RECT  49.596 21.168 49.68 21.192 ;
    END
  END q[99]
  PIN q[9]
    DIRECTION OUTPUT ;
    USE SIGNAL ;
    PORT
      LAYER M4 ;
        RECT  49.596 8.064 49.68 8.088 ;
    END
  END q[9]
  PIN ready
    DIRECTION OUTPUT ;
    USE SIGNAL ;
    PORT
      LAYER M4 ;
        RECT  49.596 45.792 49.68 45.816 ;
    END
  END ready
  PIN rst_n
    DIRECTION INPUT ;
    USE SIGNAL ;
    PORT
      LAYER M4 ;
        RECT  49.596 45.648 49.68 45.672 ;
    END
  END rst_n
  PIN strap_k[0]
    DIRECTION INPUT ;
    USE SIGNAL ;
    PORT
      LAYER M4 ;
        RECT  49.596 46.08 49.68 46.104 ;
    END
  END strap_k[0]
  PIN strap_k[1]
    DIRECTION INPUT ;
    USE SIGNAL ;
    PORT
      LAYER M4 ;
        RECT  49.596 46.224 49.68 46.248 ;
    END
  END strap_k[1]
  PIN strap_k[2]
    DIRECTION INPUT ;
    USE SIGNAL ;
    PORT
      LAYER M4 ;
        RECT  49.596 46.368 49.68 46.392 ;
    END
  END strap_k[2]
  PIN strap_k[3]
    DIRECTION INPUT ;
    USE SIGNAL ;
    PORT
      LAYER M4 ;
        RECT  49.596 46.512 49.68 46.536 ;
    END
  END strap_k[3]
  PIN strap_k[4]
    DIRECTION INPUT ;
    USE SIGNAL ;
    PORT
      LAYER M4 ;
        RECT  49.596 46.656 49.68 46.68 ;
    END
  END strap_k[4]
  PIN strap_k[5]
    DIRECTION INPUT ;
    USE SIGNAL ;
    PORT
      LAYER M4 ;
        RECT  49.596 46.8 49.68 46.824 ;
    END
  END strap_k[5]
  PIN t_rst_n
    DIRECTION INPUT ;
    USE SIGNAL ;
    PORT
      LAYER M4 ;
        RECT  0 46.224 0.084 46.248 ;
    END
  END t_rst_n
  PIN VDD
    DIRECTION INOUT ;
    USE POWER ;
    PORT
      LAYER M5 ;
        RECT  41.076 4.311 41.196 88.029 ;
        RECT  36.756 4.311 36.876 88.029 ;
        RECT  32.436 4.311 32.556 88.029 ;
        RECT  28.116 4.311 28.236 88.029 ;
        RECT  23.796 4.311 23.916 88.029 ;
        RECT  19.476 4.311 19.596 88.029 ;
        RECT  15.156 4.311 15.276 88.029 ;
        RECT  10.836 4.311 10.956 88.029 ;
        RECT  6.516 4.311 6.636 88.029 ;
    END
  END VDD
  PIN VSS
    DIRECTION INOUT ;
    USE GROUND ;
    PORT
      LAYER M5 ;
        RECT  45.204 4.297 45.324 88.043 ;
        RECT  40.884 4.297 41.004 88.043 ;
        RECT  36.564 4.297 36.684 88.043 ;
        RECT  32.244 4.297 32.364 88.043 ;
        RECT  27.924 4.297 28.044 88.043 ;
        RECT  23.604 4.297 23.724 88.043 ;
        RECT  19.284 4.297 19.404 88.043 ;
        RECT  14.964 4.297 15.084 88.043 ;
        RECT  10.644 4.297 10.764 88.043 ;
        RECT  6.324 4.297 6.444 88.043 ;
    END
  END VSS
  OBS
    LAYER RVTN ;
     RECT  0 4.117 49.68 88.151 ;
    LAYER RVTP ;
     RECT  0 4.117 49.68 88.151 ;
    LAYER M1 ;
     RECT  0 4.117 49.68 88.151 ;
    LAYER M2 ;
     RECT  0 4.117 49.68 88.151 ;
    LAYER M3 ;
     RECT  0 4.117 49.68 88.151 ;
    LAYER M4 ;
     RECT  0 4.117 49.68 88.151 ;
    LAYER M5 ;
     RECT  0 4.117 49.68 88.151 ;
  END
END sle_cland_w537_w
END LIBRARY
